VERSION 5.8 ;
BUSBITCHARS "[]" ;
DIVIDERCHAR "/" ;
UNITS
    DATABASE MICRONS 1000 ;
END UNITS

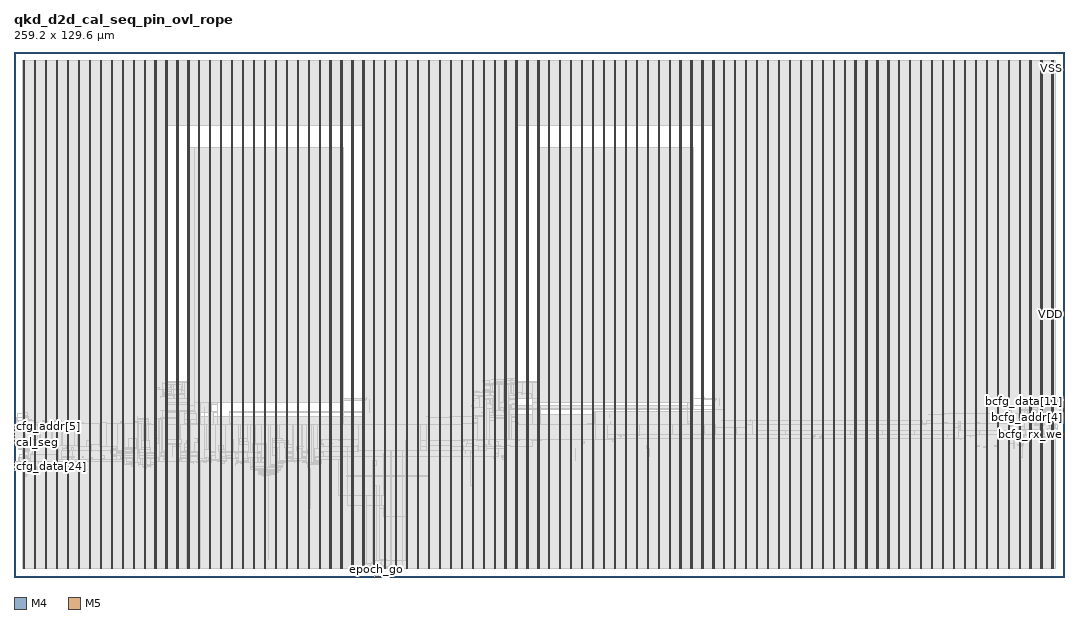
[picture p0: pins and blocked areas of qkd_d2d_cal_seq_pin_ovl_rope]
MACRO qkd_d2d_cal_seq_pin_ovl_rope
  FOREIGN qkd_d2d_cal_seq_pin_ovl_rope 0 0 ;
  CLASS BLOCK ;
  SIZE 259.2 BY 129.6 ;
  PIN adm_done
    DIRECTION OUTPUT ;
    USE SIGNAL ;
    PORT
      LAYER M4 ;
        RECT  259.116 38.736 259.2 38.76 ;
    END
  END adm_done
  PIN bcfg_addr[0]
    DIRECTION INPUT ;
    USE SIGNAL ;
    PORT
      LAYER M4 ;
        RECT  259.116 38.88 259.2 38.904 ;
    END
  END bcfg_addr[0]
  PIN bcfg_addr[1]
    DIRECTION INPUT ;
    USE SIGNAL ;
    PORT
      LAYER M4 ;
        RECT  259.116 39.024 259.2 39.048 ;
    END
  END bcfg_addr[1]
  PIN bcfg_addr[2]
    DIRECTION INPUT ;
    USE SIGNAL ;
    PORT
      LAYER M4 ;
        RECT  259.116 39.168 259.2 39.192 ;
    END
  END bcfg_addr[2]
  PIN bcfg_addr[3]
    DIRECTION INPUT ;
    USE SIGNAL ;
    PORT
      LAYER M4 ;
        RECT  259.116 39.312 259.2 39.336 ;
    END
  END bcfg_addr[3]
  PIN bcfg_addr[4]
    DIRECTION INPUT ;
    USE SIGNAL ;
    PORT
      LAYER M4 ;
        RECT  259.116 39.456 259.2 39.48 ;
    END
  END bcfg_addr[4]
  PIN bcfg_addr[5]
    DIRECTION INPUT ;
    USE SIGNAL ;
    PORT
      LAYER M4 ;
        RECT  259.116 39.6 259.2 39.624 ;
    END
  END bcfg_addr[5]
  PIN bcfg_data[0]
    DIRECTION INPUT ;
    USE SIGNAL ;
    PORT
      LAYER M4 ;
        RECT  259.116 39.744 259.2 39.768 ;
    END
  END bcfg_data[0]
  PIN bcfg_data[10]
    DIRECTION INPUT ;
    USE SIGNAL ;
    PORT
      LAYER M4 ;
        RECT  259.116 41.184 259.2 41.208 ;
    END
  END bcfg_data[10]
  PIN bcfg_data[11]
    DIRECTION INPUT ;
    USE SIGNAL ;
    PORT
      LAYER M4 ;
        RECT  259.116 41.328 259.2 41.352 ;
    END
  END bcfg_data[11]
  PIN bcfg_data[12]
    DIRECTION INPUT ;
    USE SIGNAL ;
    PORT
      LAYER M4 ;
        RECT  259.116 41.472 259.2 41.496 ;
    END
  END bcfg_data[12]
  PIN bcfg_data[13]
    DIRECTION INPUT ;
    USE SIGNAL ;
    PORT
      LAYER M4 ;
        RECT  259.116 41.616 259.2 41.64 ;
    END
  END bcfg_data[13]
  PIN bcfg_data[14]
    DIRECTION INPUT ;
    USE SIGNAL ;
    PORT
      LAYER M4 ;
        RECT  259.116 41.76 259.2 41.784 ;
    END
  END bcfg_data[14]
  PIN bcfg_data[15]
    DIRECTION INPUT ;
    USE SIGNAL ;
    PORT
      LAYER M4 ;
        RECT  259.116 41.904 259.2 41.928 ;
    END
  END bcfg_data[15]
  PIN bcfg_data[16]
    DIRECTION INPUT ;
    USE SIGNAL ;
    PORT
      LAYER M4 ;
        RECT  259.116 42.048 259.2 42.072 ;
    END
  END bcfg_data[16]
  PIN bcfg_data[17]
    DIRECTION INPUT ;
    USE SIGNAL ;
    PORT
      LAYER M4 ;
        RECT  259.116 42.192 259.2 42.216 ;
    END
  END bcfg_data[17]
  PIN bcfg_data[18]
    DIRECTION INPUT ;
    USE SIGNAL ;
    PORT
      LAYER M4 ;
        RECT  259.116 42.336 259.2 42.36 ;
    END
  END bcfg_data[18]
  PIN bcfg_data[19]
    DIRECTION INPUT ;
    USE SIGNAL ;
    PORT
      LAYER M4 ;
        RECT  259.116 42.48 259.2 42.504 ;
    END
  END bcfg_data[19]
  PIN bcfg_data[1]
    DIRECTION INPUT ;
    USE SIGNAL ;
    PORT
      LAYER M4 ;
        RECT  259.116 39.888 259.2 39.912 ;
    END
  END bcfg_data[1]
  PIN bcfg_data[20]
    DIRECTION INPUT ;
    USE SIGNAL ;
    PORT
      LAYER M4 ;
        RECT  259.116 42.624 259.2 42.648 ;
    END
  END bcfg_data[20]
  PIN bcfg_data[21]
    DIRECTION INPUT ;
    USE SIGNAL ;
    PORT
      LAYER M4 ;
        RECT  259.116 42.768 259.2 42.792 ;
    END
  END bcfg_data[21]
  PIN bcfg_data[22]
    DIRECTION INPUT ;
    USE SIGNAL ;
    PORT
      LAYER M4 ;
        RECT  259.116 42.912 259.2 42.936 ;
    END
  END bcfg_data[22]
  PIN bcfg_data[23]
    DIRECTION INPUT ;
    USE SIGNAL ;
    PORT
      LAYER M4 ;
        RECT  259.116 43.056 259.2 43.08 ;
    END
  END bcfg_data[23]
  PIN bcfg_data[24]
    DIRECTION INPUT ;
    USE SIGNAL ;
    PORT
      LAYER M4 ;
        RECT  259.116 43.2 259.2 43.224 ;
    END
  END bcfg_data[24]
  PIN bcfg_data[25]
    DIRECTION INPUT ;
    USE SIGNAL ;
    PORT
      LAYER M4 ;
        RECT  259.116 34.128 259.2 34.152 ;
    END
  END bcfg_data[25]
  PIN bcfg_data[26]
    DIRECTION INPUT ;
    USE SIGNAL ;
    PORT
      LAYER M4 ;
        RECT  259.116 34.272 259.2 34.296 ;
    END
  END bcfg_data[26]
  PIN bcfg_data[27]
    DIRECTION INPUT ;
    USE SIGNAL ;
    PORT
      LAYER M4 ;
        RECT  259.116 34.416 259.2 34.44 ;
    END
  END bcfg_data[27]
  PIN bcfg_data[28]
    DIRECTION INPUT ;
    USE SIGNAL ;
    PORT
      LAYER M4 ;
        RECT  259.116 34.56 259.2 34.584 ;
    END
  END bcfg_data[28]
  PIN bcfg_data[29]
    DIRECTION INPUT ;
    USE SIGNAL ;
    PORT
      LAYER M4 ;
        RECT  259.116 34.704 259.2 34.728 ;
    END
  END bcfg_data[29]
  PIN bcfg_data[2]
    DIRECTION INPUT ;
    USE SIGNAL ;
    PORT
      LAYER M4 ;
        RECT  259.116 40.032 259.2 40.056 ;
    END
  END bcfg_data[2]
  PIN bcfg_data[30]
    DIRECTION INPUT ;
    USE SIGNAL ;
    PORT
      LAYER M4 ;
        RECT  259.116 34.848 259.2 34.872 ;
    END
  END bcfg_data[30]
  PIN bcfg_data[31]
    DIRECTION INPUT ;
    USE SIGNAL ;
    PORT
      LAYER M4 ;
        RECT  259.116 34.992 259.2 35.016 ;
    END
  END bcfg_data[31]
  PIN bcfg_data[3]
    DIRECTION INPUT ;
    USE SIGNAL ;
    PORT
      LAYER M4 ;
        RECT  259.116 40.176 259.2 40.2 ;
    END
  END bcfg_data[3]
  PIN bcfg_data[4]
    DIRECTION INPUT ;
    USE SIGNAL ;
    PORT
      LAYER M4 ;
        RECT  259.116 40.32 259.2 40.344 ;
    END
  END bcfg_data[4]
  PIN bcfg_data[5]
    DIRECTION INPUT ;
    USE SIGNAL ;
    PORT
      LAYER M4 ;
        RECT  259.116 40.464 259.2 40.488 ;
    END
  END bcfg_data[5]
  PIN bcfg_data[6]
    DIRECTION INPUT ;
    USE SIGNAL ;
    PORT
      LAYER M4 ;
        RECT  259.116 40.608 259.2 40.632 ;
    END
  END bcfg_data[6]
  PIN bcfg_data[7]
    DIRECTION INPUT ;
    USE SIGNAL ;
    PORT
      LAYER M4 ;
        RECT  259.116 40.752 259.2 40.776 ;
    END
  END bcfg_data[7]
  PIN bcfg_data[8]
    DIRECTION INPUT ;
    USE SIGNAL ;
    PORT
      LAYER M4 ;
        RECT  259.116 40.896 259.2 40.92 ;
    END
  END bcfg_data[8]
  PIN bcfg_data[9]
    DIRECTION INPUT ;
    USE SIGNAL ;
    PORT
      LAYER M4 ;
        RECT  259.116 41.04 259.2 41.064 ;
    END
  END bcfg_data[9]
  PIN bcfg_rx_we
    DIRECTION INPUT ;
    USE SIGNAL ;
    PORT
      LAYER M4 ;
        RECT  259.116 35.136 259.2 35.16 ;
    END
  END bcfg_rx_we
  PIN bcfg_tx_we
    DIRECTION INPUT ;
    USE SIGNAL ;
    PORT
      LAYER M4 ;
        RECT  259.116 35.28 259.2 35.304 ;
    END
  END bcfg_tx_we
  PIN cal_ready
    DIRECTION OUTPUT ;
    USE SIGNAL ;
    PORT
      LAYER M4 ;
        RECT  259.116 35.424 259.2 35.448 ;
    END
  END cal_ready
  PIN cal_seg
    DIRECTION OUTPUT ;
    USE SIGNAL ;
    PORT
      LAYER M4 ;
        RECT  0 33.264 0.084 33.288 ;
    END
  END cal_seg
  PIN cal_seg_rx
    DIRECTION OUTPUT ;
    USE SIGNAL ;
    PORT
      LAYER M4 ;
        RECT  0 33.408 0.084 33.432 ;
    END
  END cal_seg_rx
  PIN cal_start
    DIRECTION OUTPUT ;
    USE SIGNAL ;
    PORT
      LAYER M4 ;
        RECT  0 33.552 0.084 33.576 ;
    END
  END cal_start
  PIN cal_start_rx
    DIRECTION OUTPUT ;
    USE SIGNAL ;
    PORT
      LAYER M4 ;
        RECT  0 33.696 0.084 33.72 ;
    END
  END cal_start_rx
  PIN cal_user_rx[0]
    DIRECTION OUTPUT ;
    USE SIGNAL ;
    PORT
      LAYER M4 ;
        RECT  0 33.84 0.084 33.864 ;
    END
  END cal_user_rx[0]
  PIN cal_user_rx[1]
    DIRECTION OUTPUT ;
    USE SIGNAL ;
    PORT
      LAYER M4 ;
        RECT  0 33.984 0.084 34.008 ;
    END
  END cal_user_rx[1]
  PIN cal_user_tx[0]
    DIRECTION OUTPUT ;
    USE SIGNAL ;
    PORT
      LAYER M4 ;
        RECT  0 34.128 0.084 34.152 ;
    END
  END cal_user_tx[0]
  PIN cal_user_tx[1]
    DIRECTION OUTPUT ;
    USE SIGNAL ;
    PORT
      LAYER M4 ;
        RECT  0 34.272 0.084 34.296 ;
    END
  END cal_user_tx[1]
  PIN cfg_addr[0]
    DIRECTION OUTPUT ;
    USE SIGNAL ;
    PORT
      LAYER M4 ;
        RECT  0 34.416 0.084 34.44 ;
    END
  END cfg_addr[0]
  PIN cfg_addr[1]
    DIRECTION OUTPUT ;
    USE SIGNAL ;
    PORT
      LAYER M4 ;
        RECT  0 34.56 0.084 34.584 ;
    END
  END cfg_addr[1]
  PIN cfg_addr[2]
    DIRECTION OUTPUT ;
    USE SIGNAL ;
    PORT
      LAYER M4 ;
        RECT  0 34.704 0.084 34.728 ;
    END
  END cfg_addr[2]
  PIN cfg_addr[3]
    DIRECTION OUTPUT ;
    USE SIGNAL ;
    PORT
      LAYER M4 ;
        RECT  0 34.848 0.084 34.872 ;
    END
  END cfg_addr[3]
  PIN cfg_addr[4]
    DIRECTION OUTPUT ;
    USE SIGNAL ;
    PORT
      LAYER M4 ;
        RECT  0 34.992 0.084 35.016 ;
    END
  END cfg_addr[4]
  PIN cfg_addr[5]
    DIRECTION OUTPUT ;
    USE SIGNAL ;
    PORT
      LAYER M4 ;
        RECT  0 35.136 0.084 35.16 ;
    END
  END cfg_addr[5]
  PIN cfg_data[0]
    DIRECTION OUTPUT ;
    USE SIGNAL ;
    PORT
      LAYER M4 ;
        RECT  0 35.28 0.084 35.304 ;
    END
  END cfg_data[0]
  PIN cfg_data[10]
    DIRECTION OUTPUT ;
    USE SIGNAL ;
    PORT
      LAYER M4 ;
        RECT  0 36.72 0.084 36.744 ;
    END
  END cfg_data[10]
  PIN cfg_data[11]
    DIRECTION OUTPUT ;
    USE SIGNAL ;
    PORT
      LAYER M4 ;
        RECT  0 36.864 0.084 36.888 ;
    END
  END cfg_data[11]
  PIN cfg_data[12]
    DIRECTION OUTPUT ;
    USE SIGNAL ;
    PORT
      LAYER M4 ;
        RECT  0 37.008 0.084 37.032 ;
    END
  END cfg_data[12]
  PIN cfg_data[13]
    DIRECTION OUTPUT ;
    USE SIGNAL ;
    PORT
      LAYER M4 ;
        RECT  0 37.152 0.084 37.176 ;
    END
  END cfg_data[13]
  PIN cfg_data[14]
    DIRECTION OUTPUT ;
    USE SIGNAL ;
    PORT
      LAYER M4 ;
        RECT  0 37.296 0.084 37.32 ;
    END
  END cfg_data[14]
  PIN cfg_data[15]
    DIRECTION OUTPUT ;
    USE SIGNAL ;
    PORT
      LAYER M4 ;
        RECT  0 37.44 0.084 37.464 ;
    END
  END cfg_data[15]
  PIN cfg_data[16]
    DIRECTION OUTPUT ;
    USE SIGNAL ;
    PORT
      LAYER M4 ;
        RECT  0 37.584 0.084 37.608 ;
    END
  END cfg_data[16]
  PIN cfg_data[17]
    DIRECTION OUTPUT ;
    USE SIGNAL ;
    PORT
      LAYER M4 ;
        RECT  0 37.728 0.084 37.752 ;
    END
  END cfg_data[17]
  PIN cfg_data[18]
    DIRECTION OUTPUT ;
    USE SIGNAL ;
    PORT
      LAYER M4 ;
        RECT  0 26.352 0.084 26.376 ;
    END
  END cfg_data[18]
  PIN cfg_data[19]
    DIRECTION OUTPUT ;
    USE SIGNAL ;
    PORT
      LAYER M4 ;
        RECT  0 26.496 0.084 26.52 ;
    END
  END cfg_data[19]
  PIN cfg_data[1]
    DIRECTION OUTPUT ;
    USE SIGNAL ;
    PORT
      LAYER M4 ;
        RECT  0 35.424 0.084 35.448 ;
    END
  END cfg_data[1]
  PIN cfg_data[20]
    DIRECTION OUTPUT ;
    USE SIGNAL ;
    PORT
      LAYER M4 ;
        RECT  0 26.64 0.084 26.664 ;
    END
  END cfg_data[20]
  PIN cfg_data[21]
    DIRECTION OUTPUT ;
    USE SIGNAL ;
    PORT
      LAYER M4 ;
        RECT  0 26.784 0.084 26.808 ;
    END
  END cfg_data[21]
  PIN cfg_data[22]
    DIRECTION OUTPUT ;
    USE SIGNAL ;
    PORT
      LAYER M4 ;
        RECT  0 26.928 0.084 26.952 ;
    END
  END cfg_data[22]
  PIN cfg_data[23]
    DIRECTION OUTPUT ;
    USE SIGNAL ;
    PORT
      LAYER M4 ;
        RECT  0 27.072 0.084 27.096 ;
    END
  END cfg_data[23]
  PIN cfg_data[24]
    DIRECTION OUTPUT ;
    USE SIGNAL ;
    PORT
      LAYER M4 ;
        RECT  0 27.216 0.084 27.24 ;
    END
  END cfg_data[24]
  PIN cfg_data[25]
    DIRECTION OUTPUT ;
    USE SIGNAL ;
    PORT
      LAYER M4 ;
        RECT  0 27.36 0.084 27.384 ;
    END
  END cfg_data[25]
  PIN cfg_data[26]
    DIRECTION OUTPUT ;
    USE SIGNAL ;
    PORT
      LAYER M4 ;
        RECT  0 27.504 0.084 27.528 ;
    END
  END cfg_data[26]
  PIN cfg_data[27]
    DIRECTION OUTPUT ;
    USE SIGNAL ;
    PORT
      LAYER M4 ;
        RECT  0 27.648 0.084 27.672 ;
    END
  END cfg_data[27]
  PIN cfg_data[28]
    DIRECTION OUTPUT ;
    USE SIGNAL ;
    PORT
      LAYER M4 ;
        RECT  0 27.792 0.084 27.816 ;
    END
  END cfg_data[28]
  PIN cfg_data[29]
    DIRECTION OUTPUT ;
    USE SIGNAL ;
    PORT
      LAYER M4 ;
        RECT  0 27.936 0.084 27.96 ;
    END
  END cfg_data[29]
  PIN cfg_data[2]
    DIRECTION OUTPUT ;
    USE SIGNAL ;
    PORT
      LAYER M4 ;
        RECT  0 35.568 0.084 35.592 ;
    END
  END cfg_data[2]
  PIN cfg_data[30]
    DIRECTION OUTPUT ;
    USE SIGNAL ;
    PORT
      LAYER M4 ;
        RECT  0 28.08 0.084 28.104 ;
    END
  END cfg_data[30]
  PIN cfg_data[31]
    DIRECTION OUTPUT ;
    USE SIGNAL ;
    PORT
      LAYER M4 ;
        RECT  0 28.224 0.084 28.248 ;
    END
  END cfg_data[31]
  PIN cfg_data[3]
    DIRECTION OUTPUT ;
    USE SIGNAL ;
    PORT
      LAYER M4 ;
        RECT  0 35.712 0.084 35.736 ;
    END
  END cfg_data[3]
  PIN cfg_data[4]
    DIRECTION OUTPUT ;
    USE SIGNAL ;
    PORT
      LAYER M4 ;
        RECT  0 35.856 0.084 35.88 ;
    END
  END cfg_data[4]
  PIN cfg_data[5]
    DIRECTION OUTPUT ;
    USE SIGNAL ;
    PORT
      LAYER M4 ;
        RECT  0 36 0.084 36.024 ;
    END
  END cfg_data[5]
  PIN cfg_data[6]
    DIRECTION OUTPUT ;
    USE SIGNAL ;
    PORT
      LAYER M4 ;
        RECT  0 36.144 0.084 36.168 ;
    END
  END cfg_data[6]
  PIN cfg_data[7]
    DIRECTION OUTPUT ;
    USE SIGNAL ;
    PORT
      LAYER M4 ;
        RECT  0 36.288 0.084 36.312 ;
    END
  END cfg_data[7]
  PIN cfg_data[8]
    DIRECTION OUTPUT ;
    USE SIGNAL ;
    PORT
      LAYER M4 ;
        RECT  0 36.432 0.084 36.456 ;
    END
  END cfg_data[8]
  PIN cfg_data[9]
    DIRECTION OUTPUT ;
    USE SIGNAL ;
    PORT
      LAYER M4 ;
        RECT  0 36.576 0.084 36.6 ;
    END
  END cfg_data[9]
  PIN cfg_rx_we
    DIRECTION OUTPUT ;
    USE SIGNAL ;
    PORT
      LAYER M4 ;
        RECT  0 28.368 0.084 28.392 ;
    END
  END cfg_rx_we
  PIN cfg_tx_we
    DIRECTION OUTPUT ;
    USE SIGNAL ;
    PORT
      LAYER M4 ;
        RECT  0 28.512 0.084 28.536 ;
    END
  END cfg_tx_we
  PIN ck
    DIRECTION INPUT ;
    USE SIGNAL ;
    PORT
      LAYER M5 ;
        RECT  89.28 0 89.304 0.084 ;
    END
  END ck
  PIN epoch_go
    DIRECTION INPUT ;
    USE SIGNAL ;
    PORT
      LAYER M5 ;
        RECT  89.424 0 89.448 0.084 ;
    END
  END epoch_go
  PIN fault
    DIRECTION OUTPUT ;
    USE SIGNAL ;
    PORT
      LAYER M4 ;
        RECT  259.116 35.568 259.2 35.592 ;
    END
  END fault
  PIN halt
    DIRECTION INPUT ;
    USE SIGNAL ;
    PORT
      LAYER M5 ;
        RECT  89.568 0 89.592 0.084 ;
    END
  END halt
  PIN reload
    DIRECTION INPUT ;
    USE SIGNAL ;
    PORT
      LAYER M5 ;
        RECT  89.712 0 89.736 0.084 ;
    END
  END reload
  PIN rst_n
    DIRECTION INPUT ;
    USE SIGNAL ;
    PORT
      LAYER M5 ;
        RECT  89.856 0 89.88 0.084 ;
    END
  END rst_n
  PIN running
    DIRECTION OUTPUT ;
    USE SIGNAL ;
    PORT
      LAYER M4 ;
        RECT  259.116 35.712 259.2 35.736 ;
    END
  END running
  PIN VDD
    DIRECTION INOUT ;
    USE POWER ;
    PORT
      LAYER M5 ;
        RECT  256.392 2.151 256.512 127.449 ;
        RECT  253.692 2.151 253.812 127.449 ;
        RECT  250.992 2.151 251.112 127.449 ;
        RECT  248.292 2.151 248.412 127.449 ;
        RECT  245.592 2.151 245.712 127.449 ;
        RECT  242.892 2.151 243.012 127.449 ;
        RECT  240.192 2.151 240.312 127.449 ;
        RECT  237.492 2.151 237.612 127.449 ;
        RECT  234.792 2.151 234.912 127.449 ;
        RECT  232.092 2.151 232.212 127.449 ;
        RECT  229.392 2.151 229.512 127.449 ;
        RECT  226.692 2.151 226.812 127.449 ;
        RECT  223.992 2.151 224.112 127.449 ;
        RECT  221.292 2.151 221.412 127.449 ;
        RECT  218.592 2.151 218.712 127.449 ;
        RECT  215.892 2.151 216.012 127.449 ;
        RECT  213.192 2.151 213.312 127.449 ;
        RECT  210.492 2.151 210.612 127.449 ;
        RECT  207.792 2.151 207.912 127.449 ;
        RECT  205.092 2.151 205.212 127.449 ;
        RECT  202.392 2.151 202.512 127.449 ;
        RECT  199.692 2.151 199.812 127.449 ;
        RECT  196.992 2.151 197.112 127.449 ;
        RECT  194.292 2.151 194.412 127.449 ;
        RECT  191.592 2.151 191.712 127.449 ;
        RECT  188.892 2.151 189.012 127.449 ;
        RECT  186.192 2.151 186.312 127.449 ;
        RECT  183.492 2.151 183.612 127.449 ;
        RECT  180.792 2.151 180.912 127.449 ;
        RECT  178.092 2.151 178.212 127.449 ;
        RECT  175.392 2.151 175.512 127.449 ;
        RECT  172.692 2.151 172.812 127.449 ;
        RECT  169.992 2.151 170.112 127.449 ;
        RECT  167.292 2.151 167.412 127.449 ;
        RECT  164.592 2.151 164.712 127.449 ;
        RECT  161.892 2.151 162.012 127.449 ;
        RECT  159.192 2.151 159.312 127.449 ;
        RECT  156.492 2.151 156.612 127.449 ;
        RECT  153.792 2.151 153.912 127.449 ;
        RECT  151.092 2.151 151.212 127.449 ;
        RECT  148.392 2.151 148.512 127.449 ;
        RECT  145.692 2.151 145.812 127.449 ;
        RECT  142.992 2.151 143.112 127.449 ;
        RECT  140.292 2.151 140.412 127.449 ;
        RECT  137.592 2.151 137.712 127.449 ;
        RECT  134.892 2.151 135.012 127.449 ;
        RECT  132.192 2.151 132.312 127.449 ;
        RECT  129.492 2.151 129.612 127.449 ;
        RECT  126.792 2.151 126.912 127.449 ;
        RECT  124.092 2.151 124.212 127.449 ;
        RECT  121.392 2.151 121.512 127.449 ;
        RECT  118.692 2.151 118.812 127.449 ;
        RECT  115.992 2.151 116.112 127.449 ;
        RECT  113.292 2.151 113.412 127.449 ;
        RECT  110.592 2.151 110.712 127.449 ;
        RECT  107.892 2.151 108.012 127.449 ;
        RECT  105.192 2.151 105.312 127.449 ;
        RECT  102.492 2.151 102.612 127.449 ;
        RECT  99.792 2.151 99.912 127.449 ;
        RECT  97.092 2.151 97.212 127.449 ;
        RECT  94.392 2.151 94.512 127.449 ;
        RECT  91.692 2.151 91.812 127.449 ;
        RECT  88.992 2.151 89.112 127.449 ;
        RECT  86.292 2.151 86.412 127.449 ;
        RECT  83.592 2.151 83.712 127.449 ;
        RECT  80.892 2.151 81.012 127.449 ;
        RECT  78.192 2.151 78.312 127.449 ;
        RECT  75.492 2.151 75.612 127.449 ;
        RECT  72.792 2.151 72.912 127.449 ;
        RECT  70.092 2.151 70.212 127.449 ;
        RECT  67.392 2.151 67.512 127.449 ;
        RECT  64.692 2.151 64.812 127.449 ;
        RECT  61.992 2.151 62.112 127.449 ;
        RECT  59.292 2.151 59.412 127.449 ;
        RECT  56.592 2.151 56.712 127.449 ;
        RECT  53.892 2.151 54.012 127.449 ;
        RECT  51.192 2.151 51.312 127.449 ;
        RECT  48.492 2.151 48.612 127.449 ;
        RECT  45.792 2.151 45.912 127.449 ;
        RECT  43.092 2.151 43.212 127.449 ;
        RECT  40.392 2.151 40.512 127.449 ;
        RECT  37.692 2.151 37.812 127.449 ;
        RECT  34.992 2.151 35.112 127.449 ;
        RECT  32.292 2.151 32.412 127.449 ;
        RECT  29.592 2.151 29.712 127.449 ;
        RECT  26.892 2.151 27.012 127.449 ;
        RECT  24.192 2.151 24.312 127.449 ;
        RECT  21.492 2.151 21.612 127.449 ;
        RECT  18.792 2.151 18.912 127.449 ;
        RECT  16.092 2.151 16.212 127.449 ;
        RECT  13.392 2.151 13.512 127.449 ;
        RECT  10.692 2.151 10.812 127.449 ;
        RECT  7.992 2.151 8.112 127.449 ;
        RECT  5.292 2.151 5.412 127.449 ;
        RECT  2.592 2.151 2.712 127.449 ;
    END
  END VDD
  PIN VSS
    DIRECTION INOUT ;
    USE GROUND ;
    PORT
      LAYER M5 ;
        RECT  256.2 2.137 256.32 127.463 ;
        RECT  253.5 2.137 253.62 127.463 ;
        RECT  250.8 2.137 250.92 127.463 ;
        RECT  248.1 2.137 248.22 127.463 ;
        RECT  245.4 2.137 245.52 127.463 ;
        RECT  242.7 2.137 242.82 127.463 ;
        RECT  240 2.137 240.12 127.463 ;
        RECT  237.3 2.137 237.42 127.463 ;
        RECT  234.6 2.137 234.72 127.463 ;
        RECT  231.9 2.137 232.02 127.463 ;
        RECT  229.2 2.137 229.32 127.463 ;
        RECT  226.5 2.137 226.62 127.463 ;
        RECT  223.8 2.137 223.92 127.463 ;
        RECT  221.1 2.137 221.22 127.463 ;
        RECT  218.4 2.137 218.52 127.463 ;
        RECT  215.7 2.137 215.82 127.463 ;
        RECT  213 2.137 213.12 127.463 ;
        RECT  210.3 2.137 210.42 127.463 ;
        RECT  207.6 2.137 207.72 127.463 ;
        RECT  204.9 2.137 205.02 127.463 ;
        RECT  202.2 2.137 202.32 127.463 ;
        RECT  199.5 2.137 199.62 127.463 ;
        RECT  196.8 2.137 196.92 127.463 ;
        RECT  194.1 2.137 194.22 127.463 ;
        RECT  191.4 2.137 191.52 127.463 ;
        RECT  188.7 2.137 188.82 127.463 ;
        RECT  186 2.137 186.12 127.463 ;
        RECT  183.3 2.137 183.42 127.463 ;
        RECT  180.6 2.137 180.72 127.463 ;
        RECT  177.9 2.137 178.02 127.463 ;
        RECT  175.2 2.137 175.32 127.463 ;
        RECT  172.5 2.137 172.62 127.463 ;
        RECT  169.8 2.137 169.92 127.463 ;
        RECT  167.1 2.137 167.22 127.463 ;
        RECT  164.4 2.137 164.52 127.463 ;
        RECT  161.7 2.137 161.82 127.463 ;
        RECT  159 2.137 159.12 127.463 ;
        RECT  156.3 2.137 156.42 127.463 ;
        RECT  153.6 2.137 153.72 127.463 ;
        RECT  150.9 2.137 151.02 127.463 ;
        RECT  148.2 2.137 148.32 127.463 ;
        RECT  145.5 2.137 145.62 127.463 ;
        RECT  142.8 2.137 142.92 127.463 ;
        RECT  140.1 2.137 140.22 127.463 ;
        RECT  137.4 2.137 137.52 127.463 ;
        RECT  134.7 2.137 134.82 127.463 ;
        RECT  132 2.137 132.12 127.463 ;
        RECT  129.3 2.137 129.42 127.463 ;
        RECT  126.6 2.137 126.72 127.463 ;
        RECT  123.9 2.137 124.02 127.463 ;
        RECT  121.2 2.137 121.32 127.463 ;
        RECT  118.5 2.137 118.62 127.463 ;
        RECT  115.8 2.137 115.92 127.463 ;
        RECT  113.1 2.137 113.22 127.463 ;
        RECT  110.4 2.137 110.52 127.463 ;
        RECT  107.7 2.137 107.82 127.463 ;
        RECT  105 2.137 105.12 127.463 ;
        RECT  102.3 2.137 102.42 127.463 ;
        RECT  99.6 2.137 99.72 127.463 ;
        RECT  96.9 2.137 97.02 127.463 ;
        RECT  94.2 2.137 94.32 127.463 ;
        RECT  91.5 2.137 91.62 127.463 ;
        RECT  88.8 2.137 88.92 127.463 ;
        RECT  86.1 2.137 86.22 127.463 ;
        RECT  83.4 2.137 83.52 127.463 ;
        RECT  80.7 2.137 80.82 127.463 ;
        RECT  78 2.137 78.12 127.463 ;
        RECT  75.3 2.137 75.42 127.463 ;
        RECT  72.6 2.137 72.72 127.463 ;
        RECT  69.9 2.137 70.02 127.463 ;
        RECT  67.2 2.137 67.32 127.463 ;
        RECT  64.5 2.137 64.62 127.463 ;
        RECT  61.8 2.137 61.92 127.463 ;
        RECT  59.1 2.137 59.22 127.463 ;
        RECT  56.4 2.137 56.52 127.463 ;
        RECT  53.7 2.137 53.82 127.463 ;
        RECT  51 2.137 51.12 127.463 ;
        RECT  48.3 2.137 48.42 127.463 ;
        RECT  45.6 2.137 45.72 127.463 ;
        RECT  42.9 2.137 43.02 127.463 ;
        RECT  40.2 2.137 40.32 127.463 ;
        RECT  37.5 2.137 37.62 127.463 ;
        RECT  34.8 2.137 34.92 127.463 ;
        RECT  32.1 2.137 32.22 127.463 ;
        RECT  29.4 2.137 29.52 127.463 ;
        RECT  26.7 2.137 26.82 127.463 ;
        RECT  24 2.137 24.12 127.463 ;
        RECT  21.3 2.137 21.42 127.463 ;
        RECT  18.6 2.137 18.72 127.463 ;
        RECT  15.9 2.137 16.02 127.463 ;
        RECT  13.2 2.137 13.32 127.463 ;
        RECT  10.5 2.137 10.62 127.463 ;
        RECT  7.8 2.137 7.92 127.463 ;
        RECT  5.1 2.137 5.22 127.463 ;
        RECT  2.4 2.137 2.52 127.463 ;
    END
  END VSS
  # OT_OBS_CLOSED layer=M5 d_um=1.536 added=158
  OBS
    LAYER RVTN ;
     RECT  2.16 2.16 257.04 2.295 ;
     RECT  2.16 2.565 257.04 2.835 ;
     RECT  2.16 3.105 257.04 3.375 ;
     RECT  2.16 3.645 257.04 3.915 ;
     RECT  2.16 4.185 257.04 4.455 ;
     RECT  2.16 4.725 257.04 4.995 ;
     RECT  2.16 5.265 257.04 5.535 ;
     RECT  2.16 5.805 257.04 6.075 ;
     RECT  2.16 6.345 257.04 6.615 ;
     RECT  2.16 6.885 257.04 7.155 ;
     RECT  2.16 7.425 257.04 7.695 ;
     RECT  2.16 7.965 257.04 8.235 ;
     RECT  2.16 8.505 257.04 8.775 ;
     RECT  2.16 9.045 257.04 9.315 ;
     RECT  2.16 9.585 257.04 9.855 ;
     RECT  2.16 10.125 257.04 10.395 ;
     RECT  2.16 10.665 257.04 10.935 ;
     RECT  2.16 11.205 257.04 11.475 ;
     RECT  2.16 11.745 257.04 12.015 ;
     RECT  2.16 12.285 257.04 12.555 ;
     RECT  2.16 12.825 257.04 13.095 ;
     RECT  2.16 13.365 257.04 13.635 ;
     RECT  2.16 13.905 257.04 14.175 ;
     RECT  2.16 14.445 257.04 14.715 ;
     RECT  2.16 14.985 257.04 15.255 ;
     RECT  2.16 15.525 257.04 15.795 ;
     RECT  2.16 16.065 257.04 16.335 ;
     RECT  2.16 16.605 257.04 16.875 ;
     RECT  2.16 17.145 257.04 17.415 ;
     RECT  2.16 17.685 257.04 17.955 ;
     RECT  2.16 18.225 257.04 18.495 ;
     RECT  2.16 18.765 257.04 19.035 ;
     RECT  2.16 19.305 257.04 19.575 ;
     RECT  2.16 19.845 257.04 20.115 ;
     RECT  2.16 20.385 257.04 20.655 ;
     RECT  2.16 20.925 257.04 21.195 ;
     RECT  2.16 21.465 257.04 21.735 ;
     RECT  2.16 22.005 257.04 22.275 ;
     RECT  2.16 22.545 257.04 22.815 ;
     RECT  2.16 23.085 257.04 23.355 ;
     RECT  2.16 23.625 257.04 23.895 ;
     RECT  2.16 24.165 257.04 24.435 ;
     RECT  2.16 24.705 257.04 24.975 ;
     RECT  2.16 25.245 257.04 25.515 ;
     RECT  2.16 25.785 257.04 26.055 ;
     RECT  2.16 26.325 257.04 26.595 ;
     RECT  2.16 26.865 257.04 27.135 ;
     RECT  2.16 27.405 257.04 27.675 ;
     RECT  2.16 27.945 257.04 28.215 ;
     RECT  2.16 28.485 257.04 28.755 ;
     RECT  2.16 29.025 257.04 29.295 ;
     RECT  2.16 29.565 257.04 29.835 ;
     RECT  2.16 30.105 257.04 30.375 ;
     RECT  2.16 30.645 257.04 30.915 ;
     RECT  2.16 31.185 257.04 31.455 ;
     RECT  2.16 31.725 257.04 31.995 ;
     RECT  2.16 32.265 257.04 32.535 ;
     RECT  2.16 32.805 257.04 33.075 ;
     RECT  2.16 33.345 257.04 33.615 ;
     RECT  2.16 33.885 257.04 34.155 ;
     RECT  2.16 34.425 257.04 34.695 ;
     RECT  2.16 34.965 257.04 35.235 ;
     RECT  2.16 35.505 257.04 35.775 ;
     RECT  2.16 36.045 257.04 36.315 ;
     RECT  2.16 36.585 257.04 36.855 ;
     RECT  2.16 37.125 257.04 37.395 ;
     RECT  2.16 37.665 257.04 37.8 ;
     RECT  2.16 37.8 37.8 37.935 ;
     RECT  86.616 37.8 124.2 37.935 ;
     RECT  173.016 37.8 257.04 37.935 ;
     RECT  2.16 38.205 37.8 38.475 ;
     RECT  86.616 38.205 124.2 38.475 ;
     RECT  173.016 38.205 257.04 38.475 ;
     RECT  2.16 38.745 37.8 39.015 ;
     RECT  86.616 38.745 124.2 39.015 ;
     RECT  173.016 38.745 257.04 39.015 ;
     RECT  2.16 39.285 37.8 39.555 ;
     RECT  86.616 39.285 124.2 39.555 ;
     RECT  173.016 39.285 257.04 39.555 ;
     RECT  2.16 39.825 37.8 40.095 ;
     RECT  86.616 39.825 124.2 40.095 ;
     RECT  173.016 39.825 257.04 40.095 ;
     RECT  2.16 40.365 37.8 40.635 ;
     RECT  86.616 40.365 124.2 40.635 ;
     RECT  173.016 40.365 257.04 40.635 ;
     RECT  2.16 40.905 37.8 41.175 ;
     RECT  86.616 40.905 124.2 41.175 ;
     RECT  173.016 40.905 257.04 41.175 ;
     RECT  2.16 41.445 37.8 41.715 ;
     RECT  86.616 41.445 124.2 41.715 ;
     RECT  173.016 41.445 257.04 41.715 ;
     RECT  2.16 41.985 37.8 42.255 ;
     RECT  86.616 41.985 124.2 42.255 ;
     RECT  173.016 41.985 257.04 42.255 ;
     RECT  2.16 42.525 37.8 42.795 ;
     RECT  86.616 42.525 124.2 42.795 ;
     RECT  173.016 42.525 257.04 42.795 ;
     RECT  2.16 43.065 37.8 43.335 ;
     RECT  86.616 43.065 124.2 43.335 ;
     RECT  173.016 43.065 257.04 43.335 ;
     RECT  2.16 43.605 37.8 43.875 ;
     RECT  86.616 43.605 124.2 43.875 ;
     RECT  173.016 43.605 257.04 43.875 ;
     RECT  2.16 44.145 37.8 44.415 ;
     RECT  86.616 44.145 124.2 44.415 ;
     RECT  173.016 44.145 257.04 44.415 ;
     RECT  2.16 44.685 37.8 44.955 ;
     RECT  86.616 44.685 124.2 44.955 ;
     RECT  173.016 44.685 257.04 44.955 ;
     RECT  2.16 45.225 37.8 45.495 ;
     RECT  86.616 45.225 124.2 45.495 ;
     RECT  173.016 45.225 257.04 45.495 ;
     RECT  2.16 45.765 37.8 46.035 ;
     RECT  86.616 45.765 124.2 46.035 ;
     RECT  173.016 45.765 257.04 46.035 ;
     RECT  2.16 46.305 37.8 46.575 ;
     RECT  86.616 46.305 124.2 46.575 ;
     RECT  173.016 46.305 257.04 46.575 ;
     RECT  2.16 46.845 37.8 47.115 ;
     RECT  86.616 46.845 124.2 47.115 ;
     RECT  173.016 46.845 257.04 47.115 ;
     RECT  2.16 47.385 37.8 47.655 ;
     RECT  86.616 47.385 124.2 47.655 ;
     RECT  173.016 47.385 257.04 47.655 ;
     RECT  2.16 47.925 37.8 48.195 ;
     RECT  86.616 47.925 124.2 48.195 ;
     RECT  173.016 47.925 257.04 48.195 ;
     RECT  2.16 48.465 37.8 48.735 ;
     RECT  86.616 48.465 124.2 48.735 ;
     RECT  173.016 48.465 257.04 48.735 ;
     RECT  2.16 49.005 37.8 49.275 ;
     RECT  86.616 49.005 124.2 49.275 ;
     RECT  173.016 49.005 257.04 49.275 ;
     RECT  2.16 49.545 37.8 49.815 ;
     RECT  86.616 49.545 124.2 49.815 ;
     RECT  173.016 49.545 257.04 49.815 ;
     RECT  2.16 50.085 37.8 50.355 ;
     RECT  86.616 50.085 124.2 50.355 ;
     RECT  173.016 50.085 257.04 50.355 ;
     RECT  2.16 50.625 37.8 50.895 ;
     RECT  86.616 50.625 124.2 50.895 ;
     RECT  173.016 50.625 257.04 50.895 ;
     RECT  2.16 51.165 37.8 51.435 ;
     RECT  86.616 51.165 124.2 51.435 ;
     RECT  173.016 51.165 257.04 51.435 ;
     RECT  2.16 51.705 37.8 51.975 ;
     RECT  86.616 51.705 124.2 51.975 ;
     RECT  173.016 51.705 257.04 51.975 ;
     RECT  2.16 52.245 37.8 52.515 ;
     RECT  86.616 52.245 124.2 52.515 ;
     RECT  173.016 52.245 257.04 52.515 ;
     RECT  2.16 52.785 37.8 53.055 ;
     RECT  86.616 52.785 124.2 53.055 ;
     RECT  173.016 52.785 257.04 53.055 ;
     RECT  2.16 53.325 37.8 53.595 ;
     RECT  86.616 53.325 124.2 53.595 ;
     RECT  173.016 53.325 257.04 53.595 ;
     RECT  2.16 53.865 37.8 54.135 ;
     RECT  86.616 53.865 124.2 54.135 ;
     RECT  173.016 53.865 257.04 54.135 ;
     RECT  2.16 54.405 37.8 54.675 ;
     RECT  86.616 54.405 124.2 54.675 ;
     RECT  173.016 54.405 257.04 54.675 ;
     RECT  2.16 54.945 37.8 55.215 ;
     RECT  86.616 54.945 124.2 55.215 ;
     RECT  173.016 54.945 257.04 55.215 ;
     RECT  2.16 55.485 37.8 55.755 ;
     RECT  86.616 55.485 124.2 55.755 ;
     RECT  173.016 55.485 257.04 55.755 ;
     RECT  2.16 56.025 37.8 56.295 ;
     RECT  86.616 56.025 124.2 56.295 ;
     RECT  173.016 56.025 257.04 56.295 ;
     RECT  2.16 56.565 37.8 56.835 ;
     RECT  86.616 56.565 124.2 56.835 ;
     RECT  173.016 56.565 257.04 56.835 ;
     RECT  2.16 57.105 37.8 57.375 ;
     RECT  86.616 57.105 124.2 57.375 ;
     RECT  173.016 57.105 257.04 57.375 ;
     RECT  2.16 57.645 37.8 57.915 ;
     RECT  86.616 57.645 124.2 57.915 ;
     RECT  173.016 57.645 257.04 57.915 ;
     RECT  2.16 58.185 37.8 58.455 ;
     RECT  86.616 58.185 124.2 58.455 ;
     RECT  173.016 58.185 257.04 58.455 ;
     RECT  2.16 58.725 37.8 58.995 ;
     RECT  86.616 58.725 124.2 58.995 ;
     RECT  173.016 58.725 257.04 58.995 ;
     RECT  2.16 59.265 37.8 59.535 ;
     RECT  86.616 59.265 124.2 59.535 ;
     RECT  173.016 59.265 257.04 59.535 ;
     RECT  2.16 59.805 37.8 60.075 ;
     RECT  86.616 59.805 124.2 60.075 ;
     RECT  173.016 59.805 257.04 60.075 ;
     RECT  2.16 60.345 37.8 60.615 ;
     RECT  86.616 60.345 124.2 60.615 ;
     RECT  173.016 60.345 257.04 60.615 ;
     RECT  2.16 60.885 37.8 61.155 ;
     RECT  86.616 60.885 124.2 61.155 ;
     RECT  173.016 60.885 257.04 61.155 ;
     RECT  2.16 61.425 37.8 61.695 ;
     RECT  86.616 61.425 124.2 61.695 ;
     RECT  173.016 61.425 257.04 61.695 ;
     RECT  2.16 61.965 37.8 62.235 ;
     RECT  86.616 61.965 124.2 62.235 ;
     RECT  173.016 61.965 257.04 62.235 ;
     RECT  2.16 62.505 37.8 62.775 ;
     RECT  86.616 62.505 124.2 62.775 ;
     RECT  173.016 62.505 257.04 62.775 ;
     RECT  2.16 63.045 37.8 63.315 ;
     RECT  86.616 63.045 124.2 63.315 ;
     RECT  173.016 63.045 257.04 63.315 ;
     RECT  2.16 63.585 37.8 63.855 ;
     RECT  86.616 63.585 124.2 63.855 ;
     RECT  173.016 63.585 257.04 63.855 ;
     RECT  2.16 64.125 37.8 64.395 ;
     RECT  86.616 64.125 124.2 64.395 ;
     RECT  173.016 64.125 257.04 64.395 ;
     RECT  2.16 64.665 37.8 64.935 ;
     RECT  86.616 64.665 124.2 64.935 ;
     RECT  173.016 64.665 257.04 64.935 ;
     RECT  2.16 65.205 37.8 65.475 ;
     RECT  86.616 65.205 124.2 65.475 ;
     RECT  173.016 65.205 257.04 65.475 ;
     RECT  2.16 65.745 37.8 66.015 ;
     RECT  86.616 65.745 124.2 66.015 ;
     RECT  173.016 65.745 257.04 66.015 ;
     RECT  2.16 66.285 37.8 66.555 ;
     RECT  86.616 66.285 124.2 66.555 ;
     RECT  173.016 66.285 257.04 66.555 ;
     RECT  2.16 66.825 37.8 67.095 ;
     RECT  86.616 66.825 124.2 67.095 ;
     RECT  173.016 66.825 257.04 67.095 ;
     RECT  2.16 67.365 37.8 67.635 ;
     RECT  86.616 67.365 124.2 67.635 ;
     RECT  173.016 67.365 257.04 67.635 ;
     RECT  2.16 67.905 37.8 68.175 ;
     RECT  86.616 67.905 124.2 68.175 ;
     RECT  173.016 67.905 257.04 68.175 ;
     RECT  2.16 68.445 37.8 68.715 ;
     RECT  86.616 68.445 124.2 68.715 ;
     RECT  173.016 68.445 257.04 68.715 ;
     RECT  2.16 68.985 37.8 69.255 ;
     RECT  86.616 68.985 124.2 69.255 ;
     RECT  173.016 68.985 257.04 69.255 ;
     RECT  2.16 69.525 37.8 69.795 ;
     RECT  86.616 69.525 124.2 69.795 ;
     RECT  173.016 69.525 257.04 69.795 ;
     RECT  2.16 70.065 37.8 70.335 ;
     RECT  86.616 70.065 124.2 70.335 ;
     RECT  173.016 70.065 257.04 70.335 ;
     RECT  2.16 70.605 37.8 70.875 ;
     RECT  86.616 70.605 124.2 70.875 ;
     RECT  173.016 70.605 257.04 70.875 ;
     RECT  2.16 71.145 37.8 71.415 ;
     RECT  86.616 71.145 124.2 71.415 ;
     RECT  173.016 71.145 257.04 71.415 ;
     RECT  2.16 71.685 37.8 71.955 ;
     RECT  86.616 71.685 124.2 71.955 ;
     RECT  173.016 71.685 257.04 71.955 ;
     RECT  2.16 72.225 37.8 72.495 ;
     RECT  86.616 72.225 124.2 72.495 ;
     RECT  173.016 72.225 257.04 72.495 ;
     RECT  2.16 72.765 37.8 73.035 ;
     RECT  86.616 72.765 124.2 73.035 ;
     RECT  173.016 72.765 257.04 73.035 ;
     RECT  2.16 73.305 37.8 73.575 ;
     RECT  86.616 73.305 124.2 73.575 ;
     RECT  173.016 73.305 257.04 73.575 ;
     RECT  2.16 73.845 37.8 74.115 ;
     RECT  86.616 73.845 124.2 74.115 ;
     RECT  173.016 73.845 257.04 74.115 ;
     RECT  2.16 74.385 37.8 74.655 ;
     RECT  86.616 74.385 124.2 74.655 ;
     RECT  173.016 74.385 257.04 74.655 ;
     RECT  2.16 74.925 37.8 75.195 ;
     RECT  86.616 74.925 124.2 75.195 ;
     RECT  173.016 74.925 257.04 75.195 ;
     RECT  2.16 75.465 37.8 75.735 ;
     RECT  86.616 75.465 124.2 75.735 ;
     RECT  173.016 75.465 257.04 75.735 ;
     RECT  2.16 76.005 37.8 76.275 ;
     RECT  86.616 76.005 124.2 76.275 ;
     RECT  173.016 76.005 257.04 76.275 ;
     RECT  2.16 76.545 37.8 76.815 ;
     RECT  86.616 76.545 124.2 76.815 ;
     RECT  173.016 76.545 257.04 76.815 ;
     RECT  2.16 77.085 37.8 77.355 ;
     RECT  86.616 77.085 124.2 77.355 ;
     RECT  173.016 77.085 257.04 77.355 ;
     RECT  2.16 77.625 37.8 77.895 ;
     RECT  86.616 77.625 124.2 77.895 ;
     RECT  173.016 77.625 257.04 77.895 ;
     RECT  2.16 78.165 37.8 78.435 ;
     RECT  86.616 78.165 124.2 78.435 ;
     RECT  173.016 78.165 257.04 78.435 ;
     RECT  2.16 78.705 37.8 78.975 ;
     RECT  86.616 78.705 124.2 78.975 ;
     RECT  173.016 78.705 257.04 78.975 ;
     RECT  2.16 79.245 37.8 79.515 ;
     RECT  86.616 79.245 124.2 79.515 ;
     RECT  173.016 79.245 257.04 79.515 ;
     RECT  2.16 79.785 37.8 80.055 ;
     RECT  86.616 79.785 124.2 80.055 ;
     RECT  173.016 79.785 257.04 80.055 ;
     RECT  2.16 80.325 37.8 80.595 ;
     RECT  86.616 80.325 124.2 80.595 ;
     RECT  173.016 80.325 257.04 80.595 ;
     RECT  2.16 80.865 37.8 81.135 ;
     RECT  86.616 80.865 124.2 81.135 ;
     RECT  173.016 80.865 257.04 81.135 ;
     RECT  2.16 81.405 37.8 81.675 ;
     RECT  86.616 81.405 124.2 81.675 ;
     RECT  173.016 81.405 257.04 81.675 ;
     RECT  2.16 81.945 37.8 82.215 ;
     RECT  86.616 81.945 124.2 82.215 ;
     RECT  173.016 81.945 257.04 82.215 ;
     RECT  2.16 82.485 37.8 82.755 ;
     RECT  86.616 82.485 124.2 82.755 ;
     RECT  173.016 82.485 257.04 82.755 ;
     RECT  2.16 83.025 37.8 83.295 ;
     RECT  86.616 83.025 124.2 83.295 ;
     RECT  173.016 83.025 257.04 83.295 ;
     RECT  2.16 83.565 37.8 83.835 ;
     RECT  86.616 83.565 124.2 83.835 ;
     RECT  173.016 83.565 257.04 83.835 ;
     RECT  2.16 84.105 37.8 84.375 ;
     RECT  86.616 84.105 124.2 84.375 ;
     RECT  173.016 84.105 257.04 84.375 ;
     RECT  2.16 84.645 37.8 84.915 ;
     RECT  86.616 84.645 124.2 84.915 ;
     RECT  173.016 84.645 257.04 84.915 ;
     RECT  2.16 85.185 37.8 85.455 ;
     RECT  86.616 85.185 124.2 85.455 ;
     RECT  173.016 85.185 257.04 85.455 ;
     RECT  2.16 85.725 37.8 85.995 ;
     RECT  86.616 85.725 124.2 85.995 ;
     RECT  173.016 85.725 257.04 85.995 ;
     RECT  2.16 86.265 37.8 86.535 ;
     RECT  86.616 86.265 124.2 86.535 ;
     RECT  173.016 86.265 257.04 86.535 ;
     RECT  2.16 86.805 37.8 87.075 ;
     RECT  86.616 86.805 124.2 87.075 ;
     RECT  173.016 86.805 257.04 87.075 ;
     RECT  2.16 87.345 37.8 87.615 ;
     RECT  86.616 87.345 124.2 87.615 ;
     RECT  173.016 87.345 257.04 87.615 ;
     RECT  2.16 87.885 37.8 88.155 ;
     RECT  86.616 87.885 124.2 88.155 ;
     RECT  173.016 87.885 257.04 88.155 ;
     RECT  2.16 88.425 37.8 88.695 ;
     RECT  86.616 88.425 124.2 88.695 ;
     RECT  173.016 88.425 257.04 88.695 ;
     RECT  2.16 88.965 37.8 89.235 ;
     RECT  86.616 88.965 124.2 89.235 ;
     RECT  173.016 88.965 257.04 89.235 ;
     RECT  2.16 89.505 37.8 89.775 ;
     RECT  86.616 89.505 124.2 89.775 ;
     RECT  173.016 89.505 257.04 89.775 ;
     RECT  2.16 90.045 37.8 90.315 ;
     RECT  86.616 90.045 124.2 90.315 ;
     RECT  173.016 90.045 257.04 90.315 ;
     RECT  2.16 90.585 37.8 90.855 ;
     RECT  86.616 90.585 124.2 90.855 ;
     RECT  173.016 90.585 257.04 90.855 ;
     RECT  2.16 91.125 37.8 91.395 ;
     RECT  86.616 91.125 124.2 91.395 ;
     RECT  173.016 91.125 257.04 91.395 ;
     RECT  2.16 91.665 37.8 91.935 ;
     RECT  86.616 91.665 124.2 91.935 ;
     RECT  173.016 91.665 257.04 91.935 ;
     RECT  2.16 92.205 37.8 92.475 ;
     RECT  86.616 92.205 124.2 92.475 ;
     RECT  173.016 92.205 257.04 92.475 ;
     RECT  2.16 92.745 37.8 93.015 ;
     RECT  86.616 92.745 124.2 93.015 ;
     RECT  173.016 92.745 257.04 93.015 ;
     RECT  2.16 93.285 37.8 93.555 ;
     RECT  86.616 93.285 124.2 93.555 ;
     RECT  173.016 93.285 257.04 93.555 ;
     RECT  2.16 93.825 37.8 94.095 ;
     RECT  86.616 93.825 124.2 94.095 ;
     RECT  173.016 93.825 257.04 94.095 ;
     RECT  2.16 94.365 37.8 94.635 ;
     RECT  86.616 94.365 124.2 94.635 ;
     RECT  173.016 94.365 257.04 94.635 ;
     RECT  2.16 94.905 37.8 95.175 ;
     RECT  86.616 94.905 124.2 95.175 ;
     RECT  173.016 94.905 257.04 95.175 ;
     RECT  2.16 95.445 37.8 95.715 ;
     RECT  86.616 95.445 124.2 95.715 ;
     RECT  173.016 95.445 257.04 95.715 ;
     RECT  2.16 95.985 37.8 96.255 ;
     RECT  86.616 95.985 124.2 96.255 ;
     RECT  173.016 95.985 257.04 96.255 ;
     RECT  2.16 96.525 37.8 96.795 ;
     RECT  86.616 96.525 124.2 96.795 ;
     RECT  173.016 96.525 257.04 96.795 ;
     RECT  2.16 97.065 37.8 97.335 ;
     RECT  86.616 97.065 124.2 97.335 ;
     RECT  173.016 97.065 257.04 97.335 ;
     RECT  2.16 97.605 37.8 97.875 ;
     RECT  86.616 97.605 124.2 97.875 ;
     RECT  173.016 97.605 257.04 97.875 ;
     RECT  2.16 98.145 37.8 98.415 ;
     RECT  86.616 98.145 124.2 98.415 ;
     RECT  173.016 98.145 257.04 98.415 ;
     RECT  2.16 98.685 37.8 98.955 ;
     RECT  86.616 98.685 124.2 98.955 ;
     RECT  173.016 98.685 257.04 98.955 ;
     RECT  2.16 99.225 37.8 99.495 ;
     RECT  86.616 99.225 124.2 99.495 ;
     RECT  173.016 99.225 257.04 99.495 ;
     RECT  2.16 99.765 37.8 100.035 ;
     RECT  86.616 99.765 124.2 100.035 ;
     RECT  173.016 99.765 257.04 100.035 ;
     RECT  2.16 100.305 37.8 100.575 ;
     RECT  86.616 100.305 124.2 100.575 ;
     RECT  173.016 100.305 257.04 100.575 ;
     RECT  2.16 100.845 37.8 101.115 ;
     RECT  86.616 100.845 124.2 101.115 ;
     RECT  173.016 100.845 257.04 101.115 ;
     RECT  2.16 101.385 37.8 101.655 ;
     RECT  86.616 101.385 124.2 101.655 ;
     RECT  173.016 101.385 257.04 101.655 ;
     RECT  2.16 101.925 37.8 102.195 ;
     RECT  86.616 101.925 124.2 102.195 ;
     RECT  173.016 101.925 257.04 102.195 ;
     RECT  2.16 102.465 37.8 102.735 ;
     RECT  86.616 102.465 124.2 102.735 ;
     RECT  173.016 102.465 257.04 102.735 ;
     RECT  2.16 103.005 37.8 103.275 ;
     RECT  86.616 103.005 124.2 103.275 ;
     RECT  173.016 103.005 257.04 103.275 ;
     RECT  2.16 103.545 37.8 103.815 ;
     RECT  86.616 103.545 124.2 103.815 ;
     RECT  173.016 103.545 257.04 103.815 ;
     RECT  2.16 104.085 37.8 104.355 ;
     RECT  86.616 104.085 124.2 104.355 ;
     RECT  173.016 104.085 257.04 104.355 ;
     RECT  2.16 104.625 37.8 104.895 ;
     RECT  86.616 104.625 124.2 104.895 ;
     RECT  173.016 104.625 257.04 104.895 ;
     RECT  2.16 105.165 37.8 105.435 ;
     RECT  86.616 105.165 124.2 105.435 ;
     RECT  173.016 105.165 257.04 105.435 ;
     RECT  2.16 105.705 37.8 105.975 ;
     RECT  86.616 105.705 124.2 105.975 ;
     RECT  173.016 105.705 257.04 105.975 ;
     RECT  2.16 106.245 37.8 106.515 ;
     RECT  86.616 106.245 124.2 106.515 ;
     RECT  173.016 106.245 257.04 106.515 ;
     RECT  2.16 106.785 37.8 107.055 ;
     RECT  86.616 106.785 124.2 107.055 ;
     RECT  173.016 106.785 257.04 107.055 ;
     RECT  2.16 107.325 37.8 107.595 ;
     RECT  86.616 107.325 124.2 107.595 ;
     RECT  173.016 107.325 257.04 107.595 ;
     RECT  2.16 107.865 37.8 108.135 ;
     RECT  86.616 107.865 124.2 108.135 ;
     RECT  173.016 107.865 257.04 108.135 ;
     RECT  2.16 108.405 37.8 108.675 ;
     RECT  86.616 108.405 124.2 108.675 ;
     RECT  173.016 108.405 257.04 108.675 ;
     RECT  2.16 108.945 37.8 109.215 ;
     RECT  86.616 108.945 124.2 109.215 ;
     RECT  173.016 108.945 257.04 109.215 ;
     RECT  2.16 109.485 37.8 109.755 ;
     RECT  86.616 109.485 124.2 109.755 ;
     RECT  173.016 109.485 257.04 109.755 ;
     RECT  2.16 110.025 37.8 110.295 ;
     RECT  86.616 110.025 124.2 110.295 ;
     RECT  173.016 110.025 257.04 110.295 ;
     RECT  2.16 110.565 37.8 110.835 ;
     RECT  86.616 110.565 124.2 110.835 ;
     RECT  173.016 110.565 257.04 110.835 ;
     RECT  2.16 111.105 37.8 111.375 ;
     RECT  86.616 111.105 124.2 111.375 ;
     RECT  173.016 111.105 257.04 111.375 ;
     RECT  2.16 111.645 257.04 111.915 ;
     RECT  2.16 112.185 257.04 112.455 ;
     RECT  2.16 112.725 257.04 112.995 ;
     RECT  2.16 113.265 257.04 113.535 ;
     RECT  2.16 113.805 257.04 114.075 ;
     RECT  2.16 114.345 257.04 114.615 ;
     RECT  2.16 114.885 257.04 115.155 ;
     RECT  2.16 115.425 257.04 115.695 ;
     RECT  2.16 115.965 257.04 116.235 ;
     RECT  2.16 116.505 257.04 116.775 ;
     RECT  2.16 117.045 257.04 117.315 ;
     RECT  2.16 117.585 257.04 117.855 ;
     RECT  2.16 118.125 257.04 118.395 ;
     RECT  2.16 118.665 257.04 118.935 ;
     RECT  2.16 119.205 257.04 119.475 ;
     RECT  2.16 119.745 257.04 120.015 ;
     RECT  2.16 120.285 257.04 120.555 ;
     RECT  2.16 120.825 257.04 121.095 ;
     RECT  2.16 121.365 257.04 121.635 ;
     RECT  2.16 121.905 257.04 122.175 ;
     RECT  2.16 122.445 257.04 122.715 ;
     RECT  2.16 122.985 257.04 123.255 ;
     RECT  2.16 123.525 257.04 123.795 ;
     RECT  2.16 124.065 257.04 124.335 ;
     RECT  2.16 124.605 257.04 124.875 ;
     RECT  2.16 125.145 257.04 125.415 ;
     RECT  2.16 125.685 257.04 125.955 ;
     RECT  2.16 126.225 257.04 126.495 ;
     RECT  2.16 126.765 257.04 127.035 ;
     RECT  2.16 127.305 257.04 127.44 ;
    LAYER RVTP ;
     RECT  2.16 2.295 257.04 2.565 ;
     RECT  2.16 2.835 257.04 3.105 ;
     RECT  2.16 3.375 257.04 3.645 ;
     RECT  2.16 3.915 257.04 4.185 ;
     RECT  2.16 4.455 257.04 4.725 ;
     RECT  2.16 4.995 257.04 5.265 ;
     RECT  2.16 5.535 257.04 5.805 ;
     RECT  2.16 6.075 257.04 6.345 ;
     RECT  2.16 6.615 257.04 6.885 ;
     RECT  2.16 7.155 257.04 7.425 ;
     RECT  2.16 7.695 257.04 7.965 ;
     RECT  2.16 8.235 257.04 8.505 ;
     RECT  2.16 8.775 257.04 9.045 ;
     RECT  2.16 9.315 257.04 9.585 ;
     RECT  2.16 9.855 257.04 10.125 ;
     RECT  2.16 10.395 257.04 10.665 ;
     RECT  2.16 10.935 257.04 11.205 ;
     RECT  2.16 11.475 257.04 11.745 ;
     RECT  2.16 12.015 257.04 12.285 ;
     RECT  2.16 12.555 257.04 12.825 ;
     RECT  2.16 13.095 257.04 13.365 ;
     RECT  2.16 13.635 257.04 13.905 ;
     RECT  2.16 14.175 257.04 14.445 ;
     RECT  2.16 14.715 257.04 14.985 ;
     RECT  2.16 15.255 257.04 15.525 ;
     RECT  2.16 15.795 257.04 16.065 ;
     RECT  2.16 16.335 257.04 16.605 ;
     RECT  2.16 16.875 257.04 17.145 ;
     RECT  2.16 17.415 257.04 17.685 ;
     RECT  2.16 17.955 257.04 18.225 ;
     RECT  2.16 18.495 257.04 18.765 ;
     RECT  2.16 19.035 257.04 19.305 ;
     RECT  2.16 19.575 257.04 19.845 ;
     RECT  2.16 20.115 257.04 20.385 ;
     RECT  2.16 20.655 257.04 20.925 ;
     RECT  2.16 21.195 257.04 21.465 ;
     RECT  2.16 21.735 257.04 22.005 ;
     RECT  2.16 22.275 257.04 22.545 ;
     RECT  2.16 22.815 257.04 23.085 ;
     RECT  2.16 23.355 257.04 23.625 ;
     RECT  2.16 23.895 257.04 24.165 ;
     RECT  2.16 24.435 257.04 24.705 ;
     RECT  2.16 24.975 257.04 25.245 ;
     RECT  2.16 25.515 257.04 25.785 ;
     RECT  2.16 26.055 257.04 26.325 ;
     RECT  2.16 26.595 257.04 26.865 ;
     RECT  2.16 27.135 257.04 27.405 ;
     RECT  2.16 27.675 257.04 27.945 ;
     RECT  2.16 28.215 257.04 28.485 ;
     RECT  2.16 28.755 257.04 29.025 ;
     RECT  2.16 29.295 257.04 29.565 ;
     RECT  2.16 29.835 257.04 30.105 ;
     RECT  2.16 30.375 257.04 30.645 ;
     RECT  2.16 30.915 257.04 31.185 ;
     RECT  2.16 31.455 257.04 31.725 ;
     RECT  2.16 31.995 257.04 32.265 ;
     RECT  2.16 32.535 257.04 32.805 ;
     RECT  2.16 33.075 257.04 33.345 ;
     RECT  2.16 33.615 257.04 33.885 ;
     RECT  2.16 34.155 257.04 34.425 ;
     RECT  2.16 34.695 257.04 34.965 ;
     RECT  2.16 35.235 257.04 35.505 ;
     RECT  2.16 35.775 257.04 36.045 ;
     RECT  2.16 36.315 257.04 36.585 ;
     RECT  2.16 36.855 257.04 37.125 ;
     RECT  2.16 37.395 257.04 37.665 ;
     RECT  2.16 37.935 37.8 38.205 ;
     RECT  86.616 37.935 124.2 38.205 ;
     RECT  173.016 37.935 257.04 38.205 ;
     RECT  2.16 38.475 37.8 38.745 ;
     RECT  86.616 38.475 124.2 38.745 ;
     RECT  173.016 38.475 257.04 38.745 ;
     RECT  2.16 39.015 37.8 39.285 ;
     RECT  86.616 39.015 124.2 39.285 ;
     RECT  173.016 39.015 257.04 39.285 ;
     RECT  2.16 39.555 37.8 39.825 ;
     RECT  86.616 39.555 124.2 39.825 ;
     RECT  173.016 39.555 257.04 39.825 ;
     RECT  2.16 40.095 37.8 40.365 ;
     RECT  86.616 40.095 124.2 40.365 ;
     RECT  173.016 40.095 257.04 40.365 ;
     RECT  2.16 40.635 37.8 40.905 ;
     RECT  86.616 40.635 124.2 40.905 ;
     RECT  173.016 40.635 257.04 40.905 ;
     RECT  2.16 41.175 37.8 41.445 ;
     RECT  86.616 41.175 124.2 41.445 ;
     RECT  173.016 41.175 257.04 41.445 ;
     RECT  2.16 41.715 37.8 41.985 ;
     RECT  86.616 41.715 124.2 41.985 ;
     RECT  173.016 41.715 257.04 41.985 ;
     RECT  2.16 42.255 37.8 42.525 ;
     RECT  86.616 42.255 124.2 42.525 ;
     RECT  173.016 42.255 257.04 42.525 ;
     RECT  2.16 42.795 37.8 43.065 ;
     RECT  86.616 42.795 124.2 43.065 ;
     RECT  173.016 42.795 257.04 43.065 ;
     RECT  2.16 43.335 37.8 43.605 ;
     RECT  86.616 43.335 124.2 43.605 ;
     RECT  173.016 43.335 257.04 43.605 ;
     RECT  2.16 43.875 37.8 44.145 ;
     RECT  86.616 43.875 124.2 44.145 ;
     RECT  173.016 43.875 257.04 44.145 ;
     RECT  2.16 44.415 37.8 44.685 ;
     RECT  86.616 44.415 124.2 44.685 ;
     RECT  173.016 44.415 257.04 44.685 ;
     RECT  2.16 44.955 37.8 45.225 ;
     RECT  86.616 44.955 124.2 45.225 ;
     RECT  173.016 44.955 257.04 45.225 ;
     RECT  2.16 45.495 37.8 45.765 ;
     RECT  86.616 45.495 124.2 45.765 ;
     RECT  173.016 45.495 257.04 45.765 ;
     RECT  2.16 46.035 37.8 46.305 ;
     RECT  86.616 46.035 124.2 46.305 ;
     RECT  173.016 46.035 257.04 46.305 ;
     RECT  2.16 46.575 37.8 46.845 ;
     RECT  86.616 46.575 124.2 46.845 ;
     RECT  173.016 46.575 257.04 46.845 ;
     RECT  2.16 47.115 37.8 47.385 ;
     RECT  86.616 47.115 124.2 47.385 ;
     RECT  173.016 47.115 257.04 47.385 ;
     RECT  2.16 47.655 37.8 47.925 ;
     RECT  86.616 47.655 124.2 47.925 ;
     RECT  173.016 47.655 257.04 47.925 ;
     RECT  2.16 48.195 37.8 48.465 ;
     RECT  86.616 48.195 124.2 48.465 ;
     RECT  173.016 48.195 257.04 48.465 ;
     RECT  2.16 48.735 37.8 49.005 ;
     RECT  86.616 48.735 124.2 49.005 ;
     RECT  173.016 48.735 257.04 49.005 ;
     RECT  2.16 49.275 37.8 49.545 ;
     RECT  86.616 49.275 124.2 49.545 ;
     RECT  173.016 49.275 257.04 49.545 ;
     RECT  2.16 49.815 37.8 50.085 ;
     RECT  86.616 49.815 124.2 50.085 ;
     RECT  173.016 49.815 257.04 50.085 ;
     RECT  2.16 50.355 37.8 50.625 ;
     RECT  86.616 50.355 124.2 50.625 ;
     RECT  173.016 50.355 257.04 50.625 ;
     RECT  2.16 50.895 37.8 51.165 ;
     RECT  86.616 50.895 124.2 51.165 ;
     RECT  173.016 50.895 257.04 51.165 ;
     RECT  2.16 51.435 37.8 51.705 ;
     RECT  86.616 51.435 124.2 51.705 ;
     RECT  173.016 51.435 257.04 51.705 ;
     RECT  2.16 51.975 37.8 52.245 ;
     RECT  86.616 51.975 124.2 52.245 ;
     RECT  173.016 51.975 257.04 52.245 ;
     RECT  2.16 52.515 37.8 52.785 ;
     RECT  86.616 52.515 124.2 52.785 ;
     RECT  173.016 52.515 257.04 52.785 ;
     RECT  2.16 53.055 37.8 53.325 ;
     RECT  86.616 53.055 124.2 53.325 ;
     RECT  173.016 53.055 257.04 53.325 ;
     RECT  2.16 53.595 37.8 53.865 ;
     RECT  86.616 53.595 124.2 53.865 ;
     RECT  173.016 53.595 257.04 53.865 ;
     RECT  2.16 54.135 37.8 54.405 ;
     RECT  86.616 54.135 124.2 54.405 ;
     RECT  173.016 54.135 257.04 54.405 ;
     RECT  2.16 54.675 37.8 54.945 ;
     RECT  86.616 54.675 124.2 54.945 ;
     RECT  173.016 54.675 257.04 54.945 ;
     RECT  2.16 55.215 37.8 55.485 ;
     RECT  86.616 55.215 124.2 55.485 ;
     RECT  173.016 55.215 257.04 55.485 ;
     RECT  2.16 55.755 37.8 56.025 ;
     RECT  86.616 55.755 124.2 56.025 ;
     RECT  173.016 55.755 257.04 56.025 ;
     RECT  2.16 56.295 37.8 56.565 ;
     RECT  86.616 56.295 124.2 56.565 ;
     RECT  173.016 56.295 257.04 56.565 ;
     RECT  2.16 56.835 37.8 57.105 ;
     RECT  86.616 56.835 124.2 57.105 ;
     RECT  173.016 56.835 257.04 57.105 ;
     RECT  2.16 57.375 37.8 57.645 ;
     RECT  86.616 57.375 124.2 57.645 ;
     RECT  173.016 57.375 257.04 57.645 ;
     RECT  2.16 57.915 37.8 58.185 ;
     RECT  86.616 57.915 124.2 58.185 ;
     RECT  173.016 57.915 257.04 58.185 ;
     RECT  2.16 58.455 37.8 58.725 ;
     RECT  86.616 58.455 124.2 58.725 ;
     RECT  173.016 58.455 257.04 58.725 ;
     RECT  2.16 58.995 37.8 59.265 ;
     RECT  86.616 58.995 124.2 59.265 ;
     RECT  173.016 58.995 257.04 59.265 ;
     RECT  2.16 59.535 37.8 59.805 ;
     RECT  86.616 59.535 124.2 59.805 ;
     RECT  173.016 59.535 257.04 59.805 ;
     RECT  2.16 60.075 37.8 60.345 ;
     RECT  86.616 60.075 124.2 60.345 ;
     RECT  173.016 60.075 257.04 60.345 ;
     RECT  2.16 60.615 37.8 60.885 ;
     RECT  86.616 60.615 124.2 60.885 ;
     RECT  173.016 60.615 257.04 60.885 ;
     RECT  2.16 61.155 37.8 61.425 ;
     RECT  86.616 61.155 124.2 61.425 ;
     RECT  173.016 61.155 257.04 61.425 ;
     RECT  2.16 61.695 37.8 61.965 ;
     RECT  86.616 61.695 124.2 61.965 ;
     RECT  173.016 61.695 257.04 61.965 ;
     RECT  2.16 62.235 37.8 62.505 ;
     RECT  86.616 62.235 124.2 62.505 ;
     RECT  173.016 62.235 257.04 62.505 ;
     RECT  2.16 62.775 37.8 63.045 ;
     RECT  86.616 62.775 124.2 63.045 ;
     RECT  173.016 62.775 257.04 63.045 ;
     RECT  2.16 63.315 37.8 63.585 ;
     RECT  86.616 63.315 124.2 63.585 ;
     RECT  173.016 63.315 257.04 63.585 ;
     RECT  2.16 63.855 37.8 64.125 ;
     RECT  86.616 63.855 124.2 64.125 ;
     RECT  173.016 63.855 257.04 64.125 ;
     RECT  2.16 64.395 37.8 64.665 ;
     RECT  86.616 64.395 124.2 64.665 ;
     RECT  173.016 64.395 257.04 64.665 ;
     RECT  2.16 64.935 37.8 65.205 ;
     RECT  86.616 64.935 124.2 65.205 ;
     RECT  173.016 64.935 257.04 65.205 ;
     RECT  2.16 65.475 37.8 65.745 ;
     RECT  86.616 65.475 124.2 65.745 ;
     RECT  173.016 65.475 257.04 65.745 ;
     RECT  2.16 66.015 37.8 66.285 ;
     RECT  86.616 66.015 124.2 66.285 ;
     RECT  173.016 66.015 257.04 66.285 ;
     RECT  2.16 66.555 37.8 66.825 ;
     RECT  86.616 66.555 124.2 66.825 ;
     RECT  173.016 66.555 257.04 66.825 ;
     RECT  2.16 67.095 37.8 67.365 ;
     RECT  86.616 67.095 124.2 67.365 ;
     RECT  173.016 67.095 257.04 67.365 ;
     RECT  2.16 67.635 37.8 67.905 ;
     RECT  86.616 67.635 124.2 67.905 ;
     RECT  173.016 67.635 257.04 67.905 ;
     RECT  2.16 68.175 37.8 68.445 ;
     RECT  86.616 68.175 124.2 68.445 ;
     RECT  173.016 68.175 257.04 68.445 ;
     RECT  2.16 68.715 37.8 68.985 ;
     RECT  86.616 68.715 124.2 68.985 ;
     RECT  173.016 68.715 257.04 68.985 ;
     RECT  2.16 69.255 37.8 69.525 ;
     RECT  86.616 69.255 124.2 69.525 ;
     RECT  173.016 69.255 257.04 69.525 ;
     RECT  2.16 69.795 37.8 70.065 ;
     RECT  86.616 69.795 124.2 70.065 ;
     RECT  173.016 69.795 257.04 70.065 ;
     RECT  2.16 70.335 37.8 70.605 ;
     RECT  86.616 70.335 124.2 70.605 ;
     RECT  173.016 70.335 257.04 70.605 ;
     RECT  2.16 70.875 37.8 71.145 ;
     RECT  86.616 70.875 124.2 71.145 ;
     RECT  173.016 70.875 257.04 71.145 ;
     RECT  2.16 71.415 37.8 71.685 ;
     RECT  86.616 71.415 124.2 71.685 ;
     RECT  173.016 71.415 257.04 71.685 ;
     RECT  2.16 71.955 37.8 72.225 ;
     RECT  86.616 71.955 124.2 72.225 ;
     RECT  173.016 71.955 257.04 72.225 ;
     RECT  2.16 72.495 37.8 72.765 ;
     RECT  86.616 72.495 124.2 72.765 ;
     RECT  173.016 72.495 257.04 72.765 ;
     RECT  2.16 73.035 37.8 73.305 ;
     RECT  86.616 73.035 124.2 73.305 ;
     RECT  173.016 73.035 257.04 73.305 ;
     RECT  2.16 73.575 37.8 73.845 ;
     RECT  86.616 73.575 124.2 73.845 ;
     RECT  173.016 73.575 257.04 73.845 ;
     RECT  2.16 74.115 37.8 74.385 ;
     RECT  86.616 74.115 124.2 74.385 ;
     RECT  173.016 74.115 257.04 74.385 ;
     RECT  2.16 74.655 37.8 74.925 ;
     RECT  86.616 74.655 124.2 74.925 ;
     RECT  173.016 74.655 257.04 74.925 ;
     RECT  2.16 75.195 37.8 75.465 ;
     RECT  86.616 75.195 124.2 75.465 ;
     RECT  173.016 75.195 257.04 75.465 ;
     RECT  2.16 75.735 37.8 76.005 ;
     RECT  86.616 75.735 124.2 76.005 ;
     RECT  173.016 75.735 257.04 76.005 ;
     RECT  2.16 76.275 37.8 76.545 ;
     RECT  86.616 76.275 124.2 76.545 ;
     RECT  173.016 76.275 257.04 76.545 ;
     RECT  2.16 76.815 37.8 77.085 ;
     RECT  86.616 76.815 124.2 77.085 ;
     RECT  173.016 76.815 257.04 77.085 ;
     RECT  2.16 77.355 37.8 77.625 ;
     RECT  86.616 77.355 124.2 77.625 ;
     RECT  173.016 77.355 257.04 77.625 ;
     RECT  2.16 77.895 37.8 78.165 ;
     RECT  86.616 77.895 124.2 78.165 ;
     RECT  173.016 77.895 257.04 78.165 ;
     RECT  2.16 78.435 37.8 78.705 ;
     RECT  86.616 78.435 124.2 78.705 ;
     RECT  173.016 78.435 257.04 78.705 ;
     RECT  2.16 78.975 37.8 79.245 ;
     RECT  86.616 78.975 124.2 79.245 ;
     RECT  173.016 78.975 257.04 79.245 ;
     RECT  2.16 79.515 37.8 79.785 ;
     RECT  86.616 79.515 124.2 79.785 ;
     RECT  173.016 79.515 257.04 79.785 ;
     RECT  2.16 80.055 37.8 80.325 ;
     RECT  86.616 80.055 124.2 80.325 ;
     RECT  173.016 80.055 257.04 80.325 ;
     RECT  2.16 80.595 37.8 80.865 ;
     RECT  86.616 80.595 124.2 80.865 ;
     RECT  173.016 80.595 257.04 80.865 ;
     RECT  2.16 81.135 37.8 81.405 ;
     RECT  86.616 81.135 124.2 81.405 ;
     RECT  173.016 81.135 257.04 81.405 ;
     RECT  2.16 81.675 37.8 81.945 ;
     RECT  86.616 81.675 124.2 81.945 ;
     RECT  173.016 81.675 257.04 81.945 ;
     RECT  2.16 82.215 37.8 82.485 ;
     RECT  86.616 82.215 124.2 82.485 ;
     RECT  173.016 82.215 257.04 82.485 ;
     RECT  2.16 82.755 37.8 83.025 ;
     RECT  86.616 82.755 124.2 83.025 ;
     RECT  173.016 82.755 257.04 83.025 ;
     RECT  2.16 83.295 37.8 83.565 ;
     RECT  86.616 83.295 124.2 83.565 ;
     RECT  173.016 83.295 257.04 83.565 ;
     RECT  2.16 83.835 37.8 84.105 ;
     RECT  86.616 83.835 124.2 84.105 ;
     RECT  173.016 83.835 257.04 84.105 ;
     RECT  2.16 84.375 37.8 84.645 ;
     RECT  86.616 84.375 124.2 84.645 ;
     RECT  173.016 84.375 257.04 84.645 ;
     RECT  2.16 84.915 37.8 85.185 ;
     RECT  86.616 84.915 124.2 85.185 ;
     RECT  173.016 84.915 257.04 85.185 ;
     RECT  2.16 85.455 37.8 85.725 ;
     RECT  86.616 85.455 124.2 85.725 ;
     RECT  173.016 85.455 257.04 85.725 ;
     RECT  2.16 85.995 37.8 86.265 ;
     RECT  86.616 85.995 124.2 86.265 ;
     RECT  173.016 85.995 257.04 86.265 ;
     RECT  2.16 86.535 37.8 86.805 ;
     RECT  86.616 86.535 124.2 86.805 ;
     RECT  173.016 86.535 257.04 86.805 ;
     RECT  2.16 87.075 37.8 87.345 ;
     RECT  86.616 87.075 124.2 87.345 ;
     RECT  173.016 87.075 257.04 87.345 ;
     RECT  2.16 87.615 37.8 87.885 ;
     RECT  86.616 87.615 124.2 87.885 ;
     RECT  173.016 87.615 257.04 87.885 ;
     RECT  2.16 88.155 37.8 88.425 ;
     RECT  86.616 88.155 124.2 88.425 ;
     RECT  173.016 88.155 257.04 88.425 ;
     RECT  2.16 88.695 37.8 88.965 ;
     RECT  86.616 88.695 124.2 88.965 ;
     RECT  173.016 88.695 257.04 88.965 ;
     RECT  2.16 89.235 37.8 89.505 ;
     RECT  86.616 89.235 124.2 89.505 ;
     RECT  173.016 89.235 257.04 89.505 ;
     RECT  2.16 89.775 37.8 90.045 ;
     RECT  86.616 89.775 124.2 90.045 ;
     RECT  173.016 89.775 257.04 90.045 ;
     RECT  2.16 90.315 37.8 90.585 ;
     RECT  86.616 90.315 124.2 90.585 ;
     RECT  173.016 90.315 257.04 90.585 ;
     RECT  2.16 90.855 37.8 91.125 ;
     RECT  86.616 90.855 124.2 91.125 ;
     RECT  173.016 90.855 257.04 91.125 ;
     RECT  2.16 91.395 37.8 91.665 ;
     RECT  86.616 91.395 124.2 91.665 ;
     RECT  173.016 91.395 257.04 91.665 ;
     RECT  2.16 91.935 37.8 92.205 ;
     RECT  86.616 91.935 124.2 92.205 ;
     RECT  173.016 91.935 257.04 92.205 ;
     RECT  2.16 92.475 37.8 92.745 ;
     RECT  86.616 92.475 124.2 92.745 ;
     RECT  173.016 92.475 257.04 92.745 ;
     RECT  2.16 93.015 37.8 93.285 ;
     RECT  86.616 93.015 124.2 93.285 ;
     RECT  173.016 93.015 257.04 93.285 ;
     RECT  2.16 93.555 37.8 93.825 ;
     RECT  86.616 93.555 124.2 93.825 ;
     RECT  173.016 93.555 257.04 93.825 ;
     RECT  2.16 94.095 37.8 94.365 ;
     RECT  86.616 94.095 124.2 94.365 ;
     RECT  173.016 94.095 257.04 94.365 ;
     RECT  2.16 94.635 37.8 94.905 ;
     RECT  86.616 94.635 124.2 94.905 ;
     RECT  173.016 94.635 257.04 94.905 ;
     RECT  2.16 95.175 37.8 95.445 ;
     RECT  86.616 95.175 124.2 95.445 ;
     RECT  173.016 95.175 257.04 95.445 ;
     RECT  2.16 95.715 37.8 95.985 ;
     RECT  86.616 95.715 124.2 95.985 ;
     RECT  173.016 95.715 257.04 95.985 ;
     RECT  2.16 96.255 37.8 96.525 ;
     RECT  86.616 96.255 124.2 96.525 ;
     RECT  173.016 96.255 257.04 96.525 ;
     RECT  2.16 96.795 37.8 97.065 ;
     RECT  86.616 96.795 124.2 97.065 ;
     RECT  173.016 96.795 257.04 97.065 ;
     RECT  2.16 97.335 37.8 97.605 ;
     RECT  86.616 97.335 124.2 97.605 ;
     RECT  173.016 97.335 257.04 97.605 ;
     RECT  2.16 97.875 37.8 98.145 ;
     RECT  86.616 97.875 124.2 98.145 ;
     RECT  173.016 97.875 257.04 98.145 ;
     RECT  2.16 98.415 37.8 98.685 ;
     RECT  86.616 98.415 124.2 98.685 ;
     RECT  173.016 98.415 257.04 98.685 ;
     RECT  2.16 98.955 37.8 99.225 ;
     RECT  86.616 98.955 124.2 99.225 ;
     RECT  173.016 98.955 257.04 99.225 ;
     RECT  2.16 99.495 37.8 99.765 ;
     RECT  86.616 99.495 124.2 99.765 ;
     RECT  173.016 99.495 257.04 99.765 ;
     RECT  2.16 100.035 37.8 100.305 ;
     RECT  86.616 100.035 124.2 100.305 ;
     RECT  173.016 100.035 257.04 100.305 ;
     RECT  2.16 100.575 37.8 100.845 ;
     RECT  86.616 100.575 124.2 100.845 ;
     RECT  173.016 100.575 257.04 100.845 ;
     RECT  2.16 101.115 37.8 101.385 ;
     RECT  86.616 101.115 124.2 101.385 ;
     RECT  173.016 101.115 257.04 101.385 ;
     RECT  2.16 101.655 37.8 101.925 ;
     RECT  86.616 101.655 124.2 101.925 ;
     RECT  173.016 101.655 257.04 101.925 ;
     RECT  2.16 102.195 37.8 102.465 ;
     RECT  86.616 102.195 124.2 102.465 ;
     RECT  173.016 102.195 257.04 102.465 ;
     RECT  2.16 102.735 37.8 103.005 ;
     RECT  86.616 102.735 124.2 103.005 ;
     RECT  173.016 102.735 257.04 103.005 ;
     RECT  2.16 103.275 37.8 103.545 ;
     RECT  86.616 103.275 124.2 103.545 ;
     RECT  173.016 103.275 257.04 103.545 ;
     RECT  2.16 103.815 37.8 104.085 ;
     RECT  86.616 103.815 124.2 104.085 ;
     RECT  173.016 103.815 257.04 104.085 ;
     RECT  2.16 104.355 37.8 104.625 ;
     RECT  86.616 104.355 124.2 104.625 ;
     RECT  173.016 104.355 257.04 104.625 ;
     RECT  2.16 104.895 37.8 105.165 ;
     RECT  86.616 104.895 124.2 105.165 ;
     RECT  173.016 104.895 257.04 105.165 ;
     RECT  2.16 105.435 37.8 105.705 ;
     RECT  86.616 105.435 124.2 105.705 ;
     RECT  173.016 105.435 257.04 105.705 ;
     RECT  2.16 105.975 37.8 106.245 ;
     RECT  86.616 105.975 124.2 106.245 ;
     RECT  173.016 105.975 257.04 106.245 ;
     RECT  2.16 106.515 37.8 106.785 ;
     RECT  86.616 106.515 124.2 106.785 ;
     RECT  173.016 106.515 257.04 106.785 ;
     RECT  2.16 107.055 37.8 107.325 ;
     RECT  86.616 107.055 124.2 107.325 ;
     RECT  173.016 107.055 257.04 107.325 ;
     RECT  2.16 107.595 37.8 107.865 ;
     RECT  86.616 107.595 124.2 107.865 ;
     RECT  173.016 107.595 257.04 107.865 ;
     RECT  2.16 108.135 37.8 108.405 ;
     RECT  86.616 108.135 124.2 108.405 ;
     RECT  173.016 108.135 257.04 108.405 ;
     RECT  2.16 108.675 37.8 108.945 ;
     RECT  86.616 108.675 124.2 108.945 ;
     RECT  173.016 108.675 257.04 108.945 ;
     RECT  2.16 109.215 37.8 109.485 ;
     RECT  86.616 109.215 124.2 109.485 ;
     RECT  173.016 109.215 257.04 109.485 ;
     RECT  2.16 109.755 37.8 110.025 ;
     RECT  86.616 109.755 124.2 110.025 ;
     RECT  173.016 109.755 257.04 110.025 ;
     RECT  2.16 110.295 37.8 110.565 ;
     RECT  86.616 110.295 124.2 110.565 ;
     RECT  173.016 110.295 257.04 110.565 ;
     RECT  2.16 110.835 37.8 111.105 ;
     RECT  86.616 110.835 124.2 111.105 ;
     RECT  173.016 110.835 257.04 111.105 ;
     RECT  2.16 111.375 37.8 111.51 ;
     RECT  86.616 111.375 124.2 111.51 ;
     RECT  173.016 111.375 257.04 111.51 ;
     RECT  2.16 111.51 257.04 111.645 ;
     RECT  2.16 111.915 257.04 112.185 ;
     RECT  2.16 112.455 257.04 112.725 ;
     RECT  2.16 112.995 257.04 113.265 ;
     RECT  2.16 113.535 257.04 113.805 ;
     RECT  2.16 114.075 257.04 114.345 ;
     RECT  2.16 114.615 257.04 114.885 ;
     RECT  2.16 115.155 257.04 115.425 ;
     RECT  2.16 115.695 257.04 115.965 ;
     RECT  2.16 116.235 257.04 116.505 ;
     RECT  2.16 116.775 257.04 117.045 ;
     RECT  2.16 117.315 257.04 117.585 ;
     RECT  2.16 117.855 257.04 118.125 ;
     RECT  2.16 118.395 257.04 118.665 ;
     RECT  2.16 118.935 257.04 119.205 ;
     RECT  2.16 119.475 257.04 119.745 ;
     RECT  2.16 120.015 257.04 120.285 ;
     RECT  2.16 120.555 257.04 120.825 ;
     RECT  2.16 121.095 257.04 121.365 ;
     RECT  2.16 121.635 257.04 121.905 ;
     RECT  2.16 122.175 257.04 122.445 ;
     RECT  2.16 122.715 257.04 122.985 ;
     RECT  2.16 123.255 257.04 123.525 ;
     RECT  2.16 123.795 257.04 124.065 ;
     RECT  2.16 124.335 257.04 124.605 ;
     RECT  2.16 124.875 257.04 125.145 ;
     RECT  2.16 125.415 257.04 125.685 ;
     RECT  2.16 125.955 257.04 126.225 ;
     RECT  2.16 126.495 257.04 126.765 ;
     RECT  2.16 127.035 257.04 127.305 ;
    LAYER M1 ;
     RECT  2.16 2.151 257.04 37.809 ;
     RECT  43.2 43.2 81.216 106.11 ;
     RECT  129.6 43.2 167.616 106.11 ;
     RECT  2.16 37.809 37.8 111.501 ;
     RECT  86.616 37.809 124.2 111.501 ;
     RECT  173.016 37.809 257.04 111.501 ;
     RECT  2.16 111.501 257.04 127.449 ;
    LAYER M2 ;
     RECT  1.075 31.536 1.111 31.554 ;
     RECT  1.147 38.646 1.183 38.664 ;
     RECT  1.147 28.566 1.219 28.584 ;
     RECT  1.183 29.376 1.219 29.394 ;
     RECT  1.111 31.536 1.975 31.644 ;
     RECT  1.219 28.566 2.16 29.394 ;
     RECT  1.363 30.186 2.16 30.204 ;
     RECT  1.975 31.194 2.16 31.644 ;
     RECT  0.103 33.426 2.16 33.444 ;
     RECT  1.183 38.556 2.16 38.664 ;
     RECT  0.571 39.456 2.16 39.474 ;
     RECT  0.823 40.266 2.16 40.284 ;
     RECT  2.16 2.151 37.812 127.449 ;
     RECT  37.812 43.848 38.795 48.294 ;
     RECT  38.795 43.848 39.371 48.15 ;
     RECT  39.371 44.316 41.639 48.15 ;
     RECT  41.639 44.316 41.711 45.252 ;
     RECT  41.711 44.316 41.747 44.91 ;
     RECT  41.639 46.278 42.179 48.15 ;
     RECT  37.812 2.151 42.655 42.48 ;
     RECT  42.655 2.151 42.727 42.516 ;
     RECT  42.727 2.151 42.979 42.75 ;
     RECT  41.747 44.316 43.015 44.334 ;
     RECT  42.979 2.151 43.2 42.786 ;
     RECT  43.015 44.046 43.2 44.334 ;
     RECT  42.179 46.314 43.2 46.332 ;
     RECT  42.179 47.592 43.2 48.15 ;
     RECT  43.2 2.151 45.995 106.11 ;
     RECT  45.995 40.716 48.119 106.11 ;
     RECT  48.119 41.886 48.767 106.11 ;
     RECT  48.119 40.716 49.307 40.779 ;
     RECT  48.767 42.462 50.171 106.11 ;
     RECT  49.307 40.716 50.207 40.734 ;
     RECT  50.171 43.2 81.216 106.11 ;
     RECT  81.216 44.046 81.347 44.064 ;
     RECT  45.995 2.151 86.616 39.582 ;
     RECT  53.203 40.716 86.616 40.734 ;
     RECT  37.812 111.501 86.616 127.449 ;
     RECT  86.616 2.151 124.212 127.449 ;
     RECT  124.212 43.956 124.295 48.294 ;
     RECT  124.295 44.082 128.291 48.294 ;
     RECT  128.291 45.306 128.867 48.294 ;
     RECT  128.291 44.082 129.6 44.1 ;
     RECT  128.867 45.468 129.6 46.944 ;
     RECT  128.867 48.276 129.6 48.294 ;
     RECT  124.212 41.49 129.911 42.318 ;
     RECT  124.212 2.151 143.239 40.122 ;
     RECT  129.911 41.688 166.351 42.318 ;
     RECT  129.6 43.2 166.351 106.11 ;
     RECT  166.351 41.688 167.616 106.11 ;
     RECT  167.616 41.688 167.675 42.48 ;
     RECT  167.675 41.688 167.855 42.318 ;
     RECT  167.616 43.956 170.383 43.974 ;
     RECT  170.383 43.92 172.687 43.974 ;
     RECT  143.239 2.151 173.016 40.734 ;
     RECT  167.855 42.3 173.016 42.318 ;
     RECT  172.687 43.686 173.016 43.974 ;
     RECT  124.212 111.501 173.016 127.449 ;
     RECT  173.016 2.151 257.04 127.449 ;
     RECT  257.04 36.756 257.063 36.774 ;
     RECT  257.04 34.128 257.639 35.766 ;
     RECT  257.04 37.566 257.639 43.866 ;
     RECT  257.639 34.47 257.675 35.766 ;
     RECT  257.639 38.016 257.675 43.866 ;
     RECT  257.675 38.016 258.143 40.122 ;
     RECT  258.143 38.016 258.179 39.276 ;
     RECT  257.675 41.148 258.179 41.166 ;
     RECT  257.675 41.958 258.179 43.866 ;
     RECT  258.179 38.016 258.215 39.042 ;
     RECT  258.179 42.03 258.215 43.866 ;
     RECT  258.215 38.016 258.251 38.034 ;
     RECT  258.215 43.65 258.251 43.866 ;
     RECT  257.675 34.938 259.043 35.766 ;
     RECT  259.043 35.55 259.079 35.766 ;
     RECT  259.079 35.748 259.115 35.766 ;
     RECT  258.143 40.104 259.115 40.122 ;
     RECT  258.215 42.03 259.115 42.75 ;
     RECT  258.251 43.848 259.115 43.866 ;
    LAYER M3 ;
     RECT  89.028 0.091 89.046 1.723 ;
     RECT  89.028 1.723 89.802 1.771 ;
     RECT  89.028 1.771 90.018 2.143 ;
     RECT  88.815 2.143 90.018 2.263 ;
     RECT  88.815 2.263 90.27 2.371 ;
     RECT  91.515 2.143 91.605 2.371 ;
     RECT  2.415 2.143 2.505 2.413 ;
     RECT  5.115 2.143 5.205 2.413 ;
     RECT  7.815 2.143 7.905 2.413 ;
     RECT  10.515 2.143 10.605 2.413 ;
     RECT  13.215 2.143 13.305 2.413 ;
     RECT  15.915 2.143 16.005 2.413 ;
     RECT  18.615 2.143 18.705 2.413 ;
     RECT  21.315 2.143 21.405 2.413 ;
     RECT  24.015 2.143 24.105 2.413 ;
     RECT  26.715 2.143 26.805 2.413 ;
     RECT  29.415 2.143 29.505 2.413 ;
     RECT  32.115 2.143 32.205 2.413 ;
     RECT  34.815 2.143 34.905 2.413 ;
     RECT  37.515 2.143 37.605 2.413 ;
     RECT  40.215 2.143 40.305 2.413 ;
     RECT  42.915 2.143 43.005 2.413 ;
     RECT  45.615 2.143 45.705 2.413 ;
     RECT  48.315 2.143 48.405 2.413 ;
     RECT  51.015 2.143 51.105 2.413 ;
     RECT  53.715 2.143 53.805 2.413 ;
     RECT  56.415 2.143 56.505 2.413 ;
     RECT  59.115 2.143 59.205 2.413 ;
     RECT  61.815 2.143 61.905 2.413 ;
     RECT  64.515 2.143 64.605 2.413 ;
     RECT  67.215 2.143 67.305 2.413 ;
     RECT  69.915 2.143 70.005 2.413 ;
     RECT  72.615 2.143 72.705 2.413 ;
     RECT  75.315 2.143 75.405 2.413 ;
     RECT  78.015 2.143 78.105 2.413 ;
     RECT  80.715 2.143 80.805 2.413 ;
     RECT  83.415 2.143 83.505 2.413 ;
     RECT  86.115 2.143 86.205 2.413 ;
     RECT  88.815 2.371 91.674 2.413 ;
     RECT  92.484 2.371 92.502 2.413 ;
     RECT  94.215 2.143 94.305 2.413 ;
     RECT  96.915 2.143 97.005 2.413 ;
     RECT  99.615 2.143 99.705 2.413 ;
     RECT  102.315 2.143 102.405 2.413 ;
     RECT  105.015 2.143 105.105 2.413 ;
     RECT  107.715 2.143 107.805 2.413 ;
     RECT  110.415 2.143 110.505 2.413 ;
     RECT  113.115 2.143 113.205 2.413 ;
     RECT  115.815 2.143 115.905 2.413 ;
     RECT  118.515 2.143 118.605 2.413 ;
     RECT  121.215 2.143 121.305 2.413 ;
     RECT  123.915 2.143 124.005 2.413 ;
     RECT  126.615 2.143 126.705 2.413 ;
     RECT  129.315 2.143 129.405 2.413 ;
     RECT  132.015 2.143 132.105 2.413 ;
     RECT  134.715 2.143 134.805 2.413 ;
     RECT  137.415 2.143 137.505 2.413 ;
     RECT  140.115 2.143 140.205 2.413 ;
     RECT  142.815 2.143 142.905 2.413 ;
     RECT  145.515 2.143 145.605 2.413 ;
     RECT  148.215 2.143 148.305 2.413 ;
     RECT  150.915 2.143 151.005 2.413 ;
     RECT  153.615 2.143 153.705 2.413 ;
     RECT  156.315 2.143 156.405 2.413 ;
     RECT  159.015 2.143 159.105 2.413 ;
     RECT  161.715 2.143 161.805 2.413 ;
     RECT  164.415 2.143 164.505 2.413 ;
     RECT  167.115 2.143 167.205 2.413 ;
     RECT  169.815 2.143 169.905 2.413 ;
     RECT  172.515 2.143 172.605 2.413 ;
     RECT  175.215 2.143 175.305 2.413 ;
     RECT  177.915 2.143 178.005 2.413 ;
     RECT  180.615 2.143 180.705 2.413 ;
     RECT  183.315 2.143 183.405 2.413 ;
     RECT  186.015 2.143 186.105 2.413 ;
     RECT  188.715 2.143 188.805 2.413 ;
     RECT  191.415 2.143 191.505 2.413 ;
     RECT  194.115 2.143 194.205 2.413 ;
     RECT  196.815 2.143 196.905 2.413 ;
     RECT  199.515 2.143 199.605 2.413 ;
     RECT  202.215 2.143 202.305 2.413 ;
     RECT  204.915 2.143 205.005 2.413 ;
     RECT  207.615 2.143 207.705 2.413 ;
     RECT  210.315 2.143 210.405 2.413 ;
     RECT  213.015 2.143 213.105 2.413 ;
     RECT  215.715 2.143 215.805 2.413 ;
     RECT  218.415 2.143 218.505 2.413 ;
     RECT  221.115 2.143 221.205 2.413 ;
     RECT  223.815 2.143 223.905 2.413 ;
     RECT  226.515 2.143 226.605 2.413 ;
     RECT  229.215 2.143 229.305 2.413 ;
     RECT  231.915 2.143 232.005 2.413 ;
     RECT  234.615 2.143 234.705 2.413 ;
     RECT  237.315 2.143 237.405 2.413 ;
     RECT  240.015 2.143 240.105 2.413 ;
     RECT  242.715 2.143 242.805 2.413 ;
     RECT  245.415 2.143 245.505 2.413 ;
     RECT  248.115 2.143 248.205 2.413 ;
     RECT  250.815 2.143 250.905 2.413 ;
     RECT  253.515 2.143 253.605 2.413 ;
     RECT  256.215 2.143 256.305 2.413 ;
     RECT  88.815 2.413 92.502 2.497 ;
     RECT  88.092 2.497 92.502 2.525 ;
     RECT  88.092 2.525 91.797 2.533 ;
     RECT  87.12 2.569 87.138 2.621 ;
     RECT  87.912 2.533 91.797 2.641 ;
     RECT  92.736 2.533 92.754 2.641 ;
     RECT  87.3 2.641 91.797 2.759 ;
     RECT  87.804 2.759 91.797 2.867 ;
     RECT  92.736 2.641 93.078 3.137 ;
     RECT  88.092 2.867 91.797 3.437 ;
     RECT  88.344 3.437 91.797 3.569 ;
     RECT  88.416 3.569 91.797 3.991 ;
     RECT  88.416 3.991 91.926 4.109 ;
     RECT  90.252 4.109 91.926 4.379 ;
     RECT  95.94 3.109 95.958 14.827 ;
     RECT  96.915 2.413 97.197 14.827 ;
     RECT  95.94 14.827 97.197 14.957 ;
     RECT  72.615 2.413 72.897 16.843 ;
     RECT  90.252 4.379 91.797 16.871 ;
     RECT  90.252 16.871 90.27 17.608 ;
     RECT  91.152 16.871 91.797 17.609 ;
     RECT  90.252 17.608 90.378 17.645 ;
     RECT  84.888 20.011 84.906 20.093 ;
     RECT  84.6 20.107 84.618 20.219 ;
     RECT  51.015 2.413 51.297 22.513 ;
     RECT  113.115 2.413 113.397 22.513 ;
     RECT  88.416 4.109 89.406 22.541 ;
     RECT  90.252 17.645 90.27 22.541 ;
     RECT  2.415 2.413 2.697 24.745 ;
     RECT  2.415 24.745 3.078 24.781 ;
     RECT  82.368 24.859 82.386 24.899 ;
     RECT  61.815 2.413 62.097 24.907 ;
     RECT  82.044 24.907 82.062 24.944 ;
     RECT  2.415 24.781 3.15 25.015 ;
     RECT  61.56 24.907 62.097 25.015 ;
     RECT  61.524 25.015 62.097 25.141 ;
     RECT  62.892 4.261 62.91 25.141 ;
     RECT  61.524 25.141 62.91 25.177 ;
     RECT  60.444 25.249 60.462 25.321 ;
     RECT  61.2 25.177 63.378 25.321 ;
     RECT  64.515 2.413 64.797 25.321 ;
     RECT  2.304 25.015 3.15 25.411 ;
     RECT  2.304 25.411 3.402 25.591 ;
     RECT  60.444 25.321 64.797 25.591 ;
     RECT  60.444 25.591 64.854 25.753 ;
     RECT  2.304 25.591 3.69 25.825 ;
     RECT  2.304 25.825 3.978 25.861 ;
     RECT  60.444 25.753 65.034 25.861 ;
     RECT  7.815 2.413 8.097 25.987 ;
     RECT  60.444 25.861 65.25 26.131 ;
     RECT  5.115 2.413 5.397 26.257 ;
     RECT  59.115 2.413 59.397 26.257 ;
     RECT  60.444 26.131 65.322 26.257 ;
     RECT  5.115 26.257 5.526 26.293 ;
     RECT  59.115 26.257 59.67 26.293 ;
     RECT  60.408 26.257 65.646 26.293 ;
     RECT  59.115 26.293 65.646 26.329 ;
     RECT  5.115 26.293 5.742 26.347 ;
     RECT  5.076 26.347 5.742 26.401 ;
     RECT  7.452 25.987 8.097 26.491 ;
     RECT  5.004 26.401 5.742 26.563 ;
     RECT  6.48 26.491 8.097 26.563 ;
     RECT  5.004 26.563 8.097 26.587 ;
     RECT  59.115 26.329 65.862 26.587 ;
     RECT  2.304 25.861 4.086 26.635 ;
     RECT  4.968 26.587 8.097 26.635 ;
     RECT  59.076 26.587 65.862 26.635 ;
     RECT  2.304 26.635 8.097 26.671 ;
     RECT  72.615 16.843 73.242 26.789 ;
     RECT  10.515 2.413 10.797 26.905 ;
     RECT  32.115 2.413 32.397 26.905 ;
     RECT  2.304 26.671 9.054 26.941 ;
     RECT  72.615 26.789 72.897 26.941 ;
     RECT  2.304 26.941 9.378 27.031 ;
     RECT  10.368 26.905 10.797 27.031 ;
     RECT  32.115 26.905 32.814 27.139 ;
     RECT  58.464 26.635 65.862 27.139 ;
     RECT  58.464 27.139 66.186 27.175 ;
     RECT  32.004 27.139 32.814 27.211 ;
     RECT  33.588 26.941 33.606 27.211 ;
     RECT  0.144 26.299 0.162 27.245 ;
     RECT  32.004 27.211 33.606 27.301 ;
     RECT  58.464 27.175 66.294 27.365 ;
     RECT  29.415 2.413 29.697 27.373 ;
     RECT  12.456 27.301 12.474 27.481 ;
     RECT  88.416 22.541 89.097 27.481 ;
     RECT  31.896 27.301 33.606 27.571 ;
     RECT  31.896 27.571 33.642 27.643 ;
     RECT  34.815 2.413 35.097 27.643 ;
     RECT  58.644 27.365 66.294 27.643 ;
     RECT  27.828 27.679 27.846 27.715 ;
     RECT  29.088 27.373 29.697 27.715 ;
     RECT  31.896 27.643 33.822 27.715 ;
     RECT  34.74 27.643 35.097 27.715 ;
     RECT  74.124 27.679 74.142 27.715 ;
     RECT  30.672 27.481 30.69 27.751 ;
     RECT  31.896 27.715 35.097 27.751 ;
     RECT  72.396 26.941 72.897 27.751 ;
     RECT  74.124 27.715 74.322 27.751 ;
     RECT  75.315 2.413 75.597 27.751 ;
     RECT  1.152 27.499 1.17 27.787 ;
     RECT  2.304 27.031 10.797 27.841 ;
     RECT  12.024 27.481 12.474 27.841 ;
     RECT  50.94 22.513 51.297 27.913 ;
     RECT  72.396 27.751 75.597 27.913 ;
     RECT  27.72 27.715 29.697 27.917 ;
     RECT  27.828 27.917 29.697 27.941 ;
     RECT  56.415 2.413 56.697 27.949 ;
     RECT  2.304 27.841 12.474 28.021 ;
     RECT  13.215 2.413 13.497 28.021 ;
     RECT  54.72 27.481 54.738 28.021 ;
     RECT  72.216 27.913 75.597 28.021 ;
     RECT  54.72 28.021 55.278 28.049 ;
     RECT  58.644 27.643 66.402 28.111 ;
     RECT  44.352 28.111 44.37 28.147 ;
     RECT  28.584 27.941 29.697 28.183 ;
     RECT  30.672 27.751 35.097 28.183 ;
     RECT  28.584 28.183 35.097 28.219 ;
     RECT  42.915 2.413 43.197 28.219 ;
     RECT  44.208 28.147 44.37 28.219 ;
     RECT  48.315 2.413 48.597 28.219 ;
     RECT  54.936 28.049 55.278 28.219 ;
     RECT  56.016 27.949 56.697 28.219 ;
     RECT  37.515 2.413 37.797 28.255 ;
     RECT  57.78 28.219 57.798 28.255 ;
     RECT  58.644 28.111 66.438 28.255 ;
     RECT  54.936 28.219 56.697 28.267 ;
     RECT  46.836 28.255 46.854 28.291 ;
     RECT  57.78 28.255 66.438 28.291 ;
     RECT  67.215 2.413 67.497 28.291 ;
     RECT  71.316 28.255 71.334 28.291 ;
     RECT  45.615 2.413 45.897 28.381 ;
     RECT  48.276 28.219 48.597 28.381 ;
     RECT  45.144 28.381 45.897 28.417 ;
     RECT  46.836 28.291 47.502 28.417 ;
     RECT  48.276 28.381 48.834 28.417 ;
     RECT  57.636 28.291 67.497 28.417 ;
     RECT  69.12 28.381 69.138 28.417 ;
     RECT  42.915 28.219 44.37 28.453 ;
     RECT  45.144 28.417 48.834 28.453 ;
     RECT  50.94 27.913 51.894 28.453 ;
     RECT  54.936 28.267 56.862 28.453 ;
     RECT  57.636 28.417 69.138 28.453 ;
     RECT  69.915 2.413 70.197 28.453 ;
     RECT  71.316 28.291 71.478 28.453 ;
     RECT  72.216 28.021 75.87 28.453 ;
     RECT  2.304 28.021 13.497 28.481 ;
     RECT  40.215 2.413 40.497 28.489 ;
     RECT  42.876 28.453 48.834 28.489 ;
     RECT  50.94 28.453 52.506 28.489 ;
     RECT  0.144 28.363 0.162 28.493 ;
     RECT  40.215 28.489 40.662 28.507 ;
     RECT  37.515 28.255 37.998 28.525 ;
     RECT  42.444 28.489 48.834 28.525 ;
     RECT  50.652 28.489 52.506 28.525 ;
     RECT  37.515 28.525 38.25 28.561 ;
     RECT  121.215 2.413 121.497 28.561 ;
     RECT  1.152 27.787 1.386 28.589 ;
     RECT  40.215 28.507 41.238 28.651 ;
     RECT  42.3 28.525 48.834 28.651 ;
     RECT  54.936 28.453 70.47 28.651 ;
     RECT  71.316 28.453 75.87 28.651 ;
     RECT  21.315 2.413 21.597 28.687 ;
     RECT  26.715 2.413 26.997 28.687 ;
     RECT  27.828 27.941 27.846 28.687 ;
     RECT  88.416 27.481 89.514 28.715 ;
     RECT  40.215 28.651 48.834 28.759 ;
     RECT  50.256 28.525 52.506 28.759 ;
     RECT  54.936 28.651 75.87 28.787 ;
     RECT  88.815 28.715 89.514 28.787 ;
     RECT  26.715 28.687 27.846 28.795 ;
     RECT  28.584 28.219 35.226 28.795 ;
     RECT  40.14 28.759 48.834 28.795 ;
     RECT  49.608 28.759 52.506 28.795 ;
     RECT  37.515 28.561 38.97 28.831 ;
     RECT  75.315 28.787 75.87 28.957 ;
     RECT  75.315 28.957 76.302 28.993 ;
     RECT  37.44 28.831 38.97 29.029 ;
     RECT  36.792 29.029 38.97 29.035 ;
     RECT  2.34 28.481 13.497 29.057 ;
     RECT  75.315 28.993 76.41 29.101 ;
     RECT  120.996 28.561 121.497 29.101 ;
     RECT  21.315 28.687 22.266 29.218 ;
     RECT  2.34 29.057 11.106 29.219 ;
     RECT  14.292 28.489 14.31 29.263 ;
     RECT  26.316 28.795 35.226 29.263 ;
     RECT  36.684 29.035 39.186 29.323 ;
     RECT  40.14 28.795 52.506 29.323 ;
     RECT  75.315 29.101 76.842 29.327 ;
     RECT  18.615 2.413 18.897 29.335 ;
     RECT  118.515 2.413 118.797 29.335 ;
     RECT  54.936 28.787 74.538 29.363 ;
     RECT  1.188 28.589 1.386 29.399 ;
     RECT  54.936 29.363 66.438 29.461 ;
     RECT  2.34 29.219 3.618 29.489 ;
     RECT  4.536 29.219 11.106 29.489 ;
     RECT  18.615 29.335 19.35 29.489 ;
     RECT  67.212 29.363 74.538 29.489 ;
     RECT  118.404 29.335 118.797 29.489 ;
     RECT  26.316 29.263 35.694 29.497 ;
     RECT  53.715 2.413 53.997 29.497 ;
     RECT  72.108 29.489 74.538 29.525 ;
     RECT  75.315 29.327 76.698 29.525 ;
     RECT  14.292 29.263 14.418 29.533 ;
     RECT  26.316 29.497 35.91 29.533 ;
     RECT  36.684 29.323 52.506 29.533 ;
     RECT  53.46 29.497 53.997 29.533 ;
     RECT  75.315 29.525 76.446 29.533 ;
     RECT  9.864 29.489 11.106 29.549 ;
     RECT  11.844 29.057 13.497 29.569 ;
     RECT  14.292 29.533 14.886 29.569 ;
     RECT  67.212 29.489 71.226 29.597 ;
     RECT  120.564 29.101 121.497 29.605 ;
     RECT  248.115 2.413 248.397 29.605 ;
     RECT  11.844 29.569 14.886 29.633 ;
     RECT  24.015 2.413 24.297 29.641 ;
     RECT  25.38 29.371 25.398 29.641 ;
     RECT  120.456 29.605 121.497 29.641 ;
     RECT  17.028 29.533 17.046 29.669 ;
     RECT  67.212 29.597 71.19 29.759 ;
     RECT  72.108 29.525 73.818 29.759 ;
     RECT  156.315 2.413 156.597 29.767 ;
     RECT  2.34 29.489 3.546 29.839 ;
     RECT  122.544 29.767 122.562 29.867 ;
     RECT  24.015 29.641 25.398 29.875 ;
     RECT  24.015 29.875 25.47 29.911 ;
     RECT  26.316 29.533 53.997 29.911 ;
     RECT  21.315 29.218 22.302 29.939 ;
     RECT  120.456 29.641 121.626 29.939 ;
     RECT  24.015 29.911 53.997 30.029 ;
     RECT  24.015 30.029 36.306 30.037 ;
     RECT  2.304 29.839 3.546 30.065 ;
     RECT  1.368 29.399 1.386 30.209 ;
     RECT  72.18 29.759 73.818 30.209 ;
     RECT  119.592 29.755 119.61 30.299 ;
     RECT  120.996 29.939 121.626 30.299 ;
     RECT  4.536 29.489 9.018 30.407 ;
     RECT  23.976 30.037 36.306 30.415 ;
     RECT  54.72 29.461 66.438 30.415 ;
     RECT  67.212 29.759 71.082 30.415 ;
     RECT  118.515 29.489 118.797 30.415 ;
     RECT  7.128 30.407 9.018 30.479 ;
     RECT  91.188 17.609 91.797 30.479 ;
     RECT  4.536 30.407 6.282 30.523 ;
     RECT  54.72 30.415 71.082 30.568 ;
     RECT  4.428 30.523 6.282 30.569 ;
     RECT  72.18 30.209 73.782 30.569 ;
     RECT  54.72 30.568 71.19 30.605 ;
     RECT  7.2 30.479 9.018 30.611 ;
     RECT  37.044 30.029 53.997 30.613 ;
     RECT  54.72 30.605 66.474 30.613 ;
     RECT  7.308 30.611 9.018 30.641 ;
     RECT  67.215 30.605 71.19 30.685 ;
     RECT  72.18 30.569 73.71 30.685 ;
     RECT  74.772 29.533 76.446 30.721 ;
     RECT  67.215 30.685 73.71 30.749 ;
     RECT  23.904 30.415 36.306 30.811 ;
     RECT  37.044 30.613 66.474 30.811 ;
     RECT  4.572 30.569 6.282 30.839 ;
     RECT  112.608 22.513 113.397 30.839 ;
     RECT  18.615 29.489 18.954 30.883 ;
     RECT  7.38 30.641 9.018 30.947 ;
     RECT  21.315 29.939 21.597 30.955 ;
     RECT  7.38 30.947 8.154 30.983 ;
     RECT  23.904 30.811 66.474 30.983 ;
     RECT  2.415 30.065 3.546 30.991 ;
     RECT  74.664 30.721 76.446 30.991 ;
     RECT  11.844 29.633 14.418 31.109 ;
     RECT  11.952 31.109 14.418 31.147 ;
     RECT  2.304 30.991 3.546 31.189 ;
     RECT  138.564 28.759 138.582 31.189 ;
     RECT  115.815 2.413 116.097 31.195 ;
     RECT  11.952 31.147 14.85 31.277 ;
     RECT  21.096 30.955 21.597 31.289 ;
     RECT  23.904 30.983 25.902 31.289 ;
     RECT  9 30.947 9.018 31.339 ;
     RECT  68.436 30.749 73.71 31.351 ;
     RECT  74.52 30.991 76.446 31.351 ;
     RECT  138.528 31.189 138.582 31.387 ;
     RECT  23.904 31.289 25.83 31.415 ;
     RECT  26.715 30.983 66.474 31.495 ;
     RECT  67.215 30.749 67.497 31.495 ;
     RECT  1.98 31.189 3.834 31.531 ;
     RECT  26.715 31.495 67.497 31.531 ;
     RECT  68.436 31.351 76.446 31.531 ;
     RECT  138.528 31.387 138.654 31.559 ;
     RECT  5.115 30.839 6.282 31.579 ;
     RECT  1.08 31.531 1.098 31.621 ;
     RECT  156.315 29.767 156.762 31.621 ;
     RECT  68.436 31.531 76.59 31.649 ;
     RECT  115.815 31.195 116.694 31.649 ;
     RECT  138.528 31.559 138.546 31.649 ;
     RECT  156.24 31.621 156.762 31.649 ;
     RECT  26.715 31.531 67.662 31.657 ;
     RECT  68.436 31.649 76.446 31.657 ;
     RECT  11.952 31.277 13.497 31.757 ;
     RECT  1.98 31.531 3.978 31.765 ;
     RECT  7.815 30.983 8.154 31.765 ;
     RECT  9 31.339 9.09 31.765 ;
     RECT  111.492 30.451 111.51 31.765 ;
     RECT  112.68 30.839 113.397 31.765 ;
     RECT  118.515 30.415 119.502 31.765 ;
     RECT  120.276 31.723 120.294 31.765 ;
     RECT  1.98 31.765 4.158 31.801 ;
     RECT  5.115 31.579 6.354 31.801 ;
     RECT  24.015 31.415 25.83 31.829 ;
     RECT  118.515 31.765 120.294 31.829 ;
     RECT  7.815 31.765 9.09 31.891 ;
     RECT  12.816 31.757 13.497 31.919 ;
     RECT  14.256 31.277 14.598 31.919 ;
     RECT  24.015 31.829 24.39 31.919 ;
     RECT  25.236 31.829 25.83 31.919 ;
     RECT  14.256 31.919 14.418 31.955 ;
     RECT  14.4 31.955 14.418 32.027 ;
     RECT  11.952 31.757 11.97 32.063 ;
     RECT  110.415 2.413 110.697 32.071 ;
     RECT  111.492 31.765 113.397 32.071 ;
     RECT  240.015 2.413 240.297 32.071 ;
     RECT  7.38 31.891 9.09 32.161 ;
     RECT  242.715 2.413 242.997 32.161 ;
     RECT  248.115 29.605 248.994 32.161 ;
     RECT  110.415 32.071 113.397 32.189 ;
     RECT  239.328 32.071 240.297 32.189 ;
     RECT  26.715 31.657 76.446 32.197 ;
     RECT  94.215 2.413 94.497 32.203 ;
     RECT  111.708 32.189 113.397 32.203 ;
     RECT  25.236 31.919 25.758 32.237 ;
     RECT  237.315 2.413 237.597 32.269 ;
     RECT  1.98 31.801 6.354 32.299 ;
     RECT  7.128 32.161 9.09 32.299 ;
     RECT  15.915 2.413 16.197 32.299 ;
     RECT  107.715 2.413 107.997 32.299 ;
     RECT  110.415 32.189 110.97 32.299 ;
     RECT  82.656 32.203 82.674 32.333 ;
     RECT  94.215 32.203 94.518 32.333 ;
     RECT  106.596 32.203 106.614 32.333 ;
     RECT  111.708 32.203 113.418 32.333 ;
     RECT  248.115 32.161 249.066 32.341 ;
     RECT  118.515 31.829 120.15 32.369 ;
     RECT  237.315 32.269 238.302 32.369 ;
     RECT  242.136 32.161 242.997 32.369 ;
     RECT  84.636 32.299 84.654 32.395 ;
     RECT  96.915 14.957 97.197 32.431 ;
     RECT  156.24 31.649 156.597 32.431 ;
     RECT  84.636 32.395 84.978 32.459 ;
     RECT  110.376 32.299 110.97 32.459 ;
     RECT  15.804 32.299 16.197 32.477 ;
     RECT  96.804 32.431 97.197 32.477 ;
     RECT  98.676 32.251 98.694 32.477 ;
     RECT  107.604 32.299 107.997 32.477 ;
     RECT  110.415 32.459 110.97 32.477 ;
     RECT  114.588 31.801 114.606 32.477 ;
     RECT  122.544 32.299 122.562 32.477 ;
     RECT  156.24 32.431 156.654 32.495 ;
     RECT  1.98 32.299 9.09 32.539 ;
     RECT  115.815 31.649 116.586 32.603 ;
     RECT  247.824 32.341 249.138 32.611 ;
     RECT  117.648 32.035 117.666 32.639 ;
     RECT  26.568 32.197 76.446 32.729 ;
     RECT  247.752 32.611 249.138 32.729 ;
     RECT  12.852 31.919 13.497 32.773 ;
     RECT  21.315 31.289 21.597 32.779 ;
     RECT  26.568 32.729 28.638 32.801 ;
     RECT  29.415 32.729 76.446 32.837 ;
     RECT  111.708 32.333 113.397 32.837 ;
     RECT  78.015 2.413 78.297 32.845 ;
     RECT  140.115 2.413 140.397 32.845 ;
     RECT  245.415 2.413 245.697 32.881 ;
     RECT  246.852 31.621 246.87 32.881 ;
     RECT  21.096 32.779 21.597 32.909 ;
     RECT  26.568 32.801 28.35 32.909 ;
     RECT  245.415 32.881 246.87 32.999 ;
     RECT  248.115 32.729 249.138 33.043 ;
     RECT  10.515 29.549 11.106 33.067 ;
     RECT  78.015 32.845 78.642 33.071 ;
     RECT  1.98 32.539 9.27 33.079 ;
     RECT  10.008 33.067 11.106 33.079 ;
     RECT  29.415 32.837 75.87 33.101 ;
     RECT  68.832 33.101 75.87 33.149 ;
     RECT  102.315 2.413 102.597 33.211 ;
     RECT  18.615 30.883 19.206 33.241 ;
     RECT  99.615 2.413 99.897 33.241 ;
     RECT  101.808 33.211 102.597 33.269 ;
     RECT  99.615 33.241 100.278 33.293 ;
     RECT  0.108 33.259 0.126 33.307 ;
     RECT  1.98 33.079 11.106 33.349 ;
     RECT  11.844 33.277 11.862 33.349 ;
     RECT  25.488 32.237 25.758 33.349 ;
     RECT  14.832 32.779 14.85 33.403 ;
     RECT  68.868 33.149 75.87 33.413 ;
     RECT  118.515 32.369 119.718 33.413 ;
     RECT  18.615 33.241 19.494 33.421 ;
     RECT  0.108 33.307 0.198 33.437 ;
     RECT  0.108 33.437 0.126 33.449 ;
     RECT  93.06 3.137 93.078 33.449 ;
     RECT  119.7 33.413 119.718 33.449 ;
     RECT  18.615 33.421 19.782 33.499 ;
     RECT  110.415 32.477 110.697 33.511 ;
     RECT  17.892 33.499 19.782 33.539 ;
     RECT  76.644 33.385 76.662 33.539 ;
     RECT  140.115 32.845 140.814 33.539 ;
     RECT  129.315 2.413 129.597 33.547 ;
     RECT  148.215 2.413 148.497 33.547 ;
     RECT  14.76 33.403 14.85 33.581 ;
     RECT  17.568 33.547 17.622 33.584 ;
     RECT  68.904 33.413 75.87 33.619 ;
     RECT  115.815 32.603 116.097 33.619 ;
     RECT  123.915 2.413 124.197 33.619 ;
     RECT  129.315 33.547 129.69 33.619 ;
     RECT  21.204 32.909 21.597 33.643 ;
     RECT  110.415 33.511 111.114 33.655 ;
     RECT  111.996 32.837 113.397 33.655 ;
     RECT  115.74 33.619 116.097 33.655 ;
     RECT  80.715 2.413 80.997 33.691 ;
     RECT  129.315 33.619 130.302 33.691 ;
     RECT  1.08 31.621 1.134 33.725 ;
     RECT  123.915 33.619 124.866 33.781 ;
     RECT  21.168 33.643 21.597 33.787 ;
     RECT  26.568 32.909 27.882 33.809 ;
     RECT  68.904 33.619 76.23 33.809 ;
     RECT  15.84 32.477 16.197 33.817 ;
     RECT  114.336 33.655 114.354 33.817 ;
     RECT  115.092 33.655 116.097 33.817 ;
     RECT  127.692 33.691 127.71 33.817 ;
     RECT  128.7 33.691 130.302 33.817 ;
     RECT  14.832 33.581 14.85 33.869 ;
     RECT  21.168 33.787 21.69 33.869 ;
     RECT  106.596 33.691 106.614 33.881 ;
     RECT  24.015 31.919 24.297 33.889 ;
     RECT  29.415 33.101 67.842 33.889 ;
     RECT  126.615 2.413 126.897 33.889 ;
     RECT  127.692 33.817 130.302 33.889 ;
     RECT  248.115 33.043 249.246 33.889 ;
     RECT  21.315 33.869 21.69 33.917 ;
     RECT  22.824 33.307 22.842 33.917 ;
     RECT  147.636 33.547 148.497 33.917 ;
     RECT  126.615 33.889 130.302 33.925 ;
     RECT  156.315 32.495 156.654 33.953 ;
     RECT  25.128 33.349 25.758 33.961 ;
     RECT  80.208 33.691 80.997 33.961 ;
     RECT  126.615 33.925 130.374 33.961 ;
     RECT  25.128 33.961 25.794 34.051 ;
     RECT  26.568 33.809 27.702 34.051 ;
     RECT  126.615 33.961 130.518 34.051 ;
     RECT  234.615 2.413 234.897 34.051 ;
     RECT  256.215 2.413 256.497 34.051 ;
     RECT  121.068 30.299 121.626 34.075 ;
     RECT  25.128 34.051 27.702 34.079 ;
     RECT  80.1 33.961 80.997 34.079 ;
     RECT  246.852 32.999 246.87 34.079 ;
     RECT  18.615 33.539 19.782 34.109 ;
     RECT  234.615 34.051 234.918 34.109 ;
     RECT  120.924 34.075 121.626 34.115 ;
     RECT  29.415 33.889 67.914 34.123 ;
     RECT  253.515 2.413 253.797 34.123 ;
     RECT  254.664 33.961 254.682 34.123 ;
     RECT  1.08 33.725 1.098 34.157 ;
     RECT  234.615 34.109 234.897 34.159 ;
     RECT  29.415 34.123 68.058 34.195 ;
     RECT  68.904 33.809 75.978 34.195 ;
     RECT  105.015 2.413 105.297 34.195 ;
     RECT  118.515 33.413 118.797 34.195 ;
     RECT  28.656 34.195 28.674 34.219 ;
     RECT  25.128 34.079 27.054 34.231 ;
     RECT  253.515 34.123 254.682 34.231 ;
     RECT  255.996 34.051 256.497 34.231 ;
     RECT  25.092 34.231 27.054 34.259 ;
     RECT  257.616 34.123 257.634 34.267 ;
     RECT  110.415 33.655 113.397 34.321 ;
     RECT  114.192 33.817 116.097 34.321 ;
     RECT  126.615 34.051 131.094 34.321 ;
     RECT  196.815 2.413 197.097 34.321 ;
     RECT  245.415 32.999 245.697 34.321 ;
     RECT  250.815 2.413 251.097 34.321 ;
     RECT  252.792 34.231 256.497 34.321 ;
     RECT  121.215 34.115 121.626 34.349 ;
     RECT  1.98 33.349 11.862 34.357 ;
     RECT  12.6 32.773 13.497 34.357 ;
     RECT  123.696 33.781 124.866 34.357 ;
     RECT  233.532 33.925 233.55 34.357 ;
     RECT  234.576 34.159 234.897 34.357 ;
     RECT  28.548 34.219 28.674 34.385 ;
     RECT  123.696 34.357 124.974 34.385 ;
     RECT  118.152 34.195 118.797 34.393 ;
     RECT  248.04 33.889 249.246 34.393 ;
     RECT  117.252 32.809 117.27 34.429 ;
     RECT  118.008 34.393 118.797 34.429 ;
     RECT  199.515 2.413 199.797 34.429 ;
     RECT  233.532 34.357 234.897 34.429 ;
     RECT  29.415 34.195 75.978 34.459 ;
     RECT  137.415 2.413 137.697 34.459 ;
     RECT  123.084 34.393 123.174 34.465 ;
     RECT  257.616 34.267 257.67 34.493 ;
     RECT  123.915 34.385 124.974 34.501 ;
     RECT  199.08 34.429 199.797 34.501 ;
     RECT  233.352 34.429 234.897 34.501 ;
     RECT  248.04 34.393 249.318 34.501 ;
     RECT  252.252 34.321 256.497 34.501 ;
     RECT  25.092 34.259 26.997 34.529 ;
     RECT  110.415 34.321 116.097 34.591 ;
     RECT  123.048 34.465 123.174 34.591 ;
     RECT  126.288 34.321 131.094 34.591 ;
     RECT  132.015 2.413 132.297 34.591 ;
     RECT  137.415 34.459 138.186 34.591 ;
     RECT  250.815 34.321 251.298 34.591 ;
     RECT  117.252 34.429 118.797 34.619 ;
     RECT  122.544 34.591 123.174 34.619 ;
     RECT  198.9 34.501 199.797 34.619 ;
     RECT  236.088 34.465 236.106 34.619 ;
     RECT  78.015 33.071 78.297 34.627 ;
     RECT  233.244 34.501 234.897 34.627 ;
     RECT  250.236 34.591 251.298 34.627 ;
     RECT  122.544 34.619 123.066 34.655 ;
     RECT  14.868 33.961 14.886 34.663 ;
     RECT  78.015 34.627 78.678 34.663 ;
     RECT  233.172 34.627 234.897 34.685 ;
     RECT  29.196 34.459 75.978 34.691 ;
     RECT  110.415 34.591 116.154 34.691 ;
     RECT  137.415 34.591 138.69 34.691 ;
     RECT  196.815 34.321 197.262 34.699 ;
     RECT  29.196 34.691 75.798 34.727 ;
     RECT  137.415 34.691 138.546 34.727 ;
     RECT  199.152 34.619 199.797 34.727 ;
     RECT  247.68 34.501 249.354 34.727 ;
     RECT  96.915 32.477 97.197 34.735 ;
     RECT  248.004 34.727 249.354 34.735 ;
     RECT  25.164 34.529 26.997 34.763 ;
     RECT  245.415 34.321 246.294 34.763 ;
     RECT  257.328 34.555 257.346 34.763 ;
     RECT  102.315 33.269 102.597 34.771 ;
     RECT  149.616 34.231 149.634 34.771 ;
     RECT  78.015 34.663 79.074 34.781 ;
     RECT  252.144 34.501 256.497 34.781 ;
     RECT  25.524 34.763 26.997 34.799 ;
     RECT  29.232 34.727 75.798 34.799 ;
     RECT  252.324 34.781 256.497 34.799 ;
     RECT  1.98 34.357 13.497 34.861 ;
     RECT  1.98 34.861 13.554 34.877 ;
     RECT  23.94 33.889 24.297 34.889 ;
     RECT  196.815 34.699 197.766 34.889 ;
     RECT  14.868 34.663 15.102 34.897 ;
     RECT  17.604 33.584 17.622 34.897 ;
     RECT  149.616 34.771 149.886 34.897 ;
     RECT  194.115 2.413 194.397 34.897 ;
     RECT  149.292 34.897 149.886 34.925 ;
     RECT  86.115 2.413 86.397 34.939 ;
     RECT  96.915 34.735 97.326 34.939 ;
     RECT  259.02 34.699 259.038 34.961 ;
     RECT  123.915 34.501 125.55 34.969 ;
     RECT  126.288 34.591 132.297 34.969 ;
     RECT  86.115 34.939 86.67 34.987 ;
     RECT  17.604 34.897 17.658 34.997 ;
     RECT  15.84 33.817 16.434 35.005 ;
     RECT  17.604 34.997 17.622 35.005 ;
     RECT  105.015 34.195 105.462 35.005 ;
     RECT  106.596 34.939 106.614 35.005 ;
     RECT  111.924 34.691 116.154 35.005 ;
     RECT  2.268 34.877 13.554 35.021 ;
     RECT  78.015 34.781 78.894 35.021 ;
     RECT  194.115 34.897 194.454 35.032 ;
     RECT  150.915 2.413 151.197 35.041 ;
     RECT  153.615 2.413 153.897 35.041 ;
     RECT  248.004 34.735 249.39 35.041 ;
     RECT  250.164 34.627 251.298 35.041 ;
     RECT  105.015 35.005 106.614 35.069 ;
     RECT  145.515 2.413 145.797 35.131 ;
     RECT  146.592 35.035 146.61 35.131 ;
     RECT  153.615 35.041 154.458 35.131 ;
     RECT  161.715 2.413 161.997 35.131 ;
     RECT  169.815 2.413 170.097 35.131 ;
     RECT  177.915 2.413 178.197 35.131 ;
     RECT  188.715 2.413 188.997 35.131 ;
     RECT  196.815 34.889 197.37 35.131 ;
     RECT  204.915 2.413 205.197 35.131 ;
     RECT  231.915 2.413 232.197 35.131 ;
     RECT  237.315 32.369 237.597 35.131 ;
     RECT  117.252 34.619 117.522 35.159 ;
     RECT  248.004 35.041 251.406 35.159 ;
     RECT  0.144 34.939 0.162 35.165 ;
     RECT  231.48 35.131 232.197 35.167 ;
     RECT  250.524 35.159 251.406 35.168 ;
     RECT  196.704 35.131 197.37 35.195 ;
     RECT  230.472 34.663 230.49 35.203 ;
     RECT  258.156 34.843 258.174 35.231 ;
     RECT  80.715 34.079 80.997 35.239 ;
     RECT  250.524 35.168 251.37 35.267 ;
     RECT  96.876 34.939 97.326 35.269 ;
     RECT  2.376 35.021 13.554 35.275 ;
     RECT  102.315 34.771 102.69 35.275 ;
     RECT  105.015 35.069 105.894 35.303 ;
     RECT  110.415 34.691 111.186 35.303 ;
     RECT  117.252 35.159 117.486 35.303 ;
     RECT  150.48 35.041 151.197 35.303 ;
     RECT  194.115 35.032 194.49 35.303 ;
     RECT  96.876 35.269 97.506 35.309 ;
     RECT  95.94 14.957 95.958 35.323 ;
     RECT  2.376 35.275 13.914 35.339 ;
     RECT  15.84 35.005 17.622 35.339 ;
     RECT  149.292 34.925 149.562 35.339 ;
     RECT  79.992 35.239 80.997 35.357 ;
     RECT  18.615 34.109 19.206 35.401 ;
     RECT  86.115 34.987 86.742 35.401 ;
     RECT  186.015 2.413 186.297 35.401 ;
     RECT  188.604 35.131 188.997 35.401 ;
     RECT  199.404 34.727 199.797 35.401 ;
     RECT  204.804 35.131 205.197 35.401 ;
     RECT  252.9 34.799 256.497 35.419 ;
     RECT  257.22 35.131 257.238 35.419 ;
     RECT  29.415 34.799 75.798 35.429 ;
     RECT  78.015 35.021 78.75 35.429 ;
     RECT  148.14 33.917 148.497 35.429 ;
     RECT  190.404 35.131 190.422 35.437 ;
     RECT  102.315 35.275 102.726 35.453 ;
     RECT  230.472 35.203 230.598 35.465 ;
     RECT  230.472 35.465 230.49 35.473 ;
     RECT  248.004 35.159 249.75 35.473 ;
     RECT  29.415 35.429 58.158 35.501 ;
     RECT  90.612 35.401 90.63 35.501 ;
     RECT  138.528 34.727 138.546 35.509 ;
     RECT  141.984 34.171 142.002 35.509 ;
     RECT  142.815 2.413 143.097 35.509 ;
     RECT  186.015 35.401 186.426 35.509 ;
     RECT  190.404 35.437 190.494 35.509 ;
     RECT  198.36 35.401 198.378 35.509 ;
     RECT  247.464 35.473 249.75 35.509 ;
     RECT  111.924 35.005 116.514 35.515 ;
     RECT  59.115 35.429 61.002 35.537 ;
     RECT  149.544 35.339 149.562 35.537 ;
     RECT  188.604 35.401 189.054 35.537 ;
     RECT  196.704 35.195 197.154 35.537 ;
     RECT  198.36 35.509 198.45 35.537 ;
     RECT  199.404 35.401 199.854 35.537 ;
     RECT  204.804 35.401 205.254 35.537 ;
     RECT  18.615 35.401 19.674 35.545 ;
     RECT  25.596 34.799 26.997 35.545 ;
     RECT  231.408 35.167 232.197 35.545 ;
     RECT  22.824 35.401 22.842 35.573 ;
     RECT  230.292 35.473 230.49 35.573 ;
     RECT  259.056 34.987 259.11 35.573 ;
     RECT  14.832 34.897 15.102 35.581 ;
     RECT  15.84 35.339 16.506 35.581 ;
     RECT  24.015 34.889 24.297 35.581 ;
     RECT  111.708 35.515 116.514 35.581 ;
     RECT  141.984 35.509 143.097 35.581 ;
     RECT  226.515 2.413 226.797 35.581 ;
     RECT  25.344 35.545 26.997 35.582 ;
     RECT  138.528 35.509 138.582 35.597 ;
     RECT  145.515 35.131 146.61 35.597 ;
     RECT  153.615 35.131 154.494 35.597 ;
     RECT  161.715 35.131 162.486 35.597 ;
     RECT  169.815 35.131 170.442 35.597 ;
     RECT  177.915 35.131 178.434 35.597 ;
     RECT  190.404 35.509 190.566 35.597 ;
     RECT  206.352 35.131 206.37 35.597 ;
     RECT  214.344 35.131 214.362 35.597 ;
     RECT  222.3 35.131 222.318 35.597 ;
     RECT  78.015 35.429 78.714 35.609 ;
     RECT  92.916 35.509 92.934 35.609 ;
     RECT  138.564 35.597 138.582 35.609 ;
     RECT  153.615 35.597 153.99 35.609 ;
     RECT  186.015 35.509 186.498 35.609 ;
     RECT  188.604 35.537 188.997 35.609 ;
     RECT  190.548 35.597 190.566 35.609 ;
     RECT  196.704 35.537 197.097 35.609 ;
     RECT  198.432 35.537 198.45 35.609 ;
     RECT  199.404 35.537 199.797 35.609 ;
     RECT  204.804 35.537 205.197 35.609 ;
     RECT  233.352 34.685 234.897 35.659 ;
     RECT  17.604 35.339 17.622 35.699 ;
     RECT  25.344 35.582 25.578 35.699 ;
     RECT  53.208 35.501 58.158 35.699 ;
     RECT  61.815 35.429 74.502 35.699 ;
     RECT  75.24 35.429 75.654 35.699 ;
     RECT  102.315 35.453 102.69 35.699 ;
     RECT  105.015 35.303 105.786 35.699 ;
     RECT  141.984 35.581 143.19 35.699 ;
     RECT  226.296 35.581 226.797 35.699 ;
     RECT  1.152 35.563 1.17 35.707 ;
     RECT  233.28 35.659 234.897 35.707 ;
     RECT  252.9 35.419 257.238 35.707 ;
     RECT  63.252 35.699 74.502 35.735 ;
     RECT  142.524 35.699 143.19 35.735 ;
     RECT  230.292 35.573 230.346 35.735 ;
     RECT  78.015 35.609 78.678 35.741 ;
     RECT  82.656 35.509 82.674 35.741 ;
     RECT  2.376 35.339 13.497 35.755 ;
     RECT  18.615 35.545 19.71 35.771 ;
     RECT  63.396 35.735 74.502 35.771 ;
     RECT  86.115 35.401 86.994 35.771 ;
     RECT  259.092 35.573 259.11 35.771 ;
     RECT  96.876 35.309 97.197 35.779 ;
     RECT  59.115 35.537 60.174 35.807 ;
     RECT  63.648 35.771 74.502 35.807 ;
     RECT  95.4 35.323 95.958 35.807 ;
     RECT  96.804 35.779 97.197 35.815 ;
     RECT  252.9 35.707 257.634 35.815 ;
     RECT  95.4 35.807 95.418 35.843 ;
     RECT  111.708 35.581 116.91 35.843 ;
     RECT  18.615 35.771 19.602 35.879 ;
     RECT  25.344 35.699 25.506 35.879 ;
     RECT  53.388 35.699 58.158 35.879 ;
     RECT  64.008 35.807 74.502 35.879 ;
     RECT  105.015 35.699 105.714 35.879 ;
     RECT  2.124 35.755 13.497 35.885 ;
     RECT  247.392 35.509 249.75 35.941 ;
     RECT  250.524 35.267 251.097 35.941 ;
     RECT  245.415 34.763 245.697 35.947 ;
     RECT  64.515 35.879 74.502 35.969 ;
     RECT  96.3 35.815 97.197 35.969 ;
     RECT  231.372 35.545 232.197 35.969 ;
     RECT  247.392 35.941 251.097 35.969 ;
     RECT  122.544 34.655 122.562 35.977 ;
     RECT  0.828 35.707 1.17 35.995 ;
     RECT  247.968 35.969 251.097 35.995 ;
     RECT  71.424 35.969 74.178 36.005 ;
     RECT  96.696 35.969 97.197 36.005 ;
     RECT  122.544 35.977 122.598 36.013 ;
     RECT  252.792 35.815 257.634 36.029 ;
     RECT  14.832 35.581 16.506 36.041 ;
     RECT  59.115 35.807 60.138 36.041 ;
     RECT  71.568 36.005 74.178 36.041 ;
     RECT  121.215 34.349 121.497 36.049 ;
     RECT  59.115 36.041 59.526 36.077 ;
     RECT  142.815 35.735 143.19 36.077 ;
     RECT  152.208 35.815 152.226 36.077 ;
     RECT  237.315 35.131 238.302 36.077 ;
     RECT  245.415 35.947 245.79 36.077 ;
     RECT  24.015 35.581 24.57 36.091 ;
     RECT  25.344 35.879 25.362 36.091 ;
     RECT  145.515 35.597 145.797 36.091 ;
     RECT  24.015 36.091 25.362 36.113 ;
     RECT  111.708 35.843 116.874 36.121 ;
     RECT  121.215 36.049 121.698 36.121 ;
     RECT  122.544 36.013 122.634 36.121 ;
     RECT  134.715 2.413 134.997 36.121 ;
     RECT  179.352 36.085 179.37 36.121 ;
     RECT  231.915 35.969 232.197 36.121 ;
     RECT  0.576 35.995 1.17 36.139 ;
     RECT  25.092 36.113 25.362 36.149 ;
     RECT  71.676 36.041 74.178 36.173 ;
     RECT  14.832 36.041 16.47 36.211 ;
     RECT  24.015 36.113 24.297 36.211 ;
     RECT  14.796 36.211 16.47 36.239 ;
     RECT  53.388 35.879 57.474 36.239 ;
     RECT  64.515 35.969 70.197 36.239 ;
     RECT  71.676 36.173 73.854 36.239 ;
     RECT  121.215 36.121 122.994 36.239 ;
     RECT  134.715 36.121 135.198 36.239 ;
     RECT  144.792 36.091 145.797 36.239 ;
     RECT  179.352 36.121 179.694 36.239 ;
     RECT  230.328 35.735 230.346 36.239 ;
     RECT  247.968 35.995 251.154 36.239 ;
     RECT  252.792 36.029 253.797 36.239 ;
     RECT  29.415 35.501 52.038 36.247 ;
     RECT  53.388 36.239 57.438 36.269 ;
     RECT  149.328 36.211 149.346 36.269 ;
     RECT  65.7 36.239 70.197 36.275 ;
     RECT  71.676 36.239 73.71 36.275 ;
     RECT  233.1 35.707 234.897 36.275 ;
     RECT  14.796 36.239 16.326 36.283 ;
     RECT  60.984 35.537 61.002 36.311 ;
     RECT  72.216 36.275 73.71 36.311 ;
     RECT  75.24 35.699 75.597 36.311 ;
     RECT  252 36.085 252.018 36.319 ;
     RECT  110.415 35.303 110.697 36.331 ;
     RECT  111.672 36.121 116.874 36.331 ;
     RECT  69.336 36.275 70.197 36.347 ;
     RECT  248.04 36.239 251.154 36.355 ;
     RECT  252 36.319 252.27 36.355 ;
     RECT  248.04 36.355 252.27 36.365 ;
     RECT  14.724 36.283 16.326 36.383 ;
     RECT  53.388 36.269 57.366 36.383 ;
     RECT  65.7 36.275 68.418 36.383 ;
     RECT  134.715 36.239 135.126 36.383 ;
     RECT  248.04 36.365 252.018 36.383 ;
     RECT  118.515 34.619 118.797 36.391 ;
     RECT  119.664 36.121 119.682 36.391 ;
     RECT  72.396 36.311 73.458 36.392 ;
     RECT  248.04 36.383 251.298 36.413 ;
     RECT  65.7 36.383 65.718 36.419 ;
     RECT  66.744 36.383 68.418 36.419 ;
     RECT  248.04 36.413 251.154 36.419 ;
     RECT  0.144 36.139 1.17 36.461 ;
     RECT  231.915 36.121 232.362 36.481 ;
     RECT  233.1 36.275 233.766 36.481 ;
     RECT  53.388 36.383 54.666 36.509 ;
     RECT  55.404 36.383 57.366 36.509 ;
     RECT  67.215 36.419 68.418 36.509 ;
     RECT  72.432 36.392 73.422 36.509 ;
     RECT  110.415 36.331 116.874 36.509 ;
     RECT  141.66 35.815 141.678 36.509 ;
     RECT  110.415 36.509 111.15 36.515 ;
     RECT  29.415 36.247 52.542 36.517 ;
     RECT  53.388 36.509 54.594 36.517 ;
     RECT  118.515 36.391 120.078 36.517 ;
     RECT  121.215 36.239 122.706 36.517 ;
     RECT  78.015 35.741 78.606 36.523 ;
     RECT  86.115 35.771 86.397 36.523 ;
     RECT  55.404 36.509 57.186 36.545 ;
     RECT  68.22 36.509 68.238 36.545 ;
     RECT  111.888 36.509 116.874 36.545 ;
     RECT  255.096 36.029 257.634 36.545 ;
     RECT  29.415 36.517 54.594 36.553 ;
     RECT  134.715 36.383 134.997 36.571 ;
     RECT  78.015 36.523 78.678 36.653 ;
     RECT  2.268 35.885 13.497 36.751 ;
     RECT  21.315 33.917 21.597 36.751 ;
     RECT  96.915 36.005 97.197 36.751 ;
     RECT  110.415 36.515 110.754 36.751 ;
     RECT  86.115 36.523 86.418 36.763 ;
     RECT  107.715 32.477 107.997 36.763 ;
     RECT  55.404 36.545 55.422 36.779 ;
     RECT  134.316 36.571 134.997 36.779 ;
     RECT  255.708 36.545 257.634 36.779 ;
     RECT  118.515 36.517 122.706 36.787 ;
     RECT  21.204 36.751 21.597 36.797 ;
     RECT  144.468 36.391 144.486 36.811 ;
     RECT  29.376 36.553 54.594 36.815 ;
     RECT  23.94 36.211 24.297 36.845 ;
     RECT  231.915 36.481 233.766 36.851 ;
     RECT  123.915 34.969 132.297 36.859 ;
     RECT  111.924 36.545 116.874 36.887 ;
     RECT  22.824 36.763 22.842 36.893 ;
     RECT  86.115 36.763 86.67 36.893 ;
     RECT  96.876 36.751 97.197 36.893 ;
     RECT  107.604 36.763 107.997 36.893 ;
     RECT  110.376 36.751 110.754 36.893 ;
     RECT  17.244 36.823 17.262 36.895 ;
     RECT  141.408 36.619 141.426 36.895 ;
     RECT  142.815 36.077 143.097 36.895 ;
     RECT  137.415 34.727 137.697 36.907 ;
     RECT  180.615 2.413 180.897 36.907 ;
     RECT  17.172 36.895 17.262 36.923 ;
     RECT  112.248 36.887 116.874 36.931 ;
     RECT  118.116 36.787 122.706 36.931 ;
     RECT  25.092 36.149 25.182 36.959 ;
     RECT  29.376 36.815 47.25 36.959 ;
     RECT  48.096 36.815 54.594 36.959 ;
     RECT  123.915 36.859 132.57 36.959 ;
     RECT  233.064 36.851 233.766 36.989 ;
     RECT  80.715 35.357 80.997 37.021 ;
     RECT  81.864 36.859 81.882 37.021 ;
     RECT  138.888 36.931 138.906 37.021 ;
     RECT  142.2 36.895 143.097 37.021 ;
     RECT  144.216 36.811 144.486 37.021 ;
     RECT  17.172 36.923 17.19 37.049 ;
     RECT  48.096 36.959 54.522 37.049 ;
     RECT  80.715 37.021 81.882 37.049 ;
     RECT  123.915 36.959 132.498 37.049 ;
     RECT  136.908 36.907 137.697 37.049 ;
     RECT  142.2 37.021 144.486 37.049 ;
     RECT  248.04 36.419 249.39 37.049 ;
     RECT  2.232 36.751 13.497 37.057 ;
     RECT  14.832 36.383 16.326 37.057 ;
     RECT  28.476 36.661 28.494 37.057 ;
     RECT  29.376 36.959 47.034 37.057 ;
     RECT  48.096 37.049 51.462 37.085 ;
     RECT  138.888 37.021 139.086 37.085 ;
     RECT  28.476 37.057 47.034 37.099 ;
     RECT  52.884 37.049 54.522 37.133 ;
     RECT  53.208 37.133 54.522 37.157 ;
     RECT  144.756 37.057 144.774 37.157 ;
     RECT  230.292 37.057 230.31 37.157 ;
     RECT  233.1 36.989 233.766 37.157 ;
     RECT  28.332 37.099 47.034 37.193 ;
     RECT  2.232 37.057 14.058 37.201 ;
     RECT  14.832 37.057 17.082 37.201 ;
     RECT  140.115 33.539 140.397 37.201 ;
     RECT  245.415 36.077 245.697 37.201 ;
     RECT  123.915 37.049 130.374 37.229 ;
     RECT  2.232 37.201 17.082 37.291 ;
     RECT  2.196 37.291 17.082 37.319 ;
     RECT  131.544 37.049 132.297 37.319 ;
     RECT  79.812 37.165 79.83 37.327 ;
     RECT  112.248 36.931 122.706 37.327 ;
     RECT  123.915 37.229 130.194 37.327 ;
     RECT  255.708 36.779 256.734 37.327 ;
     RECT  139.5 37.201 140.397 37.355 ;
     RECT  245.415 37.201 246.258 37.363 ;
     RECT  253.224 36.239 253.797 37.363 ;
     RECT  138.528 37.291 138.546 37.391 ;
     RECT  141.3 36.895 141.426 37.391 ;
     RECT  233.1 37.157 233.73 37.391 ;
     RECT  252.504 37.363 253.797 37.399 ;
     RECT  0.144 36.461 0.846 37.421 ;
     RECT  0.576 37.421 0.846 37.435 ;
     RECT  142.2 37.049 143.55 37.435 ;
     RECT  148.215 35.429 148.497 37.435 ;
     RECT  28.332 37.193 45.99 37.463 ;
     RECT  48.096 37.085 51.297 37.463 ;
     RECT  112.248 37.327 130.194 37.463 ;
     RECT  2.196 37.319 14.094 37.469 ;
     RECT  251.964 37.399 253.797 37.471 ;
     RECT  112.248 37.463 125.226 37.486 ;
     RECT  110.415 36.893 110.754 37.499 ;
     RECT  126.432 37.463 130.194 37.499 ;
     RECT  51.015 37.463 51.297 37.547 ;
     RECT  56.415 36.545 56.697 37.547 ;
     RECT  59.115 36.077 59.397 37.547 ;
     RECT  61.815 35.699 62.097 37.547 ;
     RECT  64.515 36.239 64.797 37.547 ;
     RECT  67.215 36.509 67.497 37.547 ;
     RECT  69.915 36.347 70.197 37.547 ;
     RECT  72.615 36.509 72.897 37.547 ;
     RECT  75.315 36.311 75.597 37.547 ;
     RECT  78.015 36.653 78.297 37.547 ;
     RECT  83.415 2.413 83.697 37.547 ;
     RECT  86.115 36.893 86.397 37.547 ;
     RECT  132.015 37.319 132.297 37.547 ;
     RECT  134.715 36.779 134.997 37.547 ;
     RECT  137.415 37.049 137.697 37.547 ;
     RECT  140.115 37.355 140.397 37.547 ;
     RECT  145.515 36.239 145.797 37.547 ;
     RECT  148.032 37.435 148.497 37.547 ;
     RECT  150.915 35.303 151.197 37.547 ;
     RECT  153.615 35.609 153.897 37.547 ;
     RECT  156.315 33.953 156.597 37.547 ;
     RECT  159.015 2.413 159.297 37.547 ;
     RECT  161.715 35.597 161.997 37.547 ;
     RECT  164.415 2.413 164.697 37.547 ;
     RECT  167.115 2.413 167.397 37.547 ;
     RECT  169.815 35.597 170.097 37.547 ;
     RECT  172.515 2.413 172.797 37.547 ;
     RECT  167.115 37.547 167.205 37.561 ;
     RECT  0.576 37.435 1.17 37.579 ;
     RECT  28.332 37.463 33.894 37.589 ;
     RECT  34.815 37.463 41.094 37.589 ;
     RECT  46.764 37.193 47.034 37.589 ;
     RECT  53.208 37.157 54.306 37.589 ;
     RECT  79.812 37.327 79.974 37.589 ;
     RECT  148.032 37.547 148.305 37.589 ;
     RECT  180.615 36.907 181.35 37.589 ;
     RECT  255.456 37.327 256.734 37.589 ;
     RECT  257.616 36.779 257.634 37.589 ;
     RECT  126.432 37.499 129.906 37.613 ;
     RECT  149.58 37.561 149.598 37.613 ;
     RECT  180.615 37.589 181.062 37.613 ;
     RECT  14.832 37.319 17.046 37.625 ;
     RECT  28.332 37.589 33.678 37.625 ;
     RECT  126.432 37.613 126.81 37.625 ;
     RECT  166.176 37.579 166.194 37.625 ;
     RECT  245.415 37.363 246.978 37.625 ;
     RECT  28.944 37.625 33.678 37.661 ;
     RECT  2.196 37.469 13.626 37.733 ;
     RECT  167.004 37.561 167.205 37.741 ;
     RECT  251.964 37.471 254.214 37.741 ;
     RECT  2.196 37.733 13.59 37.769 ;
     RECT  126.615 37.625 126.774 37.769 ;
     RECT  141.624 37.435 143.55 37.769 ;
     RECT  42.012 37.463 45.99 37.817 ;
     RECT  51.015 37.547 51.105 37.817 ;
     RECT  53.208 37.589 53.805 37.817 ;
     RECT  56.415 37.547 56.505 37.817 ;
     RECT  59.115 37.547 59.205 37.817 ;
     RECT  61.815 37.547 61.905 37.817 ;
     RECT  64.515 37.547 64.605 37.817 ;
     RECT  67.215 37.547 67.305 37.817 ;
     RECT  69.915 37.547 70.005 37.817 ;
     RECT  72.615 37.547 72.705 37.817 ;
     RECT  75.315 37.547 75.405 37.817 ;
     RECT  78.015 37.547 78.105 37.817 ;
     RECT  80.715 37.049 81.306 37.817 ;
     RECT  83.415 37.547 83.505 37.817 ;
     RECT  86.115 37.547 86.205 37.817 ;
     RECT  126.615 37.769 126.705 37.817 ;
     RECT  132.015 37.547 132.105 37.817 ;
     RECT  134.715 37.547 134.805 37.817 ;
     RECT  137.415 37.547 137.505 37.817 ;
     RECT  140.115 37.547 140.205 37.817 ;
     RECT  141.624 37.769 143.514 37.817 ;
     RECT  145.515 37.547 145.605 37.817 ;
     RECT  148.215 37.589 148.305 37.817 ;
     RECT  150.915 37.547 151.005 37.817 ;
     RECT  153.615 37.547 153.705 37.817 ;
     RECT  156.315 37.547 156.405 37.817 ;
     RECT  159.015 37.547 159.105 37.817 ;
     RECT  161.715 37.547 161.805 37.817 ;
     RECT  164.415 37.547 164.505 37.817 ;
     RECT  166.356 37.741 167.205 37.817 ;
     RECT  169.815 37.547 169.905 37.817 ;
     RECT  172.515 37.547 172.605 37.817 ;
     RECT  29.304 37.661 33.678 37.859 ;
     RECT  29.304 37.859 33.462 37.895 ;
     RECT  26.316 35.582 26.997 37.903 ;
     RECT  141.624 37.817 142.11 37.931 ;
     RECT  250.815 36.419 251.154 37.939 ;
     RECT  251.964 37.741 254.322 37.939 ;
     RECT  21.315 36.797 21.597 37.963 ;
     RECT  186.015 35.609 186.297 37.963 ;
     RECT  196.815 35.609 197.097 37.963 ;
     RECT  204.915 35.609 205.197 37.963 ;
     RECT  213.015 2.413 213.297 37.963 ;
     RECT  221.115 2.413 221.397 37.963 ;
     RECT  229.215 2.413 229.497 37.963 ;
     RECT  237.315 36.077 237.597 37.963 ;
     RECT  246.888 37.625 246.978 37.963 ;
     RECT  112.248 37.486 124.614 37.967 ;
     RECT  141.624 37.931 141.642 37.967 ;
     RECT  112.572 37.967 124.614 38.003 ;
     RECT  2.196 37.769 12.042 38.039 ;
     RECT  246.888 37.963 247.194 38.059 ;
     RECT  248.115 37.049 249.39 38.059 ;
     RECT  188.715 35.609 188.997 38.101 ;
     RECT  250.815 37.939 254.322 38.101 ;
     RECT  255.456 37.589 256.497 38.101 ;
     RECT  13.068 37.769 13.59 38.129 ;
     RECT  15.915 37.625 17.046 38.129 ;
     RECT  113.115 38.003 124.614 38.129 ;
     RECT  13.215 38.129 13.59 38.141 ;
     RECT  14.832 37.625 14.85 38.141 ;
     RECT  21.315 37.963 21.69 38.141 ;
     RECT  22.824 37.963 22.842 38.141 ;
     RECT  186.015 37.963 186.39 38.141 ;
     RECT  188.715 38.101 189.09 38.141 ;
     RECT  190.404 37.963 190.422 38.141 ;
     RECT  196.815 37.963 197.19 38.141 ;
     RECT  198.36 37.963 198.378 38.141 ;
     RECT  204.915 37.963 205.29 38.141 ;
     RECT  206.352 37.963 206.37 38.141 ;
     RECT  213.015 37.963 213.39 38.141 ;
     RECT  214.344 37.963 214.362 38.141 ;
     RECT  221.115 37.963 221.49 38.141 ;
     RECT  222.3 37.963 222.318 38.141 ;
     RECT  229.215 37.963 230.31 38.141 ;
     RECT  237.315 37.963 238.302 38.141 ;
     RECT  2.196 38.039 11.862 38.165 ;
     RECT  16.956 38.129 17.046 38.165 ;
     RECT  26.316 37.903 27.054 38.165 ;
     RECT  6.66 38.165 11.862 38.189 ;
     RECT  2.196 38.165 5.706 38.201 ;
     RECT  6.66 38.189 8.226 38.201 ;
     RECT  9.036 38.189 11.862 38.201 ;
     RECT  246.888 38.059 249.39 38.201 ;
     RECT  250.815 38.101 256.497 38.203 ;
     RECT  16.956 38.165 16.974 38.237 ;
     RECT  247.5 38.201 249.39 38.237 ;
     RECT  26.316 38.165 26.997 38.273 ;
     RECT  250.2 38.203 256.497 38.333 ;
     RECT  6.948 38.201 8.226 38.399 ;
     RECT  9.036 38.201 11.826 38.399 ;
     RECT  233.1 37.391 233.55 38.435 ;
     RECT  250.236 38.333 256.497 38.435 ;
     RECT  9.036 38.399 10.797 38.471 ;
     RECT  29.415 37.895 33.102 38.471 ;
     RECT  166.356 37.817 167.022 38.471 ;
     RECT  233.1 38.435 233.118 38.471 ;
     RECT  147.168 35.815 147.186 38.507 ;
     RECT  6.948 38.399 8.097 38.543 ;
     RECT  10.08 38.471 10.797 38.543 ;
     RECT  0.576 37.579 1.206 38.579 ;
     RECT  223.815 2.413 224.097 38.641 ;
     RECT  0.576 38.579 1.17 38.669 ;
     RECT  2.196 38.201 5.397 38.669 ;
     RECT  9.036 38.471 9.162 38.669 ;
     RECT  11.808 38.399 11.826 38.669 ;
     RECT  250.632 38.435 256.497 38.669 ;
     RECT  225.18 38.635 225.198 38.675 ;
     RECT  258.228 38.011 258.246 38.713 ;
     RECT  223.815 38.641 224.154 38.717 ;
     RECT  9.144 38.669 9.162 38.741 ;
     RECT  245.415 37.625 245.697 38.749 ;
     RECT  258.192 38.713 258.246 38.765 ;
     RECT  181.836 38.479 181.854 38.777 ;
     RECT  30.42 38.471 33.102 38.821 ;
     RECT  245.415 38.749 246.258 38.849 ;
     RECT  2.196 38.669 4.266 38.939 ;
     RECT  42.012 37.817 42.894 38.947 ;
     RECT  43.668 37.817 45.126 38.947 ;
     RECT  248.115 38.237 249.39 39.019 ;
     RECT  258.192 38.765 258.21 39.056 ;
     RECT  30.42 38.821 33.174 39.083 ;
     RECT  31.392 39.083 33.174 39.119 ;
     RECT  250.815 38.669 256.497 39.181 ;
     RECT  34.815 37.589 40.914 39.209 ;
     RECT  36.072 39.209 40.914 39.281 ;
     RECT  258.156 39.163 258.174 39.281 ;
     RECT  113.115 38.129 124.197 39.325 ;
     RECT  107.715 36.893 107.997 39.451 ;
     RECT  110.415 37.499 110.697 39.451 ;
     RECT  250.815 39.181 256.626 39.451 ;
     RECT  0.576 38.669 0.846 39.479 ;
     RECT  2.196 38.939 3.69 39.479 ;
     RECT  246.852 39.361 246.87 39.479 ;
     RECT  258.12 39.307 258.138 39.551 ;
     RECT  107.604 39.451 107.997 39.581 ;
     RECT  110.376 39.451 110.697 39.581 ;
     RECT  30.42 39.083 30.438 39.587 ;
     RECT  250.815 39.451 256.914 39.595 ;
     RECT  2.196 39.479 3.582 39.659 ;
     RECT  2.196 39.659 3.438 39.749 ;
     RECT  113.115 39.325 124.254 39.749 ;
     RECT  250.815 39.595 256.986 39.865 ;
     RECT  259.092 39.739 259.11 39.883 ;
     RECT  259.02 39.883 259.11 40.013 ;
     RECT  147.06 39.253 147.078 40.055 ;
     RECT  229.215 38.141 229.497 40.123 ;
     RECT  259.092 40.013 259.11 40.127 ;
     RECT  45.972 37.817 45.99 40.199 ;
     RECT  250.815 39.865 257.67 40.205 ;
     RECT  42.012 38.947 45.126 40.244 ;
     RECT  229.215 40.123 229.59 40.267 ;
     RECT  237.315 38.141 237.597 40.267 ;
     RECT  245.415 38.849 245.697 40.267 ;
     RECT  0.828 39.479 0.846 40.289 ;
     RECT  247.968 39.019 249.39 40.289 ;
     RECT  229.215 40.267 230.31 40.301 ;
     RECT  230.292 40.301 230.31 40.397 ;
     RECT  237.315 40.267 238.302 40.397 ;
     RECT  2.196 39.749 3.33 40.559 ;
     RECT  143.244 37.817 143.514 40.559 ;
     RECT  250.815 40.205 256.497 40.603 ;
     RECT  37.515 39.281 40.914 40.675 ;
     RECT  50.148 37.463 50.202 40.739 ;
     RECT  53.208 37.817 53.226 40.739 ;
     RECT  143.244 40.559 143.262 40.739 ;
     RECT  37.44 40.675 40.914 40.756 ;
     RECT  42.012 40.244 44.694 40.756 ;
     RECT  48.096 37.463 49.302 40.784 ;
     RECT  250.272 40.603 256.497 40.801 ;
     RECT  37.44 40.756 44.694 40.829 ;
     RECT  2.196 40.559 2.697 40.865 ;
     RECT  259.02 40.747 259.038 40.877 ;
     RECT  257.256 40.205 257.67 40.891 ;
     RECT  245.415 40.267 246.258 41.009 ;
     RECT  36.648 39.281 36.666 41.035 ;
     RECT  37.44 40.829 44.658 41.035 ;
     RECT  248.115 40.289 249.39 41.071 ;
     RECT  250.236 40.801 256.497 41.071 ;
     RECT  36.108 41.035 44.658 41.099 ;
     RECT  257.256 40.891 258.174 41.243 ;
     RECT  248.115 41.071 256.497 41.251 ;
     RECT  48.096 40.784 48.762 41.324 ;
     RECT  174.384 41.323 174.402 41.341 ;
     RECT  175.215 2.413 175.497 41.341 ;
     RECT  174.384 41.341 175.497 41.369 ;
     RECT  248.115 41.251 256.734 41.369 ;
     RECT  174.708 41.369 175.497 41.405 ;
     RECT  250.596 41.369 256.734 41.441 ;
     RECT  257.58 41.243 258.174 41.441 ;
     RECT  127.944 37.613 129.906 41.513 ;
     RECT  126.504 41.683 126.522 41.783 ;
     RECT  257.652 41.441 258.174 41.783 ;
     RECT  250.776 41.441 256.734 41.819 ;
     RECT  259.092 41.467 259.11 41.899 ;
     RECT  48.744 41.324 48.762 41.909 ;
     RECT  47.016 37.589 47.034 41.945 ;
     RECT  250.776 41.819 251.586 42.089 ;
     RECT  252.432 41.819 256.734 42.187 ;
     RECT  259.056 41.899 259.11 42.287 ;
     RECT  167.832 41.683 167.85 42.457 ;
     RECT  37.44 41.099 44.658 42.461 ;
     RECT  248.115 41.369 249.678 42.485 ;
     RECT  258.156 41.783 258.174 42.521 ;
     RECT  250.815 42.089 251.586 42.565 ;
     RECT  252.432 42.187 257.13 42.565 ;
     RECT  250.815 42.565 257.13 42.593 ;
     RECT  250.815 42.593 257.022 42.629 ;
     RECT  251.856 42.629 257.022 42.719 ;
     RECT  252.324 42.719 257.022 42.755 ;
     RECT  249.12 42.485 249.678 42.961 ;
     RECT  250.815 42.629 251.097 42.961 ;
     RECT  249.12 42.961 251.097 42.989 ;
     RECT  250.236 42.989 251.097 43.169 ;
     RECT  37.44 42.461 44.154 43.2 ;
     RECT  50.148 40.739 50.166 43.2 ;
     RECT  81.252 37.817 81.306 43.2 ;
     RECT  127.944 41.513 129.294 43.2 ;
     RECT  166.356 38.471 166.374 43.2 ;
     RECT  167.652 42.457 167.85 43.2 ;
     RECT  252.324 42.755 252.342 43.295 ;
     RECT  253.188 42.755 257.022 43.331 ;
     RECT  258.192 42.619 258.246 43.439 ;
     RECT  253.515 43.331 256.554 43.529 ;
     RECT  258.228 43.439 258.246 43.673 ;
     RECT  173.232 43.483 173.25 43.681 ;
     RECT  253.515 43.529 256.497 43.709 ;
     RECT  86.796 43.675 86.814 43.771 ;
     RECT  87.768 40.711 87.786 43.799 ;
     RECT  86.796 43.771 86.994 43.835 ;
     RECT  259.092 42.287 259.11 43.871 ;
     RECT  172.692 43.681 173.25 43.915 ;
     RECT  249.12 42.989 249.138 43.943 ;
     RECT  253.515 43.709 255.15 43.949 ;
     RECT  113.115 39.749 124.197 43.951 ;
     RECT  127.944 43.2 167.85 43.979 ;
     RECT  113.115 43.951 124.29 43.997 ;
     RECT  127.944 43.979 167.742 43.997 ;
     RECT  37.44 43.2 81.306 44.041 ;
     RECT  172.692 43.915 173.394 44.069 ;
     RECT  174.168 42.295 174.186 44.069 ;
     RECT  253.515 43.949 254.142 44.069 ;
     RECT  255.024 43.949 255.15 44.069 ;
     RECT  37.44 44.041 81.342 44.093 ;
     RECT  172.692 44.069 172.71 44.093 ;
     RECT  256.032 43.709 256.497 44.105 ;
     RECT  127.944 43.997 167.616 44.149 ;
     RECT  86.976 43.835 86.994 44.189 ;
     RECT  170.388 43.915 170.406 44.189 ;
     RECT  255.06 44.069 255.15 44.249 ;
     RECT  36.216 44.221 36.234 44.347 ;
     RECT  36.108 44.347 36.234 44.477 ;
     RECT  37.44 44.093 81.216 44.539 ;
     RECT  126.504 44.149 126.522 44.753 ;
     RECT  36.72 44.539 81.216 44.765 ;
     RECT  113.115 43.997 124.197 44.887 ;
     RECT  36.72 44.765 39.546 44.957 ;
     RECT  125.424 44.995 125.442 45.121 ;
     RECT  125.352 45.121 125.442 45.245 ;
     RECT  36.72 44.957 38.826 45.265 ;
     RECT  40.608 44.765 81.216 45.329 ;
     RECT  127.728 44.149 167.616 45.341 ;
     RECT  127.728 45.341 128.286 45.391 ;
     RECT  113.115 44.887 124.326 45.563 ;
     RECT  113.115 45.563 114.858 45.689 ;
     RECT  113.115 45.689 114.354 45.725 ;
     RECT  127.692 45.391 128.286 45.725 ;
     RECT  36.684 45.265 38.826 45.797 ;
     RECT  113.115 45.725 114.246 45.869 ;
     RECT  115.596 45.563 124.326 45.869 ;
     RECT  114.228 45.869 114.246 45.959 ;
     RECT  36.684 45.797 36.738 46.157 ;
     RECT  115.668 45.869 124.326 46.157 ;
     RECT  36.684 46.157 36.702 46.171 ;
     RECT  34.815 39.209 35.097 46.201 ;
     RECT  115.815 46.157 124.326 46.201 ;
     RECT  125.352 45.245 125.406 46.201 ;
     RECT  36.504 46.171 36.702 46.229 ;
     RECT  34.815 46.201 35.334 46.253 ;
     RECT  127.692 45.725 127.71 46.301 ;
     RECT  129.096 45.341 167.616 46.747 ;
     RECT  34.815 46.253 35.226 46.769 ;
     RECT  37.515 45.797 38.826 46.769 ;
     RECT  126.504 46.741 126.522 46.877 ;
     RECT  128.808 46.747 167.616 46.939 ;
     RECT  34.815 46.769 35.154 47.039 ;
     RECT  41.292 45.329 81.216 47.039 ;
     RECT  41.652 47.039 81.216 47.261 ;
     RECT  42.696 47.261 81.216 47.357 ;
     RECT  41.652 47.261 41.706 47.453 ;
     RECT  115.815 46.201 125.406 47.453 ;
     RECT  41.688 47.453 41.706 47.549 ;
     RECT  36.684 46.229 36.702 47.615 ;
     RECT  115.815 47.453 124.902 47.645 ;
     RECT  37.515 46.769 38.754 47.731 ;
     RECT  42.768 47.357 81.216 47.741 ;
     RECT  128.772 46.939 167.616 47.741 ;
     RECT  36.72 47.731 38.754 47.849 ;
     RECT  115.815 47.645 124.254 47.849 ;
     RECT  37.515 47.849 38.754 47.933 ;
     RECT  122.508 47.849 124.254 48.029 ;
     RECT  128.232 47.803 128.25 48.029 ;
     RECT  36.72 47.849 36.738 48.119 ;
     RECT  37.515 47.933 38.034 48.119 ;
     RECT  118.44 47.849 121.497 48.119 ;
     RECT  43.092 47.741 81.216 48.155 ;
     RECT  118.515 48.119 120.366 48.227 ;
     RECT  118.515 48.227 119.43 48.263 ;
     RECT  120.348 48.227 120.366 48.263 ;
     RECT  38.772 48.127 38.79 48.299 ;
     RECT  129.348 47.741 167.616 48.299 ;
     RECT  115.815 47.849 117.378 48.389 ;
     RECT  121.212 48.119 121.497 48.389 ;
     RECT  122.508 48.029 124.197 48.389 ;
     RECT  116.82 48.389 116.874 48.425 ;
     RECT  116.856 48.425 116.874 48.461 ;
     RECT  122.508 48.389 123.138 48.763 ;
     RECT  122.22 48.763 123.138 48.941 ;
     RECT  43.2 48.155 81.216 106.11 ;
     RECT  129.6 48.299 167.616 106.11 ;
     RECT  40.407 111.493 40.497 111.763 ;
     RECT  43.107 111.493 43.197 111.763 ;
     RECT  45.807 111.493 45.897 111.763 ;
     RECT  48.507 111.493 48.597 111.763 ;
     RECT  51.207 111.493 51.297 111.763 ;
     RECT  53.907 111.493 53.997 111.763 ;
     RECT  56.607 111.493 56.697 111.763 ;
     RECT  59.307 111.493 59.397 111.763 ;
     RECT  62.007 111.493 62.097 111.763 ;
     RECT  64.707 111.493 64.797 111.763 ;
     RECT  67.407 111.493 67.497 111.763 ;
     RECT  70.107 111.493 70.197 111.763 ;
     RECT  72.807 111.493 72.897 111.763 ;
     RECT  75.507 111.493 75.597 111.763 ;
     RECT  78.207 111.493 78.297 111.763 ;
     RECT  80.907 111.493 80.997 111.763 ;
     RECT  83.607 111.493 83.697 111.763 ;
     RECT  86.307 111.493 86.397 111.763 ;
     RECT  126.807 111.493 126.897 111.763 ;
     RECT  129.507 111.493 129.597 111.763 ;
     RECT  132.207 111.493 132.297 111.763 ;
     RECT  134.907 111.493 134.997 111.763 ;
     RECT  137.607 111.493 137.697 111.763 ;
     RECT  140.307 111.493 140.397 111.763 ;
     RECT  143.007 111.493 143.097 111.763 ;
     RECT  145.707 111.493 145.797 111.763 ;
     RECT  148.407 111.493 148.497 111.763 ;
     RECT  151.107 111.493 151.197 111.763 ;
     RECT  153.807 111.493 153.897 111.763 ;
     RECT  156.507 111.493 156.597 111.763 ;
     RECT  159.207 111.493 159.297 111.763 ;
     RECT  161.907 111.493 161.997 111.763 ;
     RECT  164.607 111.493 164.697 111.763 ;
     RECT  167.307 111.493 167.397 111.763 ;
     RECT  170.007 111.493 170.097 111.763 ;
     RECT  172.707 111.493 172.797 111.763 ;
     RECT  2.415 40.865 2.697 127.187 ;
     RECT  5.115 38.669 5.397 127.187 ;
     RECT  7.815 38.543 8.097 127.187 ;
     RECT  10.515 38.543 10.797 127.187 ;
     RECT  13.215 38.141 13.497 127.187 ;
     RECT  15.915 38.129 16.197 127.187 ;
     RECT  18.615 35.879 18.897 127.187 ;
     RECT  21.315 38.141 21.597 127.187 ;
     RECT  24.015 36.845 24.297 127.187 ;
     RECT  26.715 38.273 26.997 127.187 ;
     RECT  29.415 38.471 29.697 127.187 ;
     RECT  32.115 39.119 32.397 127.187 ;
     RECT  34.815 47.039 35.097 127.187 ;
     RECT  37.515 48.119 37.797 127.187 ;
     RECT  40.215 111.763 40.497 127.187 ;
     RECT  42.915 111.763 43.197 127.187 ;
     RECT  45.615 111.763 45.897 127.187 ;
     RECT  48.315 111.763 48.597 127.187 ;
     RECT  51.015 111.763 51.297 127.187 ;
     RECT  53.715 111.763 53.997 127.187 ;
     RECT  56.415 111.763 56.697 127.187 ;
     RECT  59.115 111.763 59.397 127.187 ;
     RECT  61.815 111.763 62.097 127.187 ;
     RECT  64.515 111.763 64.797 127.187 ;
     RECT  67.215 111.763 67.497 127.187 ;
     RECT  69.915 111.763 70.197 127.187 ;
     RECT  72.615 111.763 72.897 127.187 ;
     RECT  75.315 111.763 75.597 127.187 ;
     RECT  78.015 111.763 78.297 127.187 ;
     RECT  80.715 111.763 80.997 127.187 ;
     RECT  83.415 111.763 83.697 127.187 ;
     RECT  86.115 111.763 86.397 127.187 ;
     RECT  88.815 28.787 89.097 127.187 ;
     RECT  91.515 30.479 91.797 127.187 ;
     RECT  94.215 32.333 94.497 127.187 ;
     RECT  96.915 36.893 97.197 127.187 ;
     RECT  99.615 33.293 99.897 127.187 ;
     RECT  102.315 35.699 102.597 127.187 ;
     RECT  105.015 35.879 105.297 127.187 ;
     RECT  107.715 39.581 107.997 127.187 ;
     RECT  110.415 39.581 110.697 127.187 ;
     RECT  113.115 45.869 113.397 127.187 ;
     RECT  115.815 48.389 116.097 127.187 ;
     RECT  118.515 48.263 118.797 127.187 ;
     RECT  121.215 48.389 121.497 127.187 ;
     RECT  123.915 48.389 124.197 127.187 ;
     RECT  126.615 111.763 126.897 127.187 ;
     RECT  129.315 111.763 129.597 127.187 ;
     RECT  132.015 111.763 132.297 127.187 ;
     RECT  134.715 111.763 134.997 127.187 ;
     RECT  137.415 111.763 137.697 127.187 ;
     RECT  140.115 111.763 140.397 127.187 ;
     RECT  142.815 111.763 143.097 127.187 ;
     RECT  145.515 111.763 145.797 127.187 ;
     RECT  148.215 111.763 148.497 127.187 ;
     RECT  150.915 111.763 151.197 127.187 ;
     RECT  153.615 111.763 153.897 127.187 ;
     RECT  156.315 111.763 156.597 127.187 ;
     RECT  159.015 111.763 159.297 127.187 ;
     RECT  161.715 111.763 161.997 127.187 ;
     RECT  164.415 111.763 164.697 127.187 ;
     RECT  167.115 111.763 167.397 127.187 ;
     RECT  169.815 111.763 170.097 127.187 ;
     RECT  172.515 111.763 172.797 127.187 ;
     RECT  175.215 41.405 175.497 127.187 ;
     RECT  177.915 35.597 178.197 127.187 ;
     RECT  180.615 37.613 180.897 127.187 ;
     RECT  183.315 2.413 183.597 127.187 ;
     RECT  186.015 38.141 186.297 127.187 ;
     RECT  188.715 38.141 188.997 127.187 ;
     RECT  191.415 2.413 191.697 127.187 ;
     RECT  194.115 35.303 194.397 127.187 ;
     RECT  196.815 38.141 197.097 127.187 ;
     RECT  199.515 35.609 199.797 127.187 ;
     RECT  202.215 2.413 202.497 127.187 ;
     RECT  204.915 38.141 205.197 127.187 ;
     RECT  207.615 2.413 207.897 127.187 ;
     RECT  210.315 2.413 210.597 127.187 ;
     RECT  213.015 38.141 213.297 127.187 ;
     RECT  215.715 2.413 215.997 127.187 ;
     RECT  218.415 2.413 218.697 127.187 ;
     RECT  221.115 38.141 221.397 127.187 ;
     RECT  223.815 38.717 224.097 127.187 ;
     RECT  226.515 35.699 226.797 127.187 ;
     RECT  229.215 40.301 229.497 127.187 ;
     RECT  231.915 36.851 232.197 127.187 ;
     RECT  234.615 36.275 234.897 127.187 ;
     RECT  237.315 40.397 237.597 127.187 ;
     RECT  240.015 32.189 240.297 127.187 ;
     RECT  242.715 32.369 242.997 127.187 ;
     RECT  245.415 41.009 245.697 127.187 ;
     RECT  248.115 42.485 248.397 127.187 ;
     RECT  250.815 43.169 251.097 127.187 ;
     RECT  253.515 44.069 253.797 127.187 ;
     RECT  256.215 44.105 256.497 127.187 ;
     RECT  2.415 127.187 2.505 127.457 ;
     RECT  5.115 127.187 5.205 127.457 ;
     RECT  7.815 127.187 7.905 127.457 ;
     RECT  10.515 127.187 10.605 127.457 ;
     RECT  13.215 127.187 13.305 127.457 ;
     RECT  15.915 127.187 16.005 127.457 ;
     RECT  18.615 127.187 18.705 127.457 ;
     RECT  21.315 127.187 21.405 127.457 ;
     RECT  24.015 127.187 24.105 127.457 ;
     RECT  26.715 127.187 26.805 127.457 ;
     RECT  29.415 127.187 29.505 127.457 ;
     RECT  32.115 127.187 32.205 127.457 ;
     RECT  34.815 127.187 34.905 127.457 ;
     RECT  37.515 127.187 37.605 127.457 ;
     RECT  40.215 127.187 40.305 127.457 ;
     RECT  42.915 127.187 43.005 127.457 ;
     RECT  45.615 127.187 45.705 127.457 ;
     RECT  48.315 127.187 48.405 127.457 ;
     RECT  51.015 127.187 51.105 127.457 ;
     RECT  53.715 127.187 53.805 127.457 ;
     RECT  56.415 127.187 56.505 127.457 ;
     RECT  59.115 127.187 59.205 127.457 ;
     RECT  61.815 127.187 61.905 127.457 ;
     RECT  64.515 127.187 64.605 127.457 ;
     RECT  67.215 127.187 67.305 127.457 ;
     RECT  69.915 127.187 70.005 127.457 ;
     RECT  72.615 127.187 72.705 127.457 ;
     RECT  75.315 127.187 75.405 127.457 ;
     RECT  78.015 127.187 78.105 127.457 ;
     RECT  80.715 127.187 80.805 127.457 ;
     RECT  83.415 127.187 83.505 127.457 ;
     RECT  86.115 127.187 86.205 127.457 ;
     RECT  88.815 127.187 88.905 127.457 ;
     RECT  91.515 127.187 91.605 127.457 ;
     RECT  94.215 127.187 94.305 127.457 ;
     RECT  96.915 127.187 97.005 127.457 ;
     RECT  99.615 127.187 99.705 127.457 ;
     RECT  102.315 127.187 102.405 127.457 ;
     RECT  105.015 127.187 105.105 127.457 ;
     RECT  107.715 127.187 107.805 127.457 ;
     RECT  110.415 127.187 110.505 127.457 ;
     RECT  113.115 127.187 113.205 127.457 ;
     RECT  115.815 127.187 115.905 127.457 ;
     RECT  118.515 127.187 118.605 127.457 ;
     RECT  121.215 127.187 121.305 127.457 ;
     RECT  123.915 127.187 124.005 127.457 ;
     RECT  126.615 127.187 126.705 127.457 ;
     RECT  129.315 127.187 129.405 127.457 ;
     RECT  132.015 127.187 132.105 127.457 ;
     RECT  134.715 127.187 134.805 127.457 ;
     RECT  137.415 127.187 137.505 127.457 ;
     RECT  140.115 127.187 140.205 127.457 ;
     RECT  142.815 127.187 142.905 127.457 ;
     RECT  145.515 127.187 145.605 127.457 ;
     RECT  148.215 127.187 148.305 127.457 ;
     RECT  150.915 127.187 151.005 127.457 ;
     RECT  153.615 127.187 153.705 127.457 ;
     RECT  156.315 127.187 156.405 127.457 ;
     RECT  159.015 127.187 159.105 127.457 ;
     RECT  161.715 127.187 161.805 127.457 ;
     RECT  164.415 127.187 164.505 127.457 ;
     RECT  167.115 127.187 167.205 127.457 ;
     RECT  169.815 127.187 169.905 127.457 ;
     RECT  172.515 127.187 172.605 127.457 ;
     RECT  175.215 127.187 175.305 127.457 ;
     RECT  177.915 127.187 178.005 127.457 ;
     RECT  180.615 127.187 180.705 127.457 ;
     RECT  183.315 127.187 183.405 127.457 ;
     RECT  186.015 127.187 186.105 127.457 ;
     RECT  188.715 127.187 188.805 127.457 ;
     RECT  191.415 127.187 191.505 127.457 ;
     RECT  194.115 127.187 194.205 127.457 ;
     RECT  196.815 127.187 196.905 127.457 ;
     RECT  199.515 127.187 199.605 127.457 ;
     RECT  202.215 127.187 202.305 127.457 ;
     RECT  204.915 127.187 205.005 127.457 ;
     RECT  207.615 127.187 207.705 127.457 ;
     RECT  210.315 127.187 210.405 127.457 ;
     RECT  213.015 127.187 213.105 127.457 ;
     RECT  215.715 127.187 215.805 127.457 ;
     RECT  218.415 127.187 218.505 127.457 ;
     RECT  221.115 127.187 221.205 127.457 ;
     RECT  223.815 127.187 223.905 127.457 ;
     RECT  226.515 127.187 226.605 127.457 ;
     RECT  229.215 127.187 229.305 127.457 ;
     RECT  231.915 127.187 232.005 127.457 ;
     RECT  234.615 127.187 234.705 127.457 ;
     RECT  237.315 127.187 237.405 127.457 ;
     RECT  240.015 127.187 240.105 127.457 ;
     RECT  242.715 127.187 242.805 127.457 ;
     RECT  245.415 127.187 245.505 127.457 ;
     RECT  248.115 127.187 248.205 127.457 ;
     RECT  250.815 127.187 250.905 127.457 ;
     RECT  253.515 127.187 253.605 127.457 ;
     RECT  256.215 127.187 256.305 127.457 ;
    LAYER M4 ;
     RECT  0.084 26.352 0.133 26.376 ;
     RECT  0.06 26.376 0.133 26.496 ;
     RECT  0.084 26.496 0.133 26.52 ;
     RECT  0.06 26.52 0.133 26.64 ;
     RECT  0.084 26.64 0.133 26.664 ;
     RECT  0.06 26.664 0.133 26.784 ;
     RECT  0.084 26.784 0.133 26.808 ;
     RECT  0.06 26.808 0.133 26.928 ;
     RECT  0.084 26.928 0.133 26.952 ;
     RECT  0.06 26.952 0.133 27.072 ;
     RECT  0.084 27.072 0.133 27.096 ;
     RECT  0.06 27.096 0.133 27.216 ;
     RECT  0.084 27.216 0.133 27.24 ;
     RECT  0.06 27.24 0.133 27.36 ;
     RECT  0.084 27.36 0.133 27.384 ;
     RECT  0.06 27.384 0.133 27.504 ;
     RECT  0.084 27.504 0.133 27.528 ;
     RECT  0.06 27.528 0.133 27.648 ;
     RECT  0.084 27.648 0.133 27.672 ;
     RECT  0.06 27.672 0.133 27.792 ;
     RECT  0.084 27.792 0.133 27.816 ;
     RECT  0.06 27.816 0.133 27.936 ;
     RECT  0.084 27.936 0.133 27.96 ;
     RECT  0.06 27.96 0.133 28.08 ;
     RECT  0.084 28.08 0.133 28.104 ;
     RECT  0.06 28.104 0.133 28.224 ;
     RECT  0.084 28.224 0.133 28.248 ;
     RECT  0.06 28.248 0.133 28.368 ;
     RECT  0.084 28.368 0.133 28.392 ;
     RECT  0.06 28.392 0.133 28.512 ;
     RECT  0.084 28.512 0.133 28.536 ;
     RECT  0.084 33.264 0.137 33.288 ;
     RECT  0.06 33.288 0.137 33.408 ;
     RECT  0.084 33.408 0.137 33.432 ;
     RECT  0.06 33.432 0.137 33.552 ;
     RECT  0.084 33.552 0.137 33.576 ;
     RECT  0.06 33.576 0.137 33.696 ;
     RECT  0.084 33.696 0.137 33.72 ;
     RECT  0.06 33.72 0.137 33.84 ;
     RECT  0.084 33.84 0.137 33.864 ;
     RECT  0.06 33.864 0.137 33.984 ;
     RECT  0.084 33.984 0.137 34.008 ;
     RECT  0.06 34.008 0.137 34.128 ;
     RECT  0.084 34.128 0.137 34.152 ;
     RECT  0.06 34.152 0.137 34.272 ;
     RECT  0.084 34.272 0.137 34.296 ;
     RECT  0.06 34.296 0.137 34.416 ;
     RECT  0.084 34.416 0.137 34.44 ;
     RECT  0.06 34.44 0.137 34.56 ;
     RECT  0.084 34.56 0.137 34.584 ;
     RECT  0.06 34.584 0.137 34.704 ;
     RECT  0.084 34.704 0.137 34.728 ;
     RECT  0.06 34.728 0.137 34.848 ;
     RECT  0.084 34.848 0.137 34.872 ;
     RECT  0.06 34.872 0.137 34.992 ;
     RECT  0.084 34.992 0.137 35.016 ;
     RECT  0.06 35.016 0.137 35.136 ;
     RECT  0.084 35.136 0.137 35.16 ;
     RECT  0.06 35.16 0.137 35.28 ;
     RECT  0.084 35.28 0.137 35.304 ;
     RECT  0.06 35.304 0.137 35.424 ;
     RECT  0.084 35.424 0.137 35.448 ;
     RECT  0.06 35.448 0.137 35.568 ;
     RECT  0.084 35.568 0.137 35.592 ;
     RECT  0.06 35.592 0.137 35.712 ;
     RECT  0.084 35.712 0.137 35.736 ;
     RECT  0.06 35.736 0.137 35.856 ;
     RECT  0.084 35.856 0.137 35.88 ;
     RECT  0.06 35.88 0.137 36 ;
     RECT  0.084 36 0.137 36.024 ;
     RECT  0.06 36.024 0.137 36.144 ;
     RECT  0.084 36.144 0.137 36.168 ;
     RECT  0.06 36.168 0.137 36.288 ;
     RECT  0.084 36.288 0.137 36.312 ;
     RECT  0.06 36.312 0.137 36.432 ;
     RECT  0.084 36.432 0.137 36.456 ;
     RECT  0.06 36.456 0.137 36.576 ;
     RECT  0.084 36.576 0.137 36.6 ;
     RECT  0.06 36.6 0.137 36.72 ;
     RECT  0.084 36.72 0.137 36.744 ;
     RECT  0.06 36.744 0.137 36.864 ;
     RECT  0.084 36.864 0.137 36.888 ;
     RECT  0.06 36.888 0.137 37.008 ;
     RECT  0.084 37.008 0.137 37.032 ;
     RECT  0.06 37.032 0.137 37.152 ;
     RECT  0.084 37.152 0.137 37.176 ;
     RECT  0.06 37.176 0.137 37.296 ;
     RECT  0.084 37.296 0.137 37.32 ;
     RECT  0.06 37.32 0.137 37.44 ;
     RECT  0.084 37.44 0.137 37.464 ;
     RECT  0.06 37.464 0.137 37.584 ;
     RECT  0.084 37.584 0.137 37.608 ;
     RECT  0.06 37.608 0.137 37.728 ;
     RECT  0.084 37.728 0.137 37.752 ;
     RECT  0.133 26.304 2.408 28.536 ;
     RECT  0.137 33.312 2.408 37.752 ;
     RECT  2.408 2.148 2.512 127.452 ;
     RECT  2.512 2.418 2.704 127.182 ;
     RECT  2.704 32.784 2.845 37.752 ;
     RECT  2.704 28.224 2.873 28.536 ;
     RECT  2.845 33.312 2.873 37.752 ;
     RECT  2.873 28.464 2.909 28.536 ;
     RECT  2.704 26.304 2.945 27.144 ;
     RECT  2.909 28.512 3.341 28.536 ;
     RECT  4.021 30.24 4.417 30.264 ;
     RECT  4.129 32.448 4.46 32.472 ;
     RECT  2.873 33.552 4.46 37.752 ;
     RECT  4.46 32.448 4.501 37.752 ;
     RECT  2.945 26.64 4.813 27.144 ;
     RECT  4.813 26.64 4.957 27.48 ;
     RECT  4.957 26.592 5.065 27.48 ;
     RECT  5.065 26.352 5.108 27.48 ;
     RECT  4.981 28.464 5.108 28.488 ;
     RECT  4.417 30.24 5.108 30.552 ;
     RECT  4.501 31.872 5.108 37.752 ;
     RECT  5.108 2.148 5.212 127.452 ;
     RECT  5.212 2.418 5.404 127.182 ;
     RECT  5.404 26.352 5.573 30.216 ;
     RECT  5.404 31.536 5.75 37.608 ;
     RECT  5.573 26.592 5.753 30.216 ;
     RECT  5.75 31.584 6.365 37.608 ;
     RECT  5.753 27.312 6.545 30.216 ;
     RECT  6.545 27.312 6.563 29.544 ;
     RECT  6.365 32.208 6.649 37.608 ;
     RECT  6.563 27.312 6.829 29.256 ;
     RECT  6.829 26.736 7.808 29.256 ;
     RECT  7.141 30.576 7.808 30.6 ;
     RECT  6.649 32.208 7.808 38.184 ;
     RECT  7.808 2.148 7.912 127.452 ;
     RECT  7.912 2.418 8.104 127.182 ;
     RECT  8.104 27.168 8.243 28.488 ;
     RECT  8.104 29.616 8.243 29.64 ;
     RECT  8.243 27.312 9.116 28.488 ;
     RECT  8.104 31.344 9.145 38.184 ;
     RECT  9.116 27.312 9.245 28.824 ;
     RECT  9.145 32.304 9.349 38.184 ;
     RECT  9.349 32.304 9.433 38.232 ;
     RECT  9.245 27.36 9.565 28.824 ;
     RECT  9.565 27.36 9.836 28.968 ;
     RECT  9.836 27.36 10.508 29.544 ;
     RECT  9.433 32.304 10.508 38.04 ;
     RECT  10.508 2.148 10.612 127.452 ;
     RECT  10.612 2.418 10.804 127.182 ;
     RECT  10.804 32.448 11.837 38.184 ;
     RECT  11.837 32.448 12.053 37.992 ;
     RECT  10.804 28.416 13.208 29.016 ;
     RECT  12.053 32.448 13.208 37.944 ;
     RECT  13.208 2.148 13.312 127.452 ;
     RECT  13.312 2.418 13.504 127.182 ;
     RECT  13.504 30.816 13.781 31.272 ;
     RECT  13.781 31.248 14.821 31.272 ;
     RECT  14.821 31.152 14.861 31.272 ;
     RECT  13.504 32.448 14.861 38.136 ;
     RECT  14.861 32.448 15.793 37.992 ;
     RECT  13.504 28.416 15.908 29.016 ;
     RECT  14.861 31.152 15.908 31.176 ;
     RECT  15.793 32.304 15.908 37.992 ;
     RECT  15.908 2.148 16.012 127.452 ;
     RECT  16.012 2.418 16.204 127.182 ;
     RECT  16.204 28.416 18.608 29.016 ;
     RECT  16.204 31.152 18.608 31.176 ;
     RECT  16.204 32.304 18.608 37.992 ;
     RECT  18.608 2.148 18.712 127.452 ;
     RECT  18.712 2.418 18.904 127.182 ;
     RECT  18.904 32.832 21.061 37.992 ;
     RECT  18.904 31.248 21.121 31.272 ;
     RECT  18.904 28.416 21.308 29.016 ;
     RECT  21.121 31.152 21.308 31.272 ;
     RECT  21.061 32.304 21.308 37.992 ;
     RECT  21.308 2.148 21.412 127.452 ;
     RECT  21.412 2.418 21.604 127.182 ;
     RECT  21.604 32.304 22.853 38.136 ;
     RECT  21.604 28.416 24.008 29.016 ;
     RECT  21.604 31.152 24.008 31.176 ;
     RECT  22.853 32.304 24.008 37.992 ;
     RECT  24.008 2.148 24.112 127.452 ;
     RECT  24.112 2.418 24.304 127.182 ;
     RECT  24.304 30.336 25.229 31.224 ;
     RECT  25.229 31.152 25.585 31.224 ;
     RECT  24.304 32.208 25.585 37.992 ;
     RECT  24.304 28.416 26.708 29.016 ;
     RECT  26.521 30.144 26.708 30.168 ;
     RECT  25.585 31.152 26.708 37.992 ;
     RECT  26.708 2.148 26.812 127.452 ;
     RECT  26.812 2.418 27.004 127.182 ;
     RECT  27.004 27.888 27.155 37.992 ;
     RECT  27.155 27.888 27.181 29.64 ;
     RECT  27.181 27.888 27.749 29.352 ;
     RECT  27.749 28.416 29.257 29.352 ;
     RECT  29.257 28.416 29.365 29.544 ;
     RECT  29.365 28.416 29.408 29.592 ;
     RECT  27.155 31.104 29.408 37.992 ;
     RECT  29.408 2.148 29.512 127.452 ;
     RECT  29.512 2.418 29.704 127.182 ;
     RECT  29.704 28.272 30.413 38.184 ;
     RECT  30.413 31.152 30.809 38.184 ;
     RECT  30.413 28.272 31.201 29.496 ;
     RECT  30.809 31.152 31.561 37.896 ;
     RECT  31.201 27.792 31.813 29.496 ;
     RECT  31.813 27.168 32.065 29.496 ;
     RECT  31.561 30.576 32.065 37.896 ;
     RECT  32.065 27.168 32.108 37.896 ;
     RECT  32.108 2.148 32.212 127.452 ;
     RECT  32.212 2.418 32.404 127.182 ;
     RECT  32.404 27.696 32.819 37.704 ;
     RECT  32.819 30.432 33.185 37.704 ;
     RECT  32.819 27.696 33.581 29.304 ;
     RECT  33.581 28.176 34.808 29.304 ;
     RECT  33.185 30.672 34.808 37.704 ;
     RECT  34.808 2.148 34.912 127.452 ;
     RECT  34.912 2.418 35.104 127.182 ;
     RECT  35.104 28.416 35.692 39.192 ;
     RECT  35.692 28.416 35.813 38.952 ;
     RECT  35.104 46.176 35.939 46.824 ;
     RECT  36.097 44.448 36.467 44.472 ;
     RECT  35.813 30.816 36.497 38.952 ;
     RECT  36.497 30.96 36.673 38.952 ;
     RECT  35.939 46.176 36.709 46.248 ;
     RECT  36.709 46.128 36.997 46.248 ;
     RECT  35.813 28.416 37.508 29.736 ;
     RECT  36.673 30.96 37.508 39.048 ;
     RECT  36.097 41.04 37.508 41.064 ;
     RECT  36.668 44.544 37.508 44.568 ;
     RECT  36.997 45.6 37.508 46.248 ;
     RECT  36.668 47.808 37.508 47.832 ;
     RECT  37.508 2.148 37.612 127.452 ;
     RECT  37.612 2.418 37.804 127.182 ;
     RECT  37.804 44.064 39.337 44.856 ;
     RECT  39.337 44.016 39.517 44.856 ;
     RECT  37.804 28.416 40.208 37.704 ;
     RECT  40.208 2.148 40.312 37.812 ;
     RECT  40.208 111.768 40.312 127.452 ;
     RECT  40.312 111.768 40.4 127.182 ;
     RECT  40.312 2.418 40.504 37.704 ;
     RECT  40.4 111.498 40.504 127.182 ;
     RECT  40.504 28.416 40.745 37.704 ;
     RECT  40.745 30.576 41.033 37.704 ;
     RECT  41.033 30.72 41.219 37.704 ;
     RECT  40.745 28.416 41.315 29.352 ;
     RECT  37.804 46.176 41.605 46.296 ;
     RECT  37.804 47.616 41.605 47.928 ;
     RECT  41.605 46.176 41.641 47.928 ;
     RECT  39.517 44.016 42.001 44.952 ;
     RECT  41.641 45.984 42.001 47.928 ;
     RECT  41.315 28.416 42.908 29.304 ;
     RECT  41.219 30.864 42.908 37.704 ;
     RECT  42.001 44.016 42.937 47.928 ;
     RECT  42.908 2.148 43.012 37.812 ;
     RECT  42.908 111.768 43.012 127.452 ;
     RECT  42.937 43.968 43.081 47.928 ;
     RECT  43.012 111.768 43.1 127.182 ;
     RECT  43.012 2.418 43.204 37.704 ;
     RECT  43.1 111.498 43.204 127.182 ;
     RECT  42.709 42.432 43.272 42.456 ;
     RECT  43.081 43.968 43.272 48.024 ;
     RECT  43.204 28.416 43.517 37.704 ;
     RECT  43.272 42.432 44.669 106.11 ;
     RECT  43.517 28.416 45.445 29.832 ;
     RECT  43.517 30.864 45.445 37.704 ;
     RECT  45.445 28.416 45.608 37.704 ;
     RECT  45.608 2.148 45.712 37.812 ;
     RECT  45.608 111.768 45.712 127.452 ;
     RECT  45.712 111.768 45.8 127.182 ;
     RECT  45.712 2.418 45.904 37.704 ;
     RECT  45.8 111.498 45.904 127.182 ;
     RECT  45.904 29.28 47.077 37.704 ;
     RECT  47.077 29.232 47.617 37.704 ;
     RECT  47.617 28.656 47.905 37.704 ;
     RECT  47.905 28.512 48.308 37.704 ;
     RECT  48.308 2.148 48.412 37.812 ;
     RECT  48.308 111.768 48.412 127.452 ;
     RECT  48.412 111.768 48.5 127.182 ;
     RECT  48.412 2.418 48.604 37.704 ;
     RECT  48.5 111.498 48.604 127.182 ;
     RECT  48.604 28.512 48.701 29.88 ;
     RECT  48.701 29.04 49.777 29.88 ;
     RECT  48.604 30.912 49.777 37.704 ;
     RECT  49.777 29.04 51.008 37.704 ;
     RECT  51.008 2.148 51.112 37.812 ;
     RECT  51.008 111.768 51.112 127.452 ;
     RECT  51.112 111.768 51.2 127.182 ;
     RECT  51.112 2.418 51.304 37.704 ;
     RECT  51.2 111.498 51.304 127.182 ;
     RECT  51.304 29.28 52.156 37.704 ;
     RECT  52.156 30.72 52.165 37.704 ;
     RECT  52.156 29.28 52.481 29.688 ;
     RECT  52.481 29.28 53.708 29.304 ;
     RECT  52.165 30.864 53.708 37.704 ;
     RECT  53.708 2.148 53.812 37.812 ;
     RECT  53.708 111.768 53.812 127.452 ;
     RECT  53.812 111.768 53.9 127.182 ;
     RECT  53.812 2.418 54.004 37.704 ;
     RECT  53.9 111.498 54.004 127.182 ;
     RECT  54.004 29.28 55.321 29.304 ;
     RECT  54.004 30.768 55.321 37.704 ;
     RECT  55.321 29.28 55.357 37.704 ;
     RECT  55.357 28.464 55.825 37.704 ;
     RECT  55.825 28.416 56.408 37.704 ;
     RECT  56.408 2.148 56.512 37.812 ;
     RECT  56.408 111.768 56.512 127.452 ;
     RECT  56.512 111.768 56.6 127.182 ;
     RECT  56.512 2.418 56.704 37.704 ;
     RECT  56.6 111.498 56.704 127.182 ;
     RECT  56.704 28.272 57.733 28.296 ;
     RECT  56.704 29.28 57.733 37.704 ;
     RECT  57.733 28.272 58.453 37.704 ;
     RECT  58.453 27.312 59.065 37.704 ;
     RECT  59.065 26.592 59.108 37.704 ;
     RECT  59.108 2.148 59.212 37.812 ;
     RECT  59.108 111.768 59.212 127.452 ;
     RECT  59.212 111.768 59.3 127.182 ;
     RECT  59.212 2.418 59.404 37.704 ;
     RECT  59.3 111.498 59.404 127.182 ;
     RECT  59.404 26.592 59.429 26.76 ;
     RECT  59.404 28.176 59.555 37.704 ;
     RECT  59.555 28.176 60.473 29.592 ;
     RECT  60.473 28.224 60.757 29.592 ;
     RECT  60.433 25.68 60.901 25.704 ;
     RECT  59.429 26.736 60.901 26.76 ;
     RECT  60.757 28.224 61.1 30.072 ;
     RECT  59.555 31.104 61.1 37.704 ;
     RECT  60.901 25.68 61.153 26.76 ;
     RECT  61.153 25.68 61.441 27.192 ;
     RECT  61.441 25.44 61.621 27.192 ;
     RECT  61.621 25.2 61.808 27.192 ;
     RECT  61.1 28.224 61.808 37.704 ;
     RECT  61.808 2.148 61.912 37.812 ;
     RECT  61.808 111.768 61.912 127.452 ;
     RECT  61.912 111.768 62 127.182 ;
     RECT  61.912 2.418 62.104 37.704 ;
     RECT  62 111.498 62.104 127.182 ;
     RECT  62.104 25.2 62.597 25.752 ;
     RECT  62.597 25.2 62.669 25.56 ;
     RECT  62.104 27.12 62.849 37.704 ;
     RECT  62.669 25.2 63.353 25.224 ;
     RECT  62.849 27.312 63.389 37.704 ;
     RECT  63.961 26.208 64.501 26.232 ;
     RECT  63.389 27.696 64.501 37.704 ;
     RECT  64.501 26.208 64.508 37.704 ;
     RECT  64.508 2.148 64.612 37.812 ;
     RECT  64.508 111.768 64.612 127.452 ;
     RECT  64.612 111.768 64.7 127.182 ;
     RECT  64.612 2.418 64.804 37.704 ;
     RECT  64.7 111.498 64.804 127.182 ;
     RECT  64.804 27.888 64.931 37.704 ;
     RECT  64.804 26.64 64.979 26.808 ;
     RECT  64.979 26.784 65.225 26.808 ;
     RECT  64.931 28.512 65.621 37.704 ;
     RECT  65.621 28.656 67.208 37.704 ;
     RECT  67.208 2.148 67.312 37.812 ;
     RECT  67.208 111.768 67.312 127.452 ;
     RECT  67.312 111.768 67.4 127.182 ;
     RECT  67.312 2.418 67.504 37.704 ;
     RECT  67.4 111.498 67.504 127.182 ;
     RECT  67.504 30.672 67.619 37.704 ;
     RECT  67.504 28.464 68.497 28.488 ;
     RECT  68.497 28.464 68.677 29.4 ;
     RECT  67.619 31.104 68.677 37.704 ;
     RECT  68.677 28.464 68.897 37.704 ;
     RECT  68.897 29.328 69.908 37.704 ;
     RECT  69.908 2.148 70.012 37.812 ;
     RECT  69.908 111.768 70.012 127.452 ;
     RECT  70.012 111.768 70.1 127.182 ;
     RECT  70.012 2.418 70.204 37.704 ;
     RECT  70.1 111.498 70.204 127.182 ;
     RECT  70.204 29.376 71.057 37.704 ;
     RECT  71.057 29.616 71.201 37.704 ;
     RECT  71.305 28.272 72.169 28.296 ;
     RECT  71.201 29.616 72.169 29.64 ;
     RECT  71.201 30.96 72.205 37.704 ;
     RECT  72.169 28.272 72.277 29.64 ;
     RECT  72.205 30.672 72.277 37.704 ;
     RECT  72.277 28.272 72.608 37.704 ;
     RECT  72.608 2.148 72.712 37.812 ;
     RECT  72.608 111.768 72.712 127.452 ;
     RECT  72.712 111.768 72.8 127.182 ;
     RECT  72.712 2.418 72.904 37.704 ;
     RECT  72.8 111.498 72.904 127.182 ;
     RECT  72.904 27.792 73.475 37.704 ;
     RECT  73.475 28.272 73.829 37.704 ;
     RECT  73.829 28.272 74.153 29.88 ;
     RECT  74.153 29.76 74.941 29.88 ;
     RECT  73.829 31.008 74.941 37.704 ;
     RECT  74.153 28.272 75.308 28.536 ;
     RECT  74.941 29.76 75.308 37.704 ;
     RECT  75.308 2.148 75.412 37.812 ;
     RECT  75.308 111.768 75.412 127.452 ;
     RECT  75.412 111.768 75.5 127.182 ;
     RECT  75.412 2.418 75.604 37.704 ;
     RECT  75.5 111.498 75.604 127.182 ;
     RECT  75.604 28.944 78.008 29.784 ;
     RECT  75.604 31.104 78.008 32.328 ;
     RECT  75.604 33.936 78.008 37.704 ;
     RECT  78.008 2.148 78.112 37.812 ;
     RECT  78.008 111.768 78.112 127.452 ;
     RECT  78.112 111.768 78.2 127.182 ;
     RECT  78.112 2.418 78.304 37.704 ;
     RECT  78.2 111.498 78.304 127.182 ;
     RECT  80.053 20.064 80.708 20.088 ;
     RECT  78.304 28.944 80.708 29.784 ;
     RECT  78.304 31.104 80.708 32.328 ;
     RECT  78.304 33.936 80.708 37.704 ;
     RECT  80.708 2.148 80.812 37.812 ;
     RECT  80.708 111.768 80.812 127.452 ;
     RECT  80.812 111.768 80.9 127.182 ;
     RECT  80.812 2.418 81.004 37.704 ;
     RECT  80.9 111.498 81.004 127.182 ;
     RECT  44.669 43.2 81.144 106.11 ;
     RECT  81.144 43.68 81.216 48.024 ;
     RECT  82.033 24.912 82.316 24.936 ;
     RECT  82.316 24.864 82.403 24.936 ;
     RECT  82.357 17.616 83.408 17.64 ;
     RECT  81.004 20.064 83.408 20.088 ;
     RECT  82.403 24.912 83.408 24.936 ;
     RECT  81.004 29.76 83.408 29.784 ;
     RECT  81.004 31.104 83.408 32.328 ;
     RECT  81.004 33.936 83.408 37.704 ;
     RECT  83.408 2.148 83.512 37.812 ;
     RECT  83.408 111.768 83.512 127.452 ;
     RECT  83.512 111.768 83.6 127.182 ;
     RECT  83.512 2.418 83.704 37.704 ;
     RECT  83.6 111.498 83.704 127.182 ;
     RECT  83.704 31.104 84.908 32.328 ;
     RECT  84.908 31.104 84.949 32.424 ;
     RECT  83.704 33.936 84.949 37.704 ;
     RECT  84.949 31.104 84.995 37.704 ;
     RECT  83.704 17.616 86.108 17.64 ;
     RECT  83.704 20.064 86.108 20.136 ;
     RECT  83.704 24.912 86.108 24.936 ;
     RECT  83.704 29.76 86.108 29.784 ;
     RECT  84.995 31.2 86.108 37.704 ;
     RECT  86.108 2.148 86.212 37.812 ;
     RECT  86.108 111.768 86.212 127.452 ;
     RECT  86.212 111.768 86.3 127.182 ;
     RECT  86.212 2.418 86.404 37.704 ;
     RECT  86.3 111.498 86.404 127.182 ;
     RECT  81.216 43.68 86.825 44.184 ;
     RECT  86.404 20.064 86.915 20.136 ;
     RECT  86.825 44.16 87.005 44.184 ;
     RECT  86.404 2.592 87.155 3.432 ;
     RECT  87.155 3.408 88.808 3.432 ;
     RECT  86.404 17.616 88.808 17.64 ;
     RECT  86.915 20.112 88.808 20.136 ;
     RECT  86.404 24.912 88.808 24.936 ;
     RECT  86.404 29.76 88.808 29.784 ;
     RECT  86.404 31.2 88.808 37.704 ;
     RECT  88.808 2.148 88.912 127.452 ;
     RECT  88.912 2.148 89.104 127.182 ;
     RECT  89.017 0.096 89.603 0.12 ;
     RECT  89.161 1.728 89.813 1.8 ;
     RECT  89.813 1.776 90.029 1.8 ;
     RECT  89.104 17.616 90.389 17.64 ;
     RECT  90.205 2.88 90.613 2.904 ;
     RECT  90.613 2.592 91.508 2.904 ;
     RECT  90.681 4.128 91.508 4.152 ;
     RECT  91.141 14.928 91.508 14.952 ;
     RECT  90.709 17.568 91.508 17.592 ;
     RECT  89.104 20.112 91.508 20.136 ;
     RECT  89.104 24.912 91.508 24.936 ;
     RECT  89.104 29.76 91.508 29.784 ;
     RECT  89.104 31.2 91.508 37.704 ;
     RECT  91.508 2.148 91.612 127.452 ;
     RECT  91.612 2.418 91.804 127.182 ;
     RECT  91.804 4.128 94.208 4.152 ;
     RECT  91.804 14.928 94.208 14.952 ;
     RECT  91.804 24.912 94.208 24.936 ;
     RECT  91.804 29.76 94.208 29.784 ;
     RECT  91.804 31.2 94.208 37.704 ;
     RECT  94.208 2.148 94.312 127.452 ;
     RECT  94.312 2.418 94.504 127.182 ;
     RECT  94.504 14.928 96.505 14.952 ;
     RECT  94.504 4.128 96.908 4.152 ;
     RECT  96.505 14.832 96.908 14.952 ;
     RECT  94.504 24.912 96.908 24.936 ;
     RECT  94.504 29.76 96.908 29.784 ;
     RECT  94.504 31.2 96.908 37.704 ;
     RECT  96.908 2.148 97.012 127.452 ;
     RECT  97.012 2.418 97.204 127.182 ;
     RECT  97.204 24.912 99.608 24.936 ;
     RECT  97.204 29.76 99.608 29.784 ;
     RECT  97.204 31.2 99.608 37.704 ;
     RECT  99.608 2.148 99.712 127.452 ;
     RECT  99.712 2.418 99.904 127.182 ;
     RECT  99.904 31.2 100.289 37.704 ;
     RECT  100.289 31.2 101.756 32.328 ;
     RECT  100.289 33.648 101.756 37.704 ;
     RECT  99.904 24.912 102.308 24.936 ;
     RECT  99.904 29.76 102.308 29.784 ;
     RECT  101.756 31.2 102.308 37.704 ;
     RECT  101.797 39.552 102.308 39.576 ;
     RECT  102.308 2.148 102.412 127.452 ;
     RECT  102.412 2.418 102.604 127.182 ;
     RECT  102.604 29.76 105.008 29.784 ;
     RECT  102.604 31.2 105.008 32.472 ;
     RECT  102.604 33.648 105.008 37.704 ;
     RECT  102.604 39.456 105.008 39.48 ;
     RECT  105.008 2.148 105.112 127.452 ;
     RECT  105.112 2.418 105.304 127.182 ;
     RECT  105.304 39.456 107.593 39.48 ;
     RECT  105.304 29.76 107.708 29.784 ;
     RECT  105.304 31.2 107.708 32.472 ;
     RECT  105.304 33.648 107.708 37.704 ;
     RECT  107.593 39.456 107.708 39.576 ;
     RECT  107.708 2.148 107.812 127.452 ;
     RECT  107.812 2.418 108.004 127.182 ;
     RECT  108.004 29.76 110.408 29.784 ;
     RECT  108.004 31.2 110.408 32.328 ;
     RECT  108.004 33.648 110.408 37.704 ;
     RECT  108.004 39.552 110.408 39.576 ;
     RECT  110.408 2.148 110.512 127.452 ;
     RECT  110.512 2.418 110.704 127.182 ;
     RECT  110.704 33.648 110.819 37.944 ;
     RECT  110.704 31.2 110.981 32.472 ;
     RECT  110.704 29.76 113.108 29.784 ;
     RECT  110.981 31.2 113.108 32.328 ;
     RECT  110.819 33.936 113.108 37.944 ;
     RECT  110.704 39.552 113.108 39.576 ;
     RECT  112.981 42.192 113.108 42.216 ;
     RECT  113.108 2.148 113.212 127.452 ;
     RECT  113.212 2.418 113.404 127.182 ;
     RECT  113.404 43.584 113.603 43.608 ;
     RECT  113.404 45.12 113.603 45.144 ;
     RECT  113.404 41.568 113.717 41.784 ;
     RECT  113.404 39.024 113.987 39.912 ;
     RECT  113.404 33.936 114.469 37.944 ;
     RECT  113.987 39.024 114.469 39.576 ;
     RECT  113.717 41.76 114.469 41.784 ;
     RECT  114.541 44.64 114.613 44.664 ;
     RECT  113.404 31.2 114.617 32.472 ;
     RECT  114.469 41.76 114.805 41.88 ;
     RECT  114.805 41.76 114.973 42.792 ;
     RECT  114.613 44.064 114.973 44.664 ;
     RECT  113.404 29.76 115.808 29.784 ;
     RECT  114.617 31.2 115.808 32.328 ;
     RECT  114.469 33.936 115.808 39.576 ;
     RECT  115.513 40.608 115.808 40.632 ;
     RECT  114.973 41.76 115.808 44.664 ;
     RECT  115.621 45.744 115.808 46.152 ;
     RECT  115.621 48.384 115.808 48.408 ;
     RECT  115.808 2.148 115.912 127.452 ;
     RECT  115.912 2.418 116.104 127.182 ;
     RECT  116.104 31.2 116.237 32.328 ;
     RECT  116.104 33.936 116.627 43.752 ;
     RECT  116.627 42.672 116.669 43.752 ;
     RECT  116.237 31.2 116.705 32.28 ;
     RECT  116.104 45.744 117.097 46.008 ;
     RECT  116.669 42.816 117.397 43.752 ;
     RECT  116.627 33.936 117.425 41.592 ;
     RECT  117.425 39.696 117.443 41.592 ;
     RECT  117.097 45.696 117.445 46.008 ;
     RECT  117.445 44.976 117.532 46.008 ;
     RECT  117.532 45.696 117.565 46.008 ;
     RECT  117.565 45.696 117.637 46.056 ;
     RECT  116.104 47.328 117.637 47.352 ;
     RECT  117.397 42.816 117.745 43.944 ;
     RECT  117.637 45.696 118.069 47.352 ;
     RECT  117.443 40.656 118.105 41.592 ;
     RECT  117.745 42.576 118.105 43.944 ;
     RECT  118.105 40.656 118.249 43.944 ;
     RECT  118.249 40.656 118.465 44.664 ;
     RECT  116.104 29.76 118.508 29.784 ;
     RECT  116.705 31.728 118.508 32.28 ;
     RECT  117.425 33.936 118.508 38.712 ;
     RECT  118.465 39.84 118.508 44.664 ;
     RECT  118.069 45.696 118.508 47.4 ;
     RECT  117.925 48.768 118.508 48.792 ;
     RECT  118.508 2.148 118.612 127.452 ;
     RECT  118.612 2.418 118.804 127.182 ;
     RECT  118.804 41.184 119.603 47.64 ;
     RECT  118.804 29.76 119.621 29.784 ;
     RECT  119.603 41.184 119.765 47.4 ;
     RECT  119.765 41.184 120.085 41.928 ;
     RECT  119.765 42.96 120.901 47.4 ;
     RECT  118.804 48.768 120.901 48.792 ;
     RECT  120.085 40.992 120.956 41.928 ;
     RECT  120.956 40.656 120.997 41.928 ;
     RECT  120.901 42.96 120.997 48.792 ;
     RECT  118.804 31.728 121.208 32.28 ;
     RECT  118.804 33.936 121.208 39.048 ;
     RECT  120.997 40.656 121.208 48.792 ;
     RECT  121.208 2.148 121.312 127.452 ;
     RECT  121.312 2.418 121.504 127.182 ;
     RECT  121.504 33.936 122.051 47.4 ;
     RECT  122.051 43.632 122.243 44.376 ;
     RECT  122.051 33.936 122.249 42.504 ;
     RECT  122.243 43.824 122.429 44.376 ;
     RECT  122.249 41.232 122.465 42.504 ;
     RECT  121.504 32.448 122.533 32.472 ;
     RECT  121.504 48.528 122.537 48.936 ;
     RECT  122.533 32.304 122.573 32.472 ;
     RECT  122.051 45.408 122.684 47.4 ;
     RECT  122.249 33.936 122.717 40.152 ;
     RECT  122.684 45.408 122.771 47.592 ;
     RECT  122.465 41.376 122.825 42.504 ;
     RECT  122.825 42.48 123.145 42.504 ;
     RECT  122.771 45.408 123.397 47.4 ;
     RECT  122.573 32.304 123.908 32.328 ;
     RECT  122.717 33.936 123.908 38.28 ;
     RECT  122.717 39.744 123.908 40.152 ;
     RECT  122.825 41.376 123.908 41.496 ;
     RECT  123.145 42.48 123.908 42.792 ;
     RECT  122.429 43.824 123.908 44.088 ;
     RECT  123.397 45.12 123.908 47.4 ;
     RECT  122.537 48.912 123.908 48.936 ;
     RECT  123.908 2.148 124.012 127.452 ;
     RECT  124.012 2.418 124.204 127.182 ;
     RECT  124.204 45.6 125.413 48.024 ;
     RECT  124.204 32.304 126.608 32.328 ;
     RECT  124.204 33.84 126.608 37.704 ;
     RECT  126.608 2.148 126.712 37.812 ;
     RECT  126.608 111.768 126.712 127.452 ;
     RECT  126.712 111.768 126.8 127.182 ;
     RECT  126.712 2.418 126.904 37.704 ;
     RECT  126.8 111.498 126.904 127.182 ;
     RECT  125.413 45.216 127.933 48.024 ;
     RECT  124.204 41.376 128.053 41.4 ;
     RECT  126.904 32.304 128.099 32.328 ;
     RECT  124.204 43.968 128.113 43.992 ;
     RECT  127.933 45.024 128.113 48.024 ;
     RECT  126.904 33.84 129.308 37.704 ;
     RECT  129.308 2.148 129.412 37.812 ;
     RECT  129.308 111.768 129.412 127.452 ;
     RECT  129.412 111.768 129.5 127.182 ;
     RECT  129.412 2.418 129.604 37.704 ;
     RECT  129.5 111.498 129.604 127.182 ;
     RECT  128.113 43.968 129.672 48.024 ;
     RECT  129.604 33.936 132.008 37.704 ;
     RECT  132.008 2.148 132.112 37.812 ;
     RECT  132.008 111.768 132.112 127.452 ;
     RECT  132.112 111.768 132.2 127.182 ;
     RECT  132.112 2.418 132.304 37.704 ;
     RECT  132.2 111.498 132.304 127.182 ;
     RECT  132.304 33.936 134.708 37.704 ;
     RECT  134.708 2.148 134.812 37.812 ;
     RECT  134.708 111.768 134.812 127.452 ;
     RECT  134.812 111.768 134.9 127.182 ;
     RECT  134.812 2.418 135.004 37.704 ;
     RECT  134.9 111.498 135.004 127.182 ;
     RECT  135.004 33.936 137.408 37.704 ;
     RECT  137.408 2.148 137.512 37.812 ;
     RECT  137.408 111.768 137.512 127.452 ;
     RECT  137.512 111.768 137.6 127.182 ;
     RECT  137.512 2.418 137.704 37.704 ;
     RECT  137.6 111.498 137.704 127.182 ;
     RECT  137.704 33.936 140.108 37.704 ;
     RECT  140.108 2.148 140.212 37.812 ;
     RECT  140.108 111.768 140.212 127.452 ;
     RECT  140.212 111.768 140.3 127.182 ;
     RECT  140.212 2.418 140.404 37.704 ;
     RECT  140.3 111.498 140.404 127.182 ;
     RECT  140.404 33.936 142.808 37.704 ;
     RECT  142.808 2.148 142.912 37.812 ;
     RECT  142.808 111.768 142.912 127.452 ;
     RECT  142.912 111.768 143 127.182 ;
     RECT  142.912 2.418 143.104 37.704 ;
     RECT  143 111.498 143.104 127.182 ;
     RECT  143.104 33.936 143.561 37.704 ;
     RECT  143.561 33.936 145.508 37.608 ;
     RECT  145.508 2.148 145.612 37.812 ;
     RECT  145.508 111.768 145.612 127.452 ;
     RECT  145.612 111.768 145.7 127.182 ;
     RECT  145.612 2.418 145.804 37.608 ;
     RECT  145.7 111.498 145.804 127.182 ;
     RECT  145.804 33.936 146.621 37.608 ;
     RECT  146.621 33.936 148.208 34.104 ;
     RECT  146.621 35.184 148.208 37.608 ;
     RECT  148.208 2.148 148.312 37.812 ;
     RECT  148.208 111.768 148.312 127.452 ;
     RECT  148.312 111.768 148.4 127.182 ;
     RECT  148.312 2.418 148.504 37.608 ;
     RECT  148.4 111.498 148.504 127.182 ;
     RECT  148.504 34.08 150.908 34.104 ;
     RECT  148.504 35.184 150.908 37.608 ;
     RECT  150.908 2.148 151.012 37.812 ;
     RECT  150.908 111.768 151.012 127.452 ;
     RECT  151.012 111.768 151.1 127.182 ;
     RECT  151.012 2.418 151.204 37.608 ;
     RECT  151.1 111.498 151.204 127.182 ;
     RECT  151.204 34.08 153.608 34.104 ;
     RECT  151.204 35.232 153.608 37.608 ;
     RECT  153.608 2.148 153.712 37.812 ;
     RECT  153.608 111.768 153.712 127.452 ;
     RECT  153.712 111.768 153.8 127.182 ;
     RECT  153.712 2.418 153.904 37.608 ;
     RECT  153.8 111.498 153.904 127.182 ;
     RECT  153.904 35.136 154.505 37.608 ;
     RECT  153.904 34.08 156.308 34.104 ;
     RECT  154.505 35.232 156.308 37.608 ;
     RECT  156.308 2.148 156.412 37.812 ;
     RECT  156.308 111.768 156.412 127.452 ;
     RECT  156.412 111.768 156.5 127.182 ;
     RECT  156.412 2.418 156.604 37.608 ;
     RECT  156.5 111.498 156.604 127.182 ;
     RECT  156.604 34.08 159.008 34.104 ;
     RECT  156.604 35.232 159.008 37.608 ;
     RECT  159.008 2.148 159.112 37.812 ;
     RECT  159.008 111.768 159.112 127.452 ;
     RECT  159.112 111.768 159.2 127.182 ;
     RECT  159.112 2.418 159.304 37.608 ;
     RECT  159.2 111.498 159.304 127.182 ;
     RECT  159.304 34.08 161.708 34.104 ;
     RECT  159.304 35.232 161.708 37.608 ;
     RECT  161.708 2.148 161.812 37.812 ;
     RECT  161.708 111.768 161.812 127.452 ;
     RECT  161.812 111.768 161.9 127.182 ;
     RECT  161.812 2.418 162.004 37.608 ;
     RECT  161.9 111.498 162.004 127.182 ;
     RECT  162.004 35.136 162.497 37.608 ;
     RECT  162.004 34.08 164.408 34.104 ;
     RECT  162.497 35.232 164.408 37.608 ;
     RECT  164.408 2.148 164.512 37.812 ;
     RECT  164.408 111.768 164.512 127.452 ;
     RECT  164.512 111.768 164.6 127.182 ;
     RECT  164.512 2.418 164.704 37.608 ;
     RECT  164.6 111.498 164.704 127.182 ;
     RECT  164.704 34.08 167.108 34.104 ;
     RECT  164.704 35.232 167.108 37.608 ;
     RECT  167.108 2.148 167.212 37.812 ;
     RECT  167.108 111.768 167.212 127.452 ;
     RECT  167.212 111.768 167.3 127.182 ;
     RECT  167.212 2.418 167.404 37.608 ;
     RECT  167.3 111.498 167.404 127.182 ;
     RECT  129.672 43.2 167.544 106.11 ;
     RECT  167.544 43.968 167.616 48.024 ;
     RECT  167.616 43.968 167.753 44.184 ;
     RECT  167.404 34.08 169.808 34.104 ;
     RECT  167.404 35.232 169.808 37.608 ;
     RECT  169.808 2.148 169.912 37.812 ;
     RECT  169.808 111.768 169.912 127.452 ;
     RECT  169.912 111.768 170 127.182 ;
     RECT  169.912 2.418 170.104 37.608 ;
     RECT  170 111.498 170.104 127.182 ;
     RECT  167.753 44.064 170.417 44.184 ;
     RECT  170.104 35.136 170.453 37.608 ;
     RECT  170.104 34.08 172.508 34.104 ;
     RECT  170.453 35.232 172.508 37.608 ;
     RECT  172.508 2.148 172.612 37.812 ;
     RECT  172.508 111.768 172.612 127.452 ;
     RECT  172.612 111.768 172.7 127.182 ;
     RECT  170.417 44.064 172.721 44.088 ;
     RECT  172.612 2.418 172.804 37.608 ;
     RECT  172.7 111.498 172.804 127.182 ;
     RECT  172.804 35.232 173.267 37.608 ;
     RECT  173.18 43.488 173.267 43.512 ;
     RECT  172.804 34.08 175.208 34.104 ;
     RECT  173.267 35.232 175.208 36.936 ;
     RECT  174.709 38.688 175.208 38.712 ;
     RECT  128.053 41.328 175.208 41.4 ;
     RECT  175.208 2.148 175.312 127.452 ;
     RECT  175.312 2.418 175.504 127.182 ;
     RECT  175.504 34.08 177.908 34.104 ;
     RECT  175.504 35.232 177.908 36.936 ;
     RECT  175.504 38.688 177.908 38.712 ;
     RECT  177.908 2.148 178.012 127.452 ;
     RECT  178.012 2.418 178.204 127.182 ;
     RECT  178.204 35.136 178.445 36.936 ;
     RECT  178.204 34.08 180.608 34.104 ;
     RECT  178.445 35.232 180.608 36.936 ;
     RECT  178.204 38.688 180.608 38.712 ;
     RECT  180.608 2.148 180.712 127.452 ;
     RECT  180.712 2.418 180.904 127.182 ;
     RECT  180.904 35.232 182.389 37.608 ;
     RECT  180.904 38.688 182.389 38.712 ;
     RECT  180.904 34.08 183.308 34.104 ;
     RECT  182.389 35.232 183.308 38.712 ;
     RECT  183.308 2.148 183.412 127.452 ;
     RECT  183.412 2.418 183.604 127.182 ;
     RECT  183.604 34.08 186.008 34.104 ;
     RECT  183.604 35.232 186.008 36.264 ;
     RECT  183.604 37.584 186.008 38.712 ;
     RECT  186.008 2.148 186.112 127.452 ;
     RECT  186.112 2.418 186.304 127.182 ;
     RECT  186.304 34.08 188.708 34.104 ;
     RECT  186.304 35.136 188.708 36.264 ;
     RECT  186.304 37.584 188.708 38.712 ;
     RECT  188.708 2.148 188.812 127.452 ;
     RECT  188.812 2.418 189.004 127.182 ;
     RECT  189.004 35.136 190.433 36.264 ;
     RECT  189.004 34.08 191.408 34.104 ;
     RECT  190.433 35.232 191.408 36.264 ;
     RECT  189.004 37.584 191.408 38.712 ;
     RECT  191.408 2.148 191.512 127.452 ;
     RECT  191.512 2.418 191.704 127.182 ;
     RECT  191.704 34.08 194.108 34.104 ;
     RECT  191.704 35.232 194.108 36.264 ;
     RECT  191.704 37.584 194.108 38.712 ;
     RECT  194.108 2.148 194.212 127.452 ;
     RECT  194.212 2.418 194.404 127.182 ;
     RECT  194.404 34.08 196.808 34.104 ;
     RECT  194.404 35.136 196.808 36.264 ;
     RECT  194.404 37.584 196.808 38.712 ;
     RECT  196.808 2.148 196.912 127.452 ;
     RECT  196.912 2.418 197.104 127.182 ;
     RECT  197.104 34.08 199.508 34.104 ;
     RECT  197.104 35.136 199.508 36.264 ;
     RECT  197.104 37.584 199.508 38.712 ;
     RECT  199.508 2.148 199.612 127.452 ;
     RECT  199.612 2.418 199.804 127.182 ;
     RECT  199.804 34.08 202.208 34.104 ;
     RECT  199.804 35.136 202.208 36.264 ;
     RECT  199.804 37.584 202.208 38.712 ;
     RECT  202.208 2.148 202.312 127.452 ;
     RECT  202.312 2.418 202.504 127.182 ;
     RECT  202.504 34.08 204.908 34.104 ;
     RECT  202.504 35.136 204.908 36.264 ;
     RECT  202.504 37.584 204.908 38.712 ;
     RECT  204.908 2.148 205.012 127.452 ;
     RECT  205.012 2.418 205.204 127.182 ;
     RECT  205.204 35.136 206.381 36.264 ;
     RECT  205.204 34.08 207.608 34.104 ;
     RECT  206.381 35.232 207.608 36.264 ;
     RECT  205.204 37.584 207.608 38.712 ;
     RECT  207.608 2.148 207.712 127.452 ;
     RECT  207.712 2.418 207.904 127.182 ;
     RECT  207.904 34.08 210.308 34.104 ;
     RECT  207.904 35.232 210.308 36.264 ;
     RECT  207.904 37.584 210.308 38.712 ;
     RECT  210.308 2.148 210.412 127.452 ;
     RECT  210.412 2.418 210.604 127.182 ;
     RECT  210.604 34.08 213.008 34.104 ;
     RECT  210.604 35.232 213.008 36.264 ;
     RECT  210.604 37.584 213.008 38.712 ;
     RECT  213.008 2.148 213.112 127.452 ;
     RECT  213.112 2.418 213.304 127.182 ;
     RECT  213.304 35.136 214.373 36.264 ;
     RECT  213.304 34.08 215.708 34.104 ;
     RECT  214.373 35.232 215.708 36.264 ;
     RECT  213.304 37.584 215.708 38.712 ;
     RECT  215.708 2.148 215.812 127.452 ;
     RECT  215.812 2.418 216.004 127.182 ;
     RECT  216.004 34.08 218.408 34.104 ;
     RECT  216.004 35.232 218.408 36.264 ;
     RECT  216.004 37.584 218.408 38.712 ;
     RECT  218.408 2.148 218.512 127.452 ;
     RECT  218.512 2.418 218.704 127.182 ;
     RECT  218.704 34.08 221.108 34.104 ;
     RECT  218.704 35.232 221.108 36.264 ;
     RECT  218.704 37.584 221.108 38.712 ;
     RECT  221.108 2.148 221.212 127.452 ;
     RECT  221.212 2.418 221.404 127.182 ;
     RECT  221.404 35.136 222.329 36.264 ;
     RECT  221.404 34.08 223.808 34.104 ;
     RECT  222.329 35.232 223.808 36.264 ;
     RECT  221.404 37.584 223.808 38.712 ;
     RECT  223.808 2.148 223.912 127.452 ;
     RECT  223.912 2.418 224.104 127.182 ;
     RECT  224.104 37.584 224.165 38.712 ;
     RECT  224.165 37.584 225.157 37.992 ;
     RECT  225.157 37.584 225.203 38.664 ;
     RECT  224.104 34.08 226.508 34.104 ;
     RECT  224.104 35.232 226.508 36.264 ;
     RECT  225.203 37.968 226.508 38.664 ;
     RECT  225.685 40.128 226.508 40.152 ;
     RECT  226.508 2.148 226.612 127.452 ;
     RECT  226.612 2.418 226.804 127.182 ;
     RECT  226.804 34.08 229.208 34.104 ;
     RECT  226.804 35.232 229.208 36.264 ;
     RECT  226.804 37.968 229.208 37.992 ;
     RECT  226.804 40.128 229.208 40.152 ;
     RECT  229.208 2.148 229.312 127.452 ;
     RECT  229.312 2.418 229.504 127.182 ;
     RECT  229.504 40.128 229.601 40.392 ;
     RECT  229.504 37.968 230.321 38.136 ;
     RECT  229.601 40.272 230.321 40.392 ;
     RECT  229.504 34.08 231.908 34.104 ;
     RECT  229.504 35.136 231.908 36.264 ;
     RECT  230.321 37.968 231.908 37.992 ;
     RECT  230.321 40.368 231.908 40.392 ;
     RECT  231.908 2.148 232.012 127.452 ;
     RECT  232.012 2.418 232.204 127.182 ;
     RECT  232.204 34.08 233.237 36.984 ;
     RECT  233.237 34.08 234.608 36.264 ;
     RECT  232.204 37.968 234.608 37.992 ;
     RECT  232.204 40.368 234.608 40.392 ;
     RECT  234.608 2.148 234.712 127.452 ;
     RECT  234.712 2.418 234.904 127.182 ;
     RECT  234.904 34.08 234.929 36.264 ;
     RECT  234.929 34.992 237.308 36.264 ;
     RECT  234.904 37.968 237.308 37.992 ;
     RECT  234.904 40.368 237.308 40.392 ;
     RECT  237.308 2.148 237.412 127.452 ;
     RECT  237.412 2.418 237.604 127.182 ;
     RECT  237.604 35.136 238.313 36.264 ;
     RECT  237.604 37.968 238.313 38.136 ;
     RECT  237.604 40.272 238.313 40.392 ;
     RECT  238.313 35.184 240.008 36.264 ;
     RECT  238.313 37.968 240.008 37.992 ;
     RECT  238.313 40.368 240.008 40.392 ;
     RECT  240.008 2.148 240.112 127.452 ;
     RECT  240.112 2.418 240.304 127.182 ;
     RECT  240.304 35.184 242.708 36.264 ;
     RECT  240.304 37.968 242.708 37.992 ;
     RECT  240.304 40.368 242.708 40.392 ;
     RECT  242.708 2.148 242.812 127.452 ;
     RECT  242.812 2.418 243.004 127.182 ;
     RECT  243.004 35.184 245.408 36.264 ;
     RECT  243.004 37.968 245.408 37.992 ;
     RECT  243.004 40.368 245.408 40.392 ;
     RECT  245.408 2.148 245.512 127.452 ;
     RECT  245.512 2.418 245.704 127.182 ;
     RECT  245.704 40.272 246.269 40.392 ;
     RECT  245.704 37.968 247.477 37.992 ;
     RECT  247.477 37.968 247.489 38.088 ;
     RECT  245.704 35.136 248.108 36.264 ;
     RECT  247.489 37.968 248.108 38.232 ;
     RECT  246.269 40.368 248.108 40.392 ;
     RECT  248.108 2.148 248.212 127.452 ;
     RECT  248.212 2.418 248.404 127.182 ;
     RECT  248.404 38.208 249.041 38.76 ;
     RECT  248.404 40.32 249.113 40.392 ;
     RECT  248.404 35.184 249.721 36.264 ;
     RECT  249.113 40.368 250.081 40.392 ;
     RECT  249.041 38.208 250.189 38.232 ;
     RECT  249.721 35.184 250.333 36.312 ;
     RECT  250.333 35.184 250.808 36.408 ;
     RECT  250.189 38.208 250.808 38.328 ;
     RECT  250.081 40.368 250.808 41.16 ;
     RECT  250.808 2.148 250.912 127.452 ;
     RECT  250.912 2.418 251.104 127.182 ;
     RECT  251.104 35.184 251.165 36.408 ;
     RECT  251.165 36.288 251.219 36.408 ;
     RECT  251.104 39.744 251.219 41.64 ;
     RECT  251.104 38.736 251.245 38.76 ;
     RECT  251.219 36.336 251.309 36.408 ;
     RECT  251.219 41.616 251.417 41.64 ;
     RECT  251.165 35.184 252.133 35.256 ;
     RECT  251.219 39.744 252.181 40.584 ;
     RECT  252.181 39.312 252.277 40.584 ;
     RECT  251.104 42.672 252.277 42.696 ;
     RECT  252.277 42.672 252.364 42.792 ;
     RECT  252.277 39.312 252.529 40.776 ;
     RECT  252.529 38.976 252.62 40.776 ;
     RECT  252.62 38.976 252.661 41.256 ;
     RECT  252.133 34.752 252.781 35.256 ;
     RECT  251.309 36.336 252.781 36.36 ;
     RECT  252.661 38.976 253.285 42.216 ;
     RECT  253.285 38.736 253.333 42.216 ;
     RECT  253.333 38.4 253.381 42.216 ;
     RECT  253.381 38.208 253.465 42.216 ;
     RECT  252.781 34.752 253.508 36.36 ;
     RECT  253.465 38.208 253.508 42.744 ;
     RECT  253.508 2.148 253.612 127.452 ;
     RECT  253.612 2.418 253.804 127.182 ;
     RECT  253.804 34.176 254.099 34.2 ;
     RECT  253.804 35.184 254.099 36.36 ;
     RECT  253.804 37.488 254.147 43.944 ;
     RECT  254.147 37.488 254.197 40.488 ;
     RECT  254.197 37.488 254.225 39.864 ;
     RECT  254.099 35.184 254.405 36.024 ;
     RECT  254.225 37.584 254.483 39.864 ;
     RECT  254.405 35.184 254.585 35.352 ;
     RECT  254.147 41.52 254.729 43.944 ;
     RECT  254.729 41.568 254.765 43.944 ;
     RECT  254.483 38.112 254.801 39.864 ;
     RECT  254.801 38.832 255.017 39.864 ;
     RECT  255.017 39.792 255.053 39.864 ;
     RECT  254.765 41.568 255.161 43.272 ;
     RECT  254.585 35.328 256.208 35.352 ;
     RECT  255.053 39.792 256.208 39.816 ;
     RECT  255.161 41.568 256.208 41.592 ;
     RECT  255.161 42.576 256.208 43.272 ;
     RECT  256.208 2.148 256.312 127.452 ;
     RECT  256.312 2.418 256.504 127.182 ;
     RECT  256.504 34.56 257.605 35.592 ;
     RECT  256.504 39.456 258.109 42.936 ;
     RECT  258.109 39.312 258.145 42.936 ;
     RECT  258.145 39.168 258.181 42.936 ;
     RECT  258.181 38.88 258.217 43.08 ;
     RECT  258.217 38.736 259.081 43.08 ;
     RECT  257.605 34.128 259.116 34.152 ;
     RECT  257.605 34.152 259.164 34.272 ;
     RECT  257.605 34.272 259.116 34.296 ;
     RECT  257.605 34.296 259.164 34.416 ;
     RECT  257.605 34.416 259.116 34.44 ;
     RECT  257.605 34.44 259.164 34.56 ;
     RECT  257.605 34.56 259.116 34.584 ;
     RECT  257.605 34.584 259.164 34.704 ;
     RECT  257.605 34.704 259.116 34.728 ;
     RECT  257.605 34.728 259.164 34.848 ;
     RECT  257.605 34.848 259.116 34.872 ;
     RECT  257.605 34.872 259.164 34.992 ;
     RECT  257.605 34.992 259.116 35.016 ;
     RECT  257.605 35.016 259.164 35.136 ;
     RECT  257.605 35.136 259.116 35.16 ;
     RECT  257.605 35.16 259.164 35.28 ;
     RECT  257.605 35.28 259.116 35.304 ;
     RECT  257.605 35.304 259.164 35.424 ;
     RECT  257.605 35.424 259.116 35.448 ;
     RECT  257.605 35.448 259.164 35.568 ;
     RECT  257.605 35.568 259.116 35.592 ;
     RECT  257.605 35.592 259.164 35.712 ;
     RECT  257.605 35.712 259.116 35.736 ;
     RECT  259.081 38.736 259.116 38.76 ;
     RECT  259.081 38.76 259.164 38.88 ;
     RECT  259.081 38.88 259.116 38.904 ;
     RECT  259.081 38.904 259.164 39.024 ;
     RECT  259.081 39.024 259.116 39.048 ;
     RECT  259.081 39.048 259.164 39.168 ;
     RECT  259.081 39.168 259.116 39.192 ;
     RECT  259.081 39.192 259.164 39.312 ;
     RECT  259.081 39.312 259.116 39.336 ;
     RECT  259.081 39.336 259.164 39.456 ;
     RECT  259.081 39.456 259.116 39.48 ;
     RECT  259.081 39.48 259.164 39.6 ;
     RECT  259.081 39.6 259.116 39.624 ;
     RECT  259.081 39.624 259.164 39.744 ;
     RECT  259.081 39.744 259.116 39.768 ;
     RECT  259.081 39.768 259.164 39.888 ;
     RECT  259.081 39.888 259.116 39.912 ;
     RECT  259.081 39.912 259.164 40.032 ;
     RECT  259.081 40.032 259.116 40.056 ;
     RECT  259.081 40.056 259.164 40.176 ;
     RECT  259.081 40.176 259.116 40.2 ;
     RECT  259.081 40.2 259.164 40.32 ;
     RECT  259.081 40.32 259.116 40.344 ;
     RECT  259.081 40.344 259.164 40.464 ;
     RECT  259.081 40.464 259.116 40.488 ;
     RECT  259.081 40.488 259.164 40.608 ;
     RECT  259.081 40.608 259.116 40.632 ;
     RECT  259.081 40.632 259.164 40.752 ;
     RECT  259.081 40.752 259.116 40.776 ;
     RECT  259.081 40.776 259.164 40.896 ;
     RECT  259.081 40.896 259.116 40.92 ;
     RECT  259.081 40.92 259.164 41.04 ;
     RECT  259.081 41.04 259.116 41.064 ;
     RECT  259.081 41.064 259.164 41.184 ;
     RECT  259.081 41.184 259.116 41.208 ;
     RECT  259.081 41.208 259.164 41.328 ;
     RECT  259.081 41.328 259.116 41.352 ;
     RECT  259.081 41.352 259.164 41.472 ;
     RECT  259.081 41.472 259.116 41.496 ;
     RECT  259.081 41.496 259.164 41.616 ;
     RECT  259.081 41.616 259.116 41.64 ;
     RECT  259.081 41.64 259.164 41.76 ;
     RECT  259.081 41.76 259.116 41.784 ;
     RECT  259.081 41.784 259.164 41.904 ;
     RECT  259.081 41.904 259.116 41.928 ;
     RECT  259.081 41.928 259.164 42.048 ;
     RECT  259.081 42.048 259.116 42.072 ;
     RECT  259.081 42.072 259.164 42.192 ;
     RECT  259.081 42.192 259.116 42.216 ;
     RECT  259.081 42.216 259.164 42.336 ;
     RECT  259.081 42.336 259.116 42.36 ;
     RECT  259.081 42.36 259.164 42.48 ;
     RECT  259.081 42.48 259.116 42.504 ;
     RECT  259.081 42.504 259.164 42.624 ;
     RECT  259.081 42.624 259.116 42.648 ;
     RECT  259.081 42.648 259.164 42.768 ;
     RECT  259.081 42.768 259.116 42.792 ;
     RECT  259.081 42.792 259.164 42.912 ;
     RECT  259.081 42.912 259.116 42.936 ;
     RECT  259.081 42.936 259.164 43.056 ;
     RECT  259.081 43.056 259.116 43.08 ;
     RECT  259.081 43.08 259.164 43.2 ;
     RECT  259.081 43.2 259.116 43.224 ;
    LAYER M5 ;
     RECT  89.304 0.016 89.424 0.084 ;
     RECT  89.448 0.016 89.568 0.084 ;
     RECT  89.592 0.016 89.712 0.084 ;
     RECT  89.736 0.016 89.856 0.084 ;
     RECT  89.28 0.084 89.88 1.811 ;
     RECT  89.28 1.811 89.304 2.137 ;
     RECT  2.4 2.137 2.52 2.151 ;
     RECT  5.1 2.137 5.22 2.151 ;
     RECT  7.8 2.137 7.92 2.151 ;
     RECT  10.5 2.137 10.62 2.151 ;
     RECT  13.2 2.137 13.32 2.151 ;
     RECT  15.9 2.137 16.02 2.151 ;
     RECT  18.6 2.137 18.72 2.151 ;
     RECT  21.3 2.137 21.42 2.151 ;
     RECT  24 2.137 24.12 2.151 ;
     RECT  26.7 2.137 26.82 2.151 ;
     RECT  29.4 2.137 29.52 2.151 ;
     RECT  32.1 2.137 32.22 2.151 ;
     RECT  34.8 2.137 34.92 2.151 ;
     RECT  37.5 2.137 37.62 2.151 ;
     RECT  40.2 2.137 40.32 2.151 ;
     RECT  42.9 2.137 43.02 2.151 ;
     RECT  45.6 2.137 45.72 2.151 ;
     RECT  48.3 2.137 48.42 2.151 ;
     RECT  51 2.137 51.12 2.151 ;
     RECT  53.7 2.137 53.82 2.151 ;
     RECT  56.4 2.137 56.52 2.151 ;
     RECT  59.1 2.137 59.22 2.151 ;
     RECT  61.8 2.137 61.92 2.151 ;
     RECT  64.5 2.137 64.62 2.151 ;
     RECT  67.2 2.137 67.32 2.151 ;
     RECT  69.9 2.137 70.02 2.151 ;
     RECT  72.6 2.137 72.72 2.151 ;
     RECT  75.3 2.137 75.42 2.151 ;
     RECT  78 2.137 78.12 2.151 ;
     RECT  80.7 2.137 80.82 2.151 ;
     RECT  83.4 2.137 83.52 2.151 ;
     RECT  86.1 2.137 86.22 2.151 ;
     RECT  91.5 2.137 91.62 2.151 ;
     RECT  94.2 2.137 94.32 2.151 ;
     RECT  96.9 2.137 97.02 2.151 ;
     RECT  99.6 2.137 99.72 2.151 ;
     RECT  102.3 2.137 102.42 2.151 ;
     RECT  105 2.137 105.12 2.151 ;
     RECT  107.7 2.137 107.82 2.151 ;
     RECT  110.4 2.137 110.52 2.151 ;
     RECT  113.1 2.137 113.22 2.151 ;
     RECT  115.8 2.137 115.92 2.151 ;
     RECT  118.5 2.137 118.62 2.151 ;
     RECT  121.2 2.137 121.32 2.151 ;
     RECT  123.9 2.137 124.02 2.151 ;
     RECT  126.6 2.137 126.72 2.151 ;
     RECT  129.3 2.137 129.42 2.151 ;
     RECT  132 2.137 132.12 2.151 ;
     RECT  134.7 2.137 134.82 2.151 ;
     RECT  137.4 2.137 137.52 2.151 ;
     RECT  140.1 2.137 140.22 2.151 ;
     RECT  142.8 2.137 142.92 2.151 ;
     RECT  145.5 2.137 145.62 2.151 ;
     RECT  148.2 2.137 148.32 2.151 ;
     RECT  150.9 2.137 151.02 2.151 ;
     RECT  153.6 2.137 153.72 2.151 ;
     RECT  156.3 2.137 156.42 2.151 ;
     RECT  159 2.137 159.12 2.151 ;
     RECT  161.7 2.137 161.82 2.151 ;
     RECT  164.4 2.137 164.52 2.151 ;
     RECT  167.1 2.137 167.22 2.151 ;
     RECT  169.8 2.137 169.92 2.151 ;
     RECT  172.5 2.137 172.62 2.151 ;
     RECT  175.2 2.137 175.32 2.151 ;
     RECT  177.9 2.137 178.02 2.151 ;
     RECT  180.6 2.137 180.72 2.151 ;
     RECT  183.3 2.137 183.42 2.151 ;
     RECT  186 2.137 186.12 2.151 ;
     RECT  188.7 2.137 188.82 2.151 ;
     RECT  191.4 2.137 191.52 2.151 ;
     RECT  194.1 2.137 194.22 2.151 ;
     RECT  196.8 2.137 196.92 2.151 ;
     RECT  199.5 2.137 199.62 2.151 ;
     RECT  202.2 2.137 202.32 2.151 ;
     RECT  204.9 2.137 205.02 2.151 ;
     RECT  207.6 2.137 207.72 2.151 ;
     RECT  210.3 2.137 210.42 2.151 ;
     RECT  213 2.137 213.12 2.151 ;
     RECT  215.7 2.137 215.82 2.151 ;
     RECT  218.4 2.137 218.52 2.151 ;
     RECT  221.1 2.137 221.22 2.151 ;
     RECT  223.8 2.137 223.92 2.151 ;
     RECT  226.5 2.137 226.62 2.151 ;
     RECT  229.2 2.137 229.32 2.151 ;
     RECT  231.9 2.137 232.02 2.151 ;
     RECT  234.6 2.137 234.72 2.151 ;
     RECT  237.3 2.137 237.42 2.151 ;
     RECT  240 2.137 240.12 2.151 ;
     RECT  242.7 2.137 242.82 2.151 ;
     RECT  245.4 2.137 245.52 2.151 ;
     RECT  248.1 2.137 248.22 2.151 ;
     RECT  250.8 2.137 250.92 2.151 ;
     RECT  253.5 2.137 253.62 2.151 ;
     RECT  256.2 2.137 256.32 2.151 ;
     RECT  86.1 2.151 86.412 2.581 ;
     RECT  91.5 2.151 91.812 2.581 ;
     RECT  90.624 2.581 91.812 2.915 ;
     RECT  86.1 2.581 87.144 3.443 ;
     RECT  96.9 2.151 97.212 4.117 ;
     RECT  90.72 2.915 91.812 4.163 ;
     RECT  91.5 4.163 91.812 14.917 ;
     RECT  91.152 14.917 91.812 17.557 ;
     RECT  80.7 2.151 81.012 20.053 ;
     RECT  86.1 3.443 86.904 20.099 ;
     RECT  90.72 17.557 91.812 20.147 ;
     RECT  102.3 2.151 102.612 24.901 ;
     RECT  61.8 2.151 62.112 25.717 ;
     RECT  64.5 2.151 64.812 26.629 ;
     RECT  59.1 2.151 59.412 26.725 ;
     RECT  61.8 25.717 62.232 26.725 ;
     RECT  7.8 2.151 8.112 27.157 ;
     RECT  32.1 2.151 32.412 27.157 ;
     RECT  5.1 2.151 5.412 27.301 ;
     RECT  7.8 27.157 8.232 27.301 ;
     RECT  59.1 26.725 62.232 27.301 ;
     RECT  72.6 2.151 72.912 27.781 ;
     RECT  7.8 27.301 9.192 27.877 ;
     RECT  10.5 2.151 10.812 27.877 ;
     RECT  26.7 2.151 27.012 27.877 ;
     RECT  31.824 27.157 32.412 27.877 ;
     RECT  58.992 27.301 62.232 28.259 ;
     RECT  72.6 27.781 73.464 28.261 ;
     RECT  72.6 28.261 74.136 28.307 ;
     RECT  4.032 26.725 4.056 28.453 ;
     RECT  5.1 27.301 6.168 28.453 ;
     RECT  7.152 27.877 10.812 28.453 ;
     RECT  56.4 2.151 56.712 28.453 ;
     RECT  42.9 2.151 43.212 28.789 ;
     RECT  80.064 20.053 81.012 28.933 ;
     RECT  40.2 2.151 40.512 28.981 ;
     RECT  45.6 2.151 45.912 29.029 ;
     RECT  51 2.151 51.312 29.029 ;
     RECT  37.5 2.151 37.812 29.077 ;
     RECT  36.816 29.077 37.812 29.219 ;
     RECT  40.2 28.981 41.304 29.363 ;
     RECT  31.824 27.877 32.568 29.365 ;
     RECT  61.8 28.259 62.232 29.365 ;
     RECT  67.2 2.151 67.512 29.365 ;
     RECT  69.9 2.151 70.212 29.365 ;
     RECT  47.088 29.413 47.112 29.509 ;
     RECT  61.152 29.365 62.232 29.509 ;
     RECT  34.8 2.151 35.112 29.605 ;
     RECT  47.088 29.509 47.16 29.605 ;
     RECT  48.3 2.151 48.612 29.605 ;
     RECT  57.744 28.261 57.768 29.605 ;
     RECT  58.992 28.259 60.168 29.605 ;
     RECT  50.64 29.029 51.312 29.653 ;
     RECT  74.112 28.307 74.136 29.845 ;
     RECT  75.3 2.151 75.612 29.845 ;
     RECT  31.056 29.365 32.568 30.037 ;
     RECT  64.5 26.629 64.968 30.037 ;
     RECT  67.104 29.365 67.512 30.133 ;
     RECT  42.624 28.789 43.212 30.181 ;
     RECT  4.032 28.453 10.812 30.275 ;
     RECT  29.4 2.151 29.712 30.325 ;
     RECT  72.6 28.307 72.912 30.421 ;
     RECT  29.4 30.325 29.832 30.515 ;
     RECT  66.96 30.133 67.512 30.661 ;
     RECT  50.64 29.653 52.104 30.709 ;
     RECT  31.056 30.037 32.808 30.757 ;
     RECT  57.744 29.605 60.168 30.803 ;
     RECT  53.7 2.151 54.012 30.805 ;
     RECT  55.44 28.453 56.712 30.805 ;
     RECT  57.744 30.803 57.768 30.805 ;
     RECT  50.64 30.709 52.152 30.949 ;
     RECT  45.36 29.029 45.912 30.997 ;
     RECT  53.7 30.805 57.768 31.091 ;
     RECT  37.056 29.219 37.812 31.187 ;
     RECT  29.4 30.515 29.712 31.189 ;
     RECT  42.624 30.181 43.368 31.285 ;
     RECT  69.9 29.365 70.344 31.285 ;
     RECT  31.056 30.757 33.672 31.379 ;
     RECT  47.088 29.605 48.612 31.379 ;
     RECT  72.48 30.421 72.912 31.427 ;
     RECT  26.7 27.877 27.144 31.525 ;
     RECT  29.04 31.189 29.712 31.525 ;
     RECT  50.496 30.949 52.152 31.571 ;
     RECT  74.112 29.845 75.612 31.619 ;
     RECT  26.7 31.525 29.712 31.669 ;
     RECT  69.792 31.285 70.344 31.669 ;
     RECT  74.688 31.619 75.612 31.811 ;
     RECT  53.7 31.091 54.264 31.861 ;
     RECT  42.192 31.285 43.368 31.909 ;
     RECT  66.96 30.661 67.608 31.909 ;
     RECT  26.7 31.669 30.12 31.955 ;
     RECT  31.584 31.379 33.672 31.955 ;
     RECT  63.888 30.037 64.968 32.005 ;
     RECT  66.672 31.909 67.608 32.005 ;
     RECT  68.688 28.981 68.712 32.005 ;
     RECT  39.168 29.653 39.192 32.149 ;
     RECT  40.2 29.363 41.208 32.149 ;
     RECT  69.792 31.669 71.304 32.149 ;
     RECT  69.792 32.149 71.544 32.195 ;
     RECT  26.7 31.955 27.144 32.243 ;
     RECT  82.368 17.605 82.392 32.243 ;
     RECT  69.792 32.195 70.344 32.291 ;
     RECT  18.6 2.151 18.912 32.293 ;
     RECT  21.3 2.151 21.612 32.293 ;
     RECT  50.496 31.571 51.672 32.437 ;
     RECT  110.4 2.151 110.712 32.437 ;
     RECT  53.568 31.861 54.264 32.531 ;
     RECT  58.8 30.803 60.168 32.629 ;
     RECT  61.152 29.509 62.424 32.629 ;
     RECT  55.44 31.091 57.768 32.771 ;
     RECT  66.672 32.005 68.712 32.771 ;
     RECT  2.4 2.151 2.712 32.773 ;
     RECT  37.296 31.187 37.812 32.821 ;
     RECT  39.168 32.149 41.208 32.821 ;
     RECT  34.8 29.605 35.88 32.869 ;
     RECT  47.952 31.379 48.612 32.869 ;
     RECT  34.704 32.869 35.88 32.917 ;
     RECT  42.192 31.909 43.56 32.963 ;
     RECT  37.296 32.821 41.208 33.013 ;
     RECT  34.704 32.917 35.928 33.059 ;
     RECT  58.8 32.629 62.424 33.059 ;
     RECT  2.4 32.773 2.808 33.107 ;
     RECT  44.544 30.997 45.912 33.107 ;
     RECT  63.888 32.005 65.592 33.253 ;
     RECT  66.672 32.771 67.8 33.253 ;
     RECT  84.96 31.093 84.984 33.299 ;
     RECT  55.584 32.771 57.768 33.443 ;
     RECT  31.584 31.955 33.48 33.587 ;
     RECT  75.3 31.811 75.612 33.589 ;
     RECT  42.624 32.963 43.56 33.635 ;
     RECT  96.528 4.117 97.212 33.637 ;
     RECT  17.856 32.293 18.912 33.683 ;
     RECT  21.072 32.293 21.612 33.683 ;
     RECT  63.888 33.253 67.8 33.683 ;
     RECT  110.4 32.437 110.808 33.683 ;
     RECT  31.584 33.587 33.432 33.779 ;
     RECT  37.296 33.013 41.256 33.875 ;
     RECT  4.512 30.275 10.812 33.877 ;
     RECT  3.984 33.877 10.812 33.923 ;
     RECT  128.064 32.293 128.088 33.925 ;
     RECT  129.3 2.151 129.612 33.925 ;
     RECT  53.7 32.531 54.264 33.973 ;
     RECT  28.368 31.955 30.12 34.067 ;
     RECT  34.8 33.059 35.784 34.069 ;
     RECT  45.36 33.107 45.912 34.069 ;
     RECT  55.584 33.443 57.576 34.115 ;
     RECT  63.888 33.683 66.168 34.115 ;
     RECT  42.9 33.635 43.56 34.117 ;
     RECT  44.544 34.069 45.912 34.117 ;
     RECT  46.944 32.101 46.968 34.117 ;
     RECT  47.952 32.869 48.792 34.117 ;
     RECT  234.6 2.151 234.912 34.165 ;
     RECT  253.5 2.151 253.812 34.165 ;
     RECT  34.8 34.069 36.264 34.211 ;
     RECT  31.584 33.779 33.096 34.259 ;
     RECT  46.944 34.117 48.792 34.259 ;
     RECT  58.8 33.059 60.168 34.259 ;
     RECT  61.152 33.059 62.424 34.259 ;
     RECT  74.64 33.589 75.612 34.259 ;
     RECT  69.9 32.291 70.344 34.357 ;
     RECT  55.584 34.115 57.432 34.403 ;
     RECT  113.1 2.151 113.412 34.453 ;
     RECT  67.2 33.683 67.8 34.501 ;
     RECT  121.2 2.151 121.512 34.501 ;
     RECT  67.2 34.501 67.992 34.691 ;
     RECT  42.9 34.117 45.912 34.741 ;
     RECT  53.7 33.973 54.552 34.741 ;
     RECT  55.584 34.403 56.712 34.741 ;
     RECT  128.064 33.925 129.612 34.741 ;
     RECT  3.984 33.923 4.008 34.787 ;
     RECT  48 34.259 48.792 34.787 ;
     RECT  53.7 34.741 56.712 34.787 ;
     RECT  55.824 34.787 56.712 34.883 ;
     RECT  114.384 34.165 114.408 34.885 ;
     RECT  28.368 34.067 29.832 34.931 ;
     RECT  88.8 2.137 89.304 35.027 ;
     RECT  234.48 34.165 234.912 35.027 ;
     RECT  40.2 33.875 41.256 35.125 ;
     RECT  121.2 34.501 121.608 35.171 ;
     RECT  112.992 34.453 113.412 35.173 ;
     RECT  114.384 34.885 114.552 35.173 ;
     RECT  145.5 2.151 145.812 35.173 ;
     RECT  5.1 33.923 10.812 35.219 ;
     RECT  31.584 34.259 32.904 35.267 ;
     RECT  5.1 35.219 5.784 35.269 ;
     RECT  42.432 34.741 45.912 35.315 ;
     RECT  48.3 34.787 48.792 35.315 ;
     RECT  58.8 34.259 59.544 35.315 ;
     RECT  68.976 34.357 70.344 35.315 ;
     RECT  112.992 35.173 114.552 35.315 ;
     RECT  145.5 35.173 146.52 35.315 ;
     RECT  253.5 34.165 254.088 35.317 ;
     RECT  6.864 35.219 10.812 35.363 ;
     RECT  53.7 34.787 54.696 35.363 ;
     RECT  96.336 33.637 97.212 35.363 ;
     RECT  34.8 34.211 36.168 35.365 ;
     RECT  37.296 33.875 38.808 35.365 ;
     RECT  61.8 34.259 62.424 35.411 ;
     RECT  69.9 35.315 70.344 35.411 ;
     RECT  31.584 35.267 32.808 35.459 ;
     RECT  63.504 35.317 63.528 35.507 ;
     RECT  252.192 34.741 252.216 35.509 ;
     RECT  253.392 35.317 254.328 35.509 ;
     RECT  115.8 2.151 116.112 35.605 ;
     RECT  34.8 35.365 38.808 35.699 ;
     RECT  44.544 35.315 45.912 35.699 ;
     RECT  137.4 2.151 137.712 35.701 ;
     RECT  67.2 34.691 67.8 35.747 ;
     RECT  59.1 35.315 59.544 35.939 ;
     RECT  248.1 2.151 248.412 35.941 ;
     RECT  252.192 35.509 254.328 35.987 ;
     RECT  114.528 35.315 114.552 35.989 ;
     RECT  115.8 35.605 116.856 35.989 ;
     RECT  29.4 34.931 29.832 36.035 ;
     RECT  50.256 32.437 51.672 36.035 ;
     RECT  64.5 34.115 66.168 36.035 ;
     RECT  114.528 35.989 116.856 36.035 ;
     RECT  40.2 35.125 41.352 36.037 ;
     RECT  66.144 36.035 66.168 36.275 ;
     RECT  71.52 32.195 71.544 36.275 ;
     RECT  114.96 36.035 116.856 36.275 ;
     RECT  250.8 2.151 251.112 36.277 ;
     RECT  40.032 36.037 41.352 36.371 ;
     RECT  53.7 35.363 54.012 36.421 ;
     RECT  112.992 35.315 113.412 36.421 ;
     RECT  4.8 35.269 5.784 36.515 ;
     RECT  42.432 35.315 43.212 36.515 ;
     RECT  46.944 34.259 46.968 36.515 ;
     RECT  128.064 34.741 130.584 36.515 ;
     RECT  52.992 36.421 54.012 36.517 ;
     RECT  34.8 35.699 38.472 36.563 ;
     RECT  31.584 35.459 32.712 36.611 ;
     RECT  7.296 35.363 9.096 36.661 ;
     RECT  48.3 35.315 48.612 36.709 ;
     RECT  10.368 35.363 10.812 36.851 ;
     RECT  40.08 36.371 41.352 36.851 ;
     RECT  47.328 36.709 48.612 36.851 ;
     RECT  50.496 36.035 51.672 36.851 ;
     RECT  52.992 36.517 54.552 36.851 ;
     RECT  51 36.851 51.672 36.899 ;
     RECT  118.5 2.151 118.812 36.901 ;
     RECT  183.3 2.151 183.612 36.901 ;
     RECT  112.848 36.421 113.412 36.997 ;
     RECT  118.5 36.901 118.92 36.997 ;
     RECT  121.2 35.171 121.512 36.997 ;
     RECT  132 2.151 132.312 36.997 ;
     RECT  45.024 35.699 45.912 37.043 ;
     RECT  126.6 2.151 126.912 37.045 ;
     RECT  128.064 36.515 129.612 37.045 ;
     RECT  7.296 36.661 9.384 37.091 ;
     RECT  28.368 34.931 28.392 37.139 ;
     RECT  52.992 36.851 54.012 37.139 ;
     RECT  40.2 36.851 41.352 37.235 ;
     RECT  40.2 37.235 41.256 37.283 ;
     RECT  126.6 37.045 129.612 37.379 ;
     RECT  79.824 28.933 81.012 37.429 ;
     RECT  137.184 35.701 137.712 37.475 ;
     RECT  31.584 36.611 32.412 37.571 ;
     RECT  79.824 37.429 81.288 37.571 ;
     RECT  172.5 2.151 172.812 37.573 ;
     RECT  252.192 35.987 254.136 37.573 ;
     RECT  7.8 37.091 9.384 37.619 ;
     RECT  128.064 37.379 129.612 37.619 ;
     RECT  131.232 36.997 132.312 37.619 ;
     RECT  112.848 36.997 113.976 37.669 ;
     RECT  114.96 36.275 116.472 37.669 ;
     RECT  118.5 36.997 119.304 37.669 ;
     RECT  112.848 37.669 116.472 37.715 ;
     RECT  30.768 37.669 30.792 37.811 ;
     RECT  118.5 37.669 119.928 37.811 ;
     RECT  182.4 36.901 183.612 38.003 ;
     RECT  247.488 35.941 248.412 38.099 ;
     RECT  112.992 37.715 116.472 38.149 ;
     RECT  9.36 37.619 9.384 38.243 ;
     RECT  225.168 37.573 225.192 38.629 ;
     RECT  226.5 2.151 226.812 38.629 ;
     RECT  225.168 38.629 226.812 38.675 ;
     RECT  175.2 2.151 175.512 38.677 ;
     RECT  121.008 36.997 121.512 38.725 ;
     RECT  122.544 38.149 122.568 38.725 ;
     RECT  34.8 36.563 37.812 39.203 ;
     RECT  252.192 37.573 254.472 39.347 ;
     RECT  101.808 24.901 102.612 39.587 ;
     RECT  121.008 38.725 122.568 39.733 ;
     RECT  123.9 2.151 124.212 39.733 ;
     RECT  252.288 39.347 254.472 39.733 ;
     RECT  112.992 38.149 117.432 39.923 ;
     RECT  225.696 38.675 226.812 40.163 ;
     RECT  114.816 39.923 117.432 40.645 ;
     RECT  118.5 37.811 119.352 40.645 ;
     RECT  36.144 39.203 37.812 41.075 ;
     RECT  114.816 40.645 119.352 41.173 ;
     RECT  128.064 37.619 128.088 41.363 ;
     RECT  174.72 38.677 175.512 41.411 ;
     RECT  112.992 39.923 113.412 41.557 ;
     RECT  121.008 39.733 124.212 41.605 ;
     RECT  250.8 36.277 251.208 41.651 ;
     RECT  112.992 41.557 113.592 42.227 ;
     RECT  252.288 39.733 254.52 42.227 ;
     RECT  252.288 42.227 252.312 42.803 ;
     RECT  114.816 41.173 119.592 43.331 ;
     RECT  172.5 37.573 173.256 43.523 ;
     RECT  80.7 37.571 81.288 43.715 ;
     RECT  114.816 43.331 117.432 43.763 ;
     RECT  118.5 43.331 119.592 43.861 ;
     RECT  120.912 41.605 124.212 43.861 ;
     RECT  117.408 43.763 117.432 43.955 ;
     RECT  253.5 42.227 254.52 43.955 ;
     RECT  114.816 43.763 116.112 44.099 ;
     RECT  36.72 41.075 37.812 44.437 ;
     RECT  118.5 43.861 124.212 44.915 ;
     RECT  113.1 42.227 113.592 45.155 ;
     RECT  122.976 44.915 124.212 45.443 ;
     RECT  118.5 44.915 121.992 46.021 ;
     RECT  34.8 39.203 35.112 46.165 ;
     RECT  36.432 44.437 37.812 46.165 ;
     RECT  42.624 36.515 43.212 46.259 ;
     RECT  118.5 46.021 122.52 46.501 ;
     RECT  117.456 44.965 117.48 46.693 ;
     RECT  118.5 46.501 122.76 46.693 ;
     RECT  34.8 46.165 37.812 46.835 ;
     RECT  42.72 46.259 43.212 47.075 ;
     RECT  117.456 46.693 122.76 47.075 ;
     RECT  122.496 47.075 122.76 47.269 ;
     RECT  123.9 45.443 124.212 47.269 ;
     RECT  129.3 37.619 129.612 47.317 ;
     RECT  117.456 47.075 119.592 47.363 ;
     RECT  128.88 47.317 129.612 47.507 ;
     RECT  117.936 47.363 119.592 47.651 ;
     RECT  36.72 46.835 37.812 47.843 ;
     RECT  120.912 47.075 121.512 48.179 ;
     RECT  115.632 44.099 116.112 48.419 ;
     RECT  122.496 47.269 124.212 48.563 ;
     RECT  117.936 47.651 118.812 48.803 ;
     RECT  123.12 48.563 124.212 48.947 ;
     RECT  2.4 33.107 2.712 127.449 ;
     RECT  5.1 36.515 5.412 127.449 ;
     RECT  7.8 37.619 8.112 127.449 ;
     RECT  10.5 36.851 10.812 127.449 ;
     RECT  13.2 2.151 13.512 127.449 ;
     RECT  15.9 2.151 16.212 127.449 ;
     RECT  18.6 33.683 18.912 127.449 ;
     RECT  21.3 33.683 21.612 127.449 ;
     RECT  24 2.151 24.312 127.449 ;
     RECT  26.7 32.243 27.012 127.449 ;
     RECT  29.4 36.035 29.712 127.449 ;
     RECT  32.1 37.571 32.412 127.449 ;
     RECT  34.8 46.835 35.112 127.449 ;
     RECT  37.5 47.843 37.812 127.449 ;
     RECT  40.2 37.283 40.512 127.449 ;
     RECT  42.9 47.075 43.212 127.449 ;
     RECT  45.6 37.043 45.912 127.449 ;
     RECT  48.3 36.851 48.612 127.449 ;
     RECT  51 36.899 51.312 127.449 ;
     RECT  53.7 37.139 54.012 127.449 ;
     RECT  56.4 34.883 56.712 127.449 ;
     RECT  59.1 35.939 59.412 127.449 ;
     RECT  61.8 35.411 62.112 127.449 ;
     RECT  64.5 36.035 64.812 127.449 ;
     RECT  67.2 35.747 67.512 127.449 ;
     RECT  69.9 35.411 70.212 127.449 ;
     RECT  72.6 31.427 72.912 127.449 ;
     RECT  75.3 34.259 75.612 127.449 ;
     RECT  78 2.151 78.312 127.449 ;
     RECT  80.7 43.715 81.012 127.449 ;
     RECT  83.4 2.151 83.712 127.449 ;
     RECT  86.1 20.099 86.412 127.449 ;
     RECT  88.8 35.027 89.112 127.449 ;
     RECT  91.5 20.147 91.812 127.449 ;
     RECT  94.2 2.151 94.512 127.449 ;
     RECT  96.9 35.363 97.212 127.449 ;
     RECT  99.6 2.151 99.912 127.449 ;
     RECT  102.3 39.587 102.612 127.449 ;
     RECT  105 2.151 105.312 127.449 ;
     RECT  107.7 2.151 108.012 127.449 ;
     RECT  110.4 33.683 110.712 127.449 ;
     RECT  113.1 45.155 113.412 127.449 ;
     RECT  115.8 48.419 116.112 127.449 ;
     RECT  118.5 48.803 118.812 127.449 ;
     RECT  121.2 48.179 121.512 127.449 ;
     RECT  123.9 48.947 124.212 127.449 ;
     RECT  126.6 37.379 126.912 127.449 ;
     RECT  129.3 47.507 129.612 127.449 ;
     RECT  132 37.619 132.312 127.449 ;
     RECT  134.7 2.151 135.012 127.449 ;
     RECT  137.4 37.475 137.712 127.449 ;
     RECT  140.1 2.151 140.412 127.449 ;
     RECT  142.8 2.151 143.112 127.449 ;
     RECT  145.5 35.315 145.812 127.449 ;
     RECT  148.2 2.151 148.512 127.449 ;
     RECT  150.9 2.151 151.212 127.449 ;
     RECT  153.6 2.151 153.912 127.449 ;
     RECT  156.3 2.151 156.612 127.449 ;
     RECT  159 2.151 159.312 127.449 ;
     RECT  161.7 2.151 162.012 127.449 ;
     RECT  164.4 2.151 164.712 127.449 ;
     RECT  167.1 2.151 167.412 127.449 ;
     RECT  169.8 2.151 170.112 127.449 ;
     RECT  172.5 43.523 172.812 127.449 ;
     RECT  175.2 41.411 175.512 127.449 ;
     RECT  177.9 2.151 178.212 127.449 ;
     RECT  180.6 2.151 180.912 127.449 ;
     RECT  183.3 38.003 183.612 127.449 ;
     RECT  186 2.151 186.312 127.449 ;
     RECT  188.7 2.151 189.012 127.449 ;
     RECT  191.4 2.151 191.712 127.449 ;
     RECT  194.1 2.151 194.412 127.449 ;
     RECT  196.8 2.151 197.112 127.449 ;
     RECT  199.5 2.151 199.812 127.449 ;
     RECT  202.2 2.151 202.512 127.449 ;
     RECT  204.9 2.151 205.212 127.449 ;
     RECT  207.6 2.151 207.912 127.449 ;
     RECT  210.3 2.151 210.612 127.449 ;
     RECT  213 2.151 213.312 127.449 ;
     RECT  215.7 2.151 216.012 127.449 ;
     RECT  218.4 2.151 218.712 127.449 ;
     RECT  221.1 2.151 221.412 127.449 ;
     RECT  223.8 2.151 224.112 127.449 ;
     RECT  226.5 40.163 226.812 127.449 ;
     RECT  229.2 2.151 229.512 127.449 ;
     RECT  231.9 2.151 232.212 127.449 ;
     RECT  234.6 35.027 234.912 127.449 ;
     RECT  237.3 2.151 237.612 127.449 ;
     RECT  240 2.151 240.312 127.449 ;
     RECT  242.7 2.151 243.012 127.449 ;
     RECT  245.4 2.151 245.712 127.449 ;
     RECT  248.1 38.099 248.412 127.449 ;
     RECT  250.8 41.651 251.112 127.449 ;
     RECT  253.5 43.955 253.812 127.449 ;
     RECT  256.2 2.151 256.512 127.449 ;
     RECT  2.4 127.449 2.52 127.463 ;
     RECT  5.1 127.449 5.22 127.463 ;
     RECT  7.8 127.449 7.92 127.463 ;
     RECT  10.5 127.449 10.62 127.463 ;
     RECT  13.2 127.449 13.32 127.463 ;
     RECT  15.9 127.449 16.02 127.463 ;
     RECT  18.6 127.449 18.72 127.463 ;
     RECT  21.3 127.449 21.42 127.463 ;
     RECT  24 127.449 24.12 127.463 ;
     RECT  26.7 127.449 26.82 127.463 ;
     RECT  29.4 127.449 29.52 127.463 ;
     RECT  32.1 127.449 32.22 127.463 ;
     RECT  34.8 127.449 34.92 127.463 ;
     RECT  37.5 127.449 37.62 127.463 ;
     RECT  40.2 127.449 40.32 127.463 ;
     RECT  42.9 127.449 43.02 127.463 ;
     RECT  45.6 127.449 45.72 127.463 ;
     RECT  48.3 127.449 48.42 127.463 ;
     RECT  51 127.449 51.12 127.463 ;
     RECT  53.7 127.449 53.82 127.463 ;
     RECT  56.4 127.449 56.52 127.463 ;
     RECT  59.1 127.449 59.22 127.463 ;
     RECT  61.8 127.449 61.92 127.463 ;
     RECT  64.5 127.449 64.62 127.463 ;
     RECT  67.2 127.449 67.32 127.463 ;
     RECT  69.9 127.449 70.02 127.463 ;
     RECT  72.6 127.449 72.72 127.463 ;
     RECT  75.3 127.449 75.42 127.463 ;
     RECT  78 127.449 78.12 127.463 ;
     RECT  80.7 127.449 80.82 127.463 ;
     RECT  83.4 127.449 83.52 127.463 ;
     RECT  86.1 127.449 86.22 127.463 ;
     RECT  88.8 127.449 88.92 127.463 ;
     RECT  91.5 127.449 91.62 127.463 ;
     RECT  94.2 127.449 94.32 127.463 ;
     RECT  96.9 127.449 97.02 127.463 ;
     RECT  99.6 127.449 99.72 127.463 ;
     RECT  102.3 127.449 102.42 127.463 ;
     RECT  105 127.449 105.12 127.463 ;
     RECT  107.7 127.449 107.82 127.463 ;
     RECT  110.4 127.449 110.52 127.463 ;
     RECT  113.1 127.449 113.22 127.463 ;
     RECT  115.8 127.449 115.92 127.463 ;
     RECT  118.5 127.449 118.62 127.463 ;
     RECT  121.2 127.449 121.32 127.463 ;
     RECT  123.9 127.449 124.02 127.463 ;
     RECT  126.6 127.449 126.72 127.463 ;
     RECT  129.3 127.449 129.42 127.463 ;
     RECT  132 127.449 132.12 127.463 ;
     RECT  134.7 127.449 134.82 127.463 ;
     RECT  137.4 127.449 137.52 127.463 ;
     RECT  140.1 127.449 140.22 127.463 ;
     RECT  142.8 127.449 142.92 127.463 ;
     RECT  145.5 127.449 145.62 127.463 ;
     RECT  148.2 127.449 148.32 127.463 ;
     RECT  150.9 127.449 151.02 127.463 ;
     RECT  153.6 127.449 153.72 127.463 ;
     RECT  156.3 127.449 156.42 127.463 ;
     RECT  159 127.449 159.12 127.463 ;
     RECT  161.7 127.449 161.82 127.463 ;
     RECT  164.4 127.449 164.52 127.463 ;
     RECT  167.1 127.449 167.22 127.463 ;
     RECT  169.8 127.449 169.92 127.463 ;
     RECT  172.5 127.449 172.62 127.463 ;
     RECT  175.2 127.449 175.32 127.463 ;
     RECT  177.9 127.449 178.02 127.463 ;
     RECT  180.6 127.449 180.72 127.463 ;
     RECT  183.3 127.449 183.42 127.463 ;
     RECT  186 127.449 186.12 127.463 ;
     RECT  188.7 127.449 188.82 127.463 ;
     RECT  191.4 127.449 191.52 127.463 ;
     RECT  194.1 127.449 194.22 127.463 ;
     RECT  196.8 127.449 196.92 127.463 ;
     RECT  199.5 127.449 199.62 127.463 ;
     RECT  202.2 127.449 202.32 127.463 ;
     RECT  204.9 127.449 205.02 127.463 ;
     RECT  207.6 127.449 207.72 127.463 ;
     RECT  210.3 127.449 210.42 127.463 ;
     RECT  213 127.449 213.12 127.463 ;
     RECT  215.7 127.449 215.82 127.463 ;
     RECT  218.4 127.449 218.52 127.463 ;
     RECT  221.1 127.449 221.22 127.463 ;
     RECT  223.8 127.449 223.92 127.463 ;
     RECT  226.5 127.449 226.62 127.463 ;
     RECT  229.2 127.449 229.32 127.463 ;
     RECT  231.9 127.449 232.02 127.463 ;
     RECT  234.6 127.449 234.72 127.463 ;
     RECT  237.3 127.449 237.42 127.463 ;
     RECT  240 127.449 240.12 127.463 ;
     RECT  242.7 127.449 242.82 127.463 ;
     RECT  245.4 127.449 245.52 127.463 ;
     RECT  248.1 127.449 248.22 127.463 ;
     RECT  250.8 127.449 250.92 127.463 ;
     RECT  253.5 127.449 253.62 127.463 ;
     RECT  256.2 127.449 256.32 127.463 ;
     RECT  89.304 1.811 89.88 2.581 ;
     RECT  89.304 2.581 90.624 2.915 ;
     RECT  89.304 2.915 90.72 4.163 ;
     RECT  89.304 17.557 90.72 20.147 ;
     RECT  81.012 17.605 82.368 32.243 ;
     RECT  82.392 17.605 83.4 32.243 ;
     RECT  2.712 26.725 4.032 30.275 ;
     RECT  4.056 26.725 5.1 28.453 ;
     RECT  9.192 27.301 10.5 27.877 ;
     RECT  6.168 27.877 7.152 28.453 ;
     RECT  60.168 28.259 61.8 29.365 ;
     RECT  56.712 28.261 57.744 30.805 ;
     RECT  57.768 28.261 58.992 29.605 ;
     RECT  74.136 28.261 75.3 29.845 ;
     RECT  72.912 28.307 74.112 31.619 ;
     RECT  54.012 28.453 55.44 30.805 ;
     RECT  78.312 28.933 79.824 37.571 ;
     RECT  41.304 28.981 42.624 29.363 ;
     RECT  67.512 28.981 68.688 30.661 ;
     RECT  68.712 28.981 69.9 31.285 ;
     RECT  36.816 29.219 37.056 29.605 ;
     RECT  41.208 29.363 42.624 31.285 ;
     RECT  29.712 29.365 31.056 30.325 ;
     RECT  60.168 29.365 61.152 32.629 ;
     RECT  45.912 29.413 47.088 31.379 ;
     RECT  47.112 29.413 48.3 29.509 ;
     RECT  47.16 29.509 48.3 29.605 ;
     RECT  35.88 29.605 37.056 31.187 ;
     RECT  37.812 29.653 39.168 32.821 ;
     RECT  39.192 29.653 40.2 32.149 ;
     RECT  62.424 30.037 63.888 34.115 ;
     RECT  29.832 30.325 31.056 30.515 ;
     RECT  29.712 30.515 31.056 31.379 ;
     RECT  67.608 30.661 68.688 32.005 ;
     RECT  33.672 30.757 34.8 31.955 ;
     RECT  57.768 30.803 58.8 33.443 ;
     RECT  43.368 30.997 44.544 31.909 ;
     RECT  54.264 31.091 55.44 32.771 ;
     RECT  83.712 31.093 84.96 33.299 ;
     RECT  84.984 31.093 86.1 33.299 ;
     RECT  35.88 31.187 37.296 32.917 ;
     RECT  41.208 31.285 42.192 32.963 ;
     RECT  68.712 31.285 69.792 32.291 ;
     RECT  29.712 31.379 31.584 31.669 ;
     RECT  45.912 31.379 47.952 32.101 ;
     RECT  72.48 31.427 72.6 31.669 ;
     RECT  30.12 31.669 31.584 34.067 ;
     RECT  71.304 31.669 72.6 32.149 ;
     RECT  43.56 31.909 44.544 33.107 ;
     RECT  27.144 31.955 28.368 32.243 ;
     RECT  33.48 31.955 34.8 32.869 ;
     RECT  65.592 32.005 66.672 33.253 ;
     RECT  45.912 32.101 46.944 36.515 ;
     RECT  46.968 32.101 47.952 34.117 ;
     RECT  71.544 32.149 72.6 36.275 ;
     RECT  70.344 32.195 71.52 35.411 ;
     RECT  27.012 32.243 28.368 37.139 ;
     RECT  68.712 32.291 69.9 32.771 ;
     RECT  126.912 32.293 128.064 37.045 ;
     RECT  128.088 32.293 129.3 33.925 ;
     RECT  54.264 32.771 55.584 33.973 ;
     RECT  33.48 32.869 34.704 33.059 ;
     RECT  48.792 32.869 50.256 35.315 ;
     RECT  35.928 32.917 37.296 33.059 ;
     RECT  41.208 32.963 42.624 33.013 ;
     RECT  41.256 33.013 42.624 33.635 ;
     RECT  33.48 33.059 34.8 33.587 ;
     RECT  35.784 33.059 37.296 34.069 ;
     RECT  60.168 33.059 61.152 34.259 ;
     RECT  2.712 33.107 2.808 33.877 ;
     RECT  43.56 33.107 45.36 34.069 ;
     RECT  57.576 33.443 58.8 34.115 ;
     RECT  33.432 33.587 34.8 33.779 ;
     RECT  41.256 33.635 42.9 34.741 ;
     RECT  66.168 33.683 67.2 36.275 ;
     RECT  38.808 33.875 40.2 35.699 ;
     RECT  2.712 33.877 3.984 34.787 ;
     RECT  4.008 33.923 5.1 34.787 ;
     RECT  54.552 33.973 55.584 34.741 ;
     RECT  36.264 34.069 37.296 34.211 ;
     RECT  43.56 34.069 44.544 34.117 ;
     RECT  57.432 34.115 58.8 34.403 ;
     RECT  62.424 34.115 64.5 35.317 ;
     RECT  113.412 34.165 114.384 35.173 ;
     RECT  114.408 34.165 115.8 34.885 ;
     RECT  36.168 34.211 37.296 35.365 ;
     RECT  46.968 34.259 48 34.787 ;
     RECT  67.8 34.357 68.976 34.501 ;
     RECT  67.992 34.501 68.976 34.691 ;
     RECT  67.8 34.691 68.976 35.315 ;
     RECT  41.256 34.741 42.432 35.125 ;
     RECT  130.584 34.741 132 36.515 ;
     RECT  251.112 34.741 252.192 36.277 ;
     RECT  252.216 34.741 253.5 35.317 ;
     RECT  4.8 34.787 5.1 35.269 ;
     RECT  46.968 34.787 48.3 36.515 ;
     RECT  54.696 34.787 55.824 34.883 ;
     RECT  114.552 34.885 115.8 35.989 ;
     RECT  28.392 34.931 29.4 37.139 ;
     RECT  41.352 35.125 42.432 36.515 ;
     RECT  5.784 35.219 6.864 35.363 ;
     RECT  43.212 35.315 44.544 35.699 ;
     RECT  113.412 35.315 114.528 36.035 ;
     RECT  62.424 35.317 63.504 35.411 ;
     RECT  63.528 35.317 64.5 35.507 ;
     RECT  252.216 35.317 253.392 35.509 ;
     RECT  5.784 35.363 7.296 36.515 ;
     RECT  9.096 35.363 10.368 36.661 ;
     RECT  54.012 35.363 54.552 36.517 ;
     RECT  62.112 35.411 63.504 35.507 ;
     RECT  70.212 35.411 71.52 36.275 ;
     RECT  40.032 35.699 40.2 36.037 ;
     RECT  64.812 36.035 66.144 36.275 ;
     RECT  113.412 36.035 114.96 36.997 ;
     RECT  251.208 36.277 252.192 39.347 ;
     RECT  51.672 36.421 52.992 36.899 ;
     RECT  41.352 36.515 42.624 37.235 ;
     RECT  45.912 36.515 48.3 36.709 ;
     RECT  131.232 36.515 132 36.997 ;
     RECT  9.384 36.661 10.368 36.851 ;
     RECT  45.912 36.709 47.328 36.851 ;
     RECT  9.384 36.851 10.5 38.243 ;
     RECT  180.912 36.901 182.4 38.003 ;
     RECT  113.976 36.997 114.96 37.669 ;
     RECT  41.256 37.235 42.624 37.283 ;
     RECT  126.912 37.379 128.064 41.363 ;
     RECT  31.584 37.571 32.1 37.669 ;
     RECT  224.112 37.573 225.168 38.675 ;
     RECT  225.192 37.573 226.5 38.629 ;
     RECT  8.112 37.619 9.36 38.243 ;
     RECT  128.088 37.619 129.3 41.363 ;
     RECT  29.712 37.669 30.768 37.811 ;
     RECT  30.792 37.669 32.1 37.811 ;
     RECT  119.928 37.669 121.008 37.811 ;
     RECT  117.432 38.149 118.5 40.645 ;
     RECT  121.512 38.149 122.544 38.725 ;
     RECT  122.568 38.149 123.9 39.733 ;
     RECT  173.256 38.677 174.72 41.411 ;
     RECT  35.112 39.203 36.144 41.075 ;
     RECT  251.208 39.347 252.288 41.651 ;
     RECT  113.412 39.923 114.816 41.557 ;
     RECT  119.592 41.173 121.008 41.605 ;
     RECT  113.592 41.557 114.816 44.099 ;
     RECT  119.592 41.605 120.912 43.861 ;
     RECT  251.112 41.651 252.288 42.803 ;
     RECT  252.312 42.227 253.5 42.803 ;
     RECT  117.432 43.331 118.5 43.955 ;
     RECT  116.112 43.763 117.408 43.955 ;
     RECT  116.112 43.955 118.5 44.965 ;
     RECT  35.112 44.437 36.432 46.165 ;
     RECT  121.992 44.915 122.976 45.443 ;
     RECT  116.112 44.965 117.456 47.363 ;
     RECT  117.48 44.965 118.5 46.693 ;
     RECT  121.992 45.443 123.9 46.021 ;
     RECT  122.52 46.021 123.9 46.501 ;
     RECT  122.76 46.501 123.9 47.269 ;
     RECT  119.592 47.075 120.912 47.651 ;
     RECT  121.512 47.075 122.496 48.563 ;
  END
END qkd_d2d_cal_seq_pin_ovl_rope
END LIBRARY
